VERSION 5.8 ;
BUSBITCHARS "[]" ;
DIVIDERCHAR "/" ;
UNITS
    DATABASE MICRONS 1000 ;
END UNITS

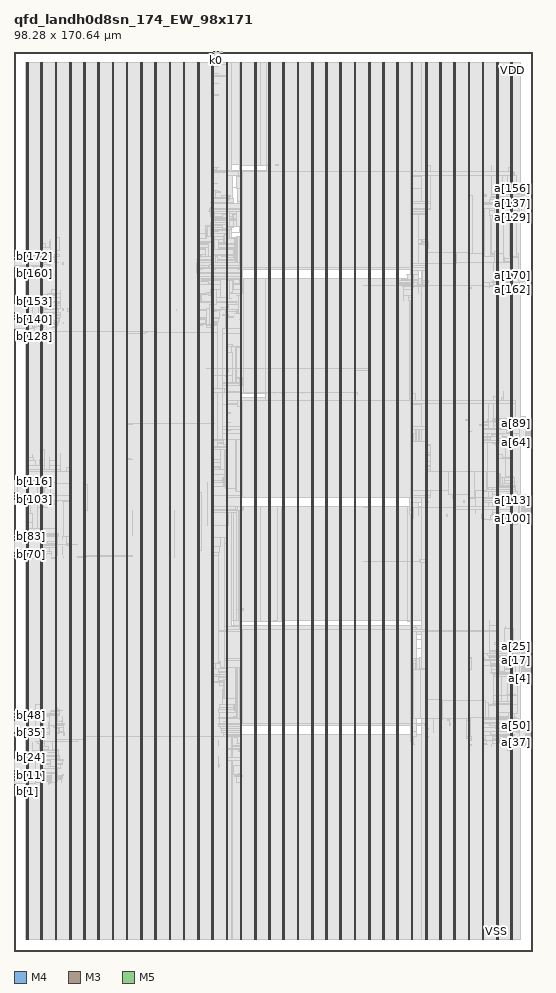
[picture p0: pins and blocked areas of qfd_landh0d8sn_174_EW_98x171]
MACRO qfd_landh0d8sn_174_EW_98x171
  FOREIGN qfd_landh0d8sn_174_EW_98x171 0 0 ;
  CLASS BLOCK ;
  SIZE 98.28 BY 170.64 ;
  PIN a[0]
    DIRECTION INPUT ;
    USE SIGNAL ;
    PORT
      LAYER M4 ;
        RECT  98.196 52.56 98.28 52.584 ;
    END
  END a[0]
  PIN a[100]
    DIRECTION INPUT ;
    USE SIGNAL ;
    PORT
      LAYER M4 ;
        RECT  98.196 81.936 98.28 81.96 ;
    END
  END a[100]
  PIN a[101]
    DIRECTION INPUT ;
    USE SIGNAL ;
    PORT
      LAYER M4 ;
        RECT  98.196 82.08 98.28 82.104 ;
    END
  END a[101]
  PIN a[102]
    DIRECTION INPUT ;
    USE SIGNAL ;
    PORT
      LAYER M4 ;
        RECT  98.196 82.224 98.28 82.248 ;
    END
  END a[102]
  PIN a[103]
    DIRECTION INPUT ;
    USE SIGNAL ;
    PORT
      LAYER M4 ;
        RECT  98.196 82.368 98.28 82.392 ;
    END
  END a[103]
  PIN a[104]
    DIRECTION INPUT ;
    USE SIGNAL ;
    PORT
      LAYER M4 ;
        RECT  98.196 82.512 98.28 82.536 ;
    END
  END a[104]
  PIN a[105]
    DIRECTION INPUT ;
    USE SIGNAL ;
    PORT
      LAYER M4 ;
        RECT  98.196 82.656 98.28 82.68 ;
    END
  END a[105]
  PIN a[106]
    DIRECTION INPUT ;
    USE SIGNAL ;
    PORT
      LAYER M4 ;
        RECT  98.196 82.8 98.28 82.824 ;
    END
  END a[106]
  PIN a[107]
    DIRECTION INPUT ;
    USE SIGNAL ;
    PORT
      LAYER M4 ;
        RECT  98.196 82.944 98.28 82.968 ;
    END
  END a[107]
  PIN a[108]
    DIRECTION INPUT ;
    USE SIGNAL ;
    PORT
      LAYER M4 ;
        RECT  98.196 83.088 98.28 83.112 ;
    END
  END a[108]
  PIN a[109]
    DIRECTION INPUT ;
    USE SIGNAL ;
    PORT
      LAYER M4 ;
        RECT  98.196 83.232 98.28 83.256 ;
    END
  END a[109]
  PIN a[10]
    DIRECTION INPUT ;
    USE SIGNAL ;
    PORT
      LAYER M4 ;
        RECT  98.196 54 98.28 54.024 ;
    END
  END a[10]
  PIN a[110]
    DIRECTION INPUT ;
    USE SIGNAL ;
    PORT
      LAYER M4 ;
        RECT  98.196 83.376 98.28 83.4 ;
    END
  END a[110]
  PIN a[111]
    DIRECTION INPUT ;
    USE SIGNAL ;
    PORT
      LAYER M4 ;
        RECT  98.196 83.52 98.28 83.544 ;
    END
  END a[111]
  PIN a[112]
    DIRECTION INPUT ;
    USE SIGNAL ;
    PORT
      LAYER M4 ;
        RECT  98.196 83.664 98.28 83.688 ;
    END
  END a[112]
  PIN a[113]
    DIRECTION INPUT ;
    USE SIGNAL ;
    PORT
      LAYER M4 ;
        RECT  98.196 83.808 98.28 83.832 ;
    END
  END a[113]
  PIN a[114]
    DIRECTION INPUT ;
    USE SIGNAL ;
    PORT
      LAYER M4 ;
        RECT  98.196 83.952 98.28 83.976 ;
    END
  END a[114]
  PIN a[115]
    DIRECTION INPUT ;
    USE SIGNAL ;
    PORT
      LAYER M4 ;
        RECT  98.196 84.096 98.28 84.12 ;
    END
  END a[115]
  PIN a[116]
    DIRECTION INPUT ;
    USE SIGNAL ;
    PORT
      LAYER M4 ;
        RECT  98.196 84.24 98.28 84.264 ;
    END
  END a[116]
  PIN a[117]
    DIRECTION INPUT ;
    USE SIGNAL ;
    PORT
      LAYER M4 ;
        RECT  98.196 84.384 98.28 84.408 ;
    END
  END a[117]
  PIN a[118]
    DIRECTION INPUT ;
    USE SIGNAL ;
    PORT
      LAYER M4 ;
        RECT  98.196 84.528 98.28 84.552 ;
    END
  END a[118]
  PIN a[119]
    DIRECTION INPUT ;
    USE SIGNAL ;
    PORT
      LAYER M4 ;
        RECT  98.196 84.672 98.28 84.696 ;
    END
  END a[119]
  PIN a[11]
    DIRECTION INPUT ;
    USE SIGNAL ;
    PORT
      LAYER M4 ;
        RECT  98.196 54.144 98.28 54.168 ;
    END
  END a[11]
  PIN a[120]
    DIRECTION INPUT ;
    USE SIGNAL ;
    PORT
      LAYER M4 ;
        RECT  98.196 84.816 98.28 84.84 ;
    END
  END a[120]
  PIN a[121]
    DIRECTION INPUT ;
    USE SIGNAL ;
    PORT
      LAYER M4 ;
        RECT  98.196 84.96 98.28 84.984 ;
    END
  END a[121]
  PIN a[122]
    DIRECTION INPUT ;
    USE SIGNAL ;
    PORT
      LAYER M4 ;
        RECT  98.196 85.104 98.28 85.128 ;
    END
  END a[122]
  PIN a[123]
    DIRECTION INPUT ;
    USE SIGNAL ;
    PORT
      LAYER M4 ;
        RECT  98.196 85.248 98.28 85.272 ;
    END
  END a[123]
  PIN a[124]
    DIRECTION INPUT ;
    USE SIGNAL ;
    PORT
      LAYER M4 ;
        RECT  98.196 85.392 98.28 85.416 ;
    END
  END a[124]
  PIN a[125]
    DIRECTION INPUT ;
    USE SIGNAL ;
    PORT
      LAYER M4 ;
        RECT  98.196 85.536 98.28 85.56 ;
    END
  END a[125]
  PIN a[126]
    DIRECTION INPUT ;
    USE SIGNAL ;
    PORT
      LAYER M4 ;
        RECT  98.196 85.68 98.28 85.704 ;
    END
  END a[126]
  PIN a[127]
    DIRECTION INPUT ;
    USE SIGNAL ;
    PORT
      LAYER M4 ;
        RECT  98.196 85.824 98.28 85.848 ;
    END
  END a[127]
  PIN a[128]
    DIRECTION INPUT ;
    USE SIGNAL ;
    PORT
      LAYER M4 ;
        RECT  98.196 138.96 98.28 138.984 ;
    END
  END a[128]
  PIN a[129]
    DIRECTION INPUT ;
    USE SIGNAL ;
    PORT
      LAYER M4 ;
        RECT  98.196 139.104 98.28 139.128 ;
    END
  END a[129]
  PIN a[12]
    DIRECTION INPUT ;
    USE SIGNAL ;
    PORT
      LAYER M4 ;
        RECT  98.196 54.288 98.28 54.312 ;
    END
  END a[12]
  PIN a[130]
    DIRECTION INPUT ;
    USE SIGNAL ;
    PORT
      LAYER M4 ;
        RECT  98.196 139.248 98.28 139.272 ;
    END
  END a[130]
  PIN a[131]
    DIRECTION INPUT ;
    USE SIGNAL ;
    PORT
      LAYER M4 ;
        RECT  98.196 139.392 98.28 139.416 ;
    END
  END a[131]
  PIN a[132]
    DIRECTION INPUT ;
    USE SIGNAL ;
    PORT
      LAYER M4 ;
        RECT  98.196 139.536 98.28 139.56 ;
    END
  END a[132]
  PIN a[133]
    DIRECTION INPUT ;
    USE SIGNAL ;
    PORT
      LAYER M4 ;
        RECT  98.196 139.68 98.28 139.704 ;
    END
  END a[133]
  PIN a[134]
    DIRECTION INPUT ;
    USE SIGNAL ;
    PORT
      LAYER M4 ;
        RECT  98.196 139.824 98.28 139.848 ;
    END
  END a[134]
  PIN a[135]
    DIRECTION INPUT ;
    USE SIGNAL ;
    PORT
      LAYER M4 ;
        RECT  98.196 139.968 98.28 139.992 ;
    END
  END a[135]
  PIN a[136]
    DIRECTION INPUT ;
    USE SIGNAL ;
    PORT
      LAYER M4 ;
        RECT  98.196 140.112 98.28 140.136 ;
    END
  END a[136]
  PIN a[137]
    DIRECTION INPUT ;
    USE SIGNAL ;
    PORT
      LAYER M4 ;
        RECT  98.196 140.256 98.28 140.28 ;
    END
  END a[137]
  PIN a[138]
    DIRECTION INPUT ;
    USE SIGNAL ;
    PORT
      LAYER M4 ;
        RECT  98.196 140.4 98.28 140.424 ;
    END
  END a[138]
  PIN a[139]
    DIRECTION INPUT ;
    USE SIGNAL ;
    PORT
      LAYER M4 ;
        RECT  98.196 140.544 98.28 140.568 ;
    END
  END a[139]
  PIN a[13]
    DIRECTION INPUT ;
    USE SIGNAL ;
    PORT
      LAYER M4 ;
        RECT  98.196 54.432 98.28 54.456 ;
    END
  END a[13]
  PIN a[140]
    DIRECTION INPUT ;
    USE SIGNAL ;
    PORT
      LAYER M4 ;
        RECT  98.196 140.688 98.28 140.712 ;
    END
  END a[140]
  PIN a[141]
    DIRECTION INPUT ;
    USE SIGNAL ;
    PORT
      LAYER M4 ;
        RECT  98.196 140.832 98.28 140.856 ;
    END
  END a[141]
  PIN a[142]
    DIRECTION INPUT ;
    USE SIGNAL ;
    PORT
      LAYER M4 ;
        RECT  98.196 140.976 98.28 141 ;
    END
  END a[142]
  PIN a[143]
    DIRECTION INPUT ;
    USE SIGNAL ;
    PORT
      LAYER M4 ;
        RECT  98.196 141.12 98.28 141.144 ;
    END
  END a[143]
  PIN a[144]
    DIRECTION INPUT ;
    USE SIGNAL ;
    PORT
      LAYER M4 ;
        RECT  98.196 141.264 98.28 141.288 ;
    END
  END a[144]
  PIN a[145]
    DIRECTION INPUT ;
    USE SIGNAL ;
    PORT
      LAYER M4 ;
        RECT  98.196 141.408 98.28 141.432 ;
    END
  END a[145]
  PIN a[146]
    DIRECTION INPUT ;
    USE SIGNAL ;
    PORT
      LAYER M4 ;
        RECT  98.196 141.552 98.28 141.576 ;
    END
  END a[146]
  PIN a[147]
    DIRECTION INPUT ;
    USE SIGNAL ;
    PORT
      LAYER M4 ;
        RECT  98.196 141.696 98.28 141.72 ;
    END
  END a[147]
  PIN a[148]
    DIRECTION INPUT ;
    USE SIGNAL ;
    PORT
      LAYER M4 ;
        RECT  98.196 141.84 98.28 141.864 ;
    END
  END a[148]
  PIN a[149]
    DIRECTION INPUT ;
    USE SIGNAL ;
    PORT
      LAYER M4 ;
        RECT  98.196 141.984 98.28 142.008 ;
    END
  END a[149]
  PIN a[14]
    DIRECTION INPUT ;
    USE SIGNAL ;
    PORT
      LAYER M4 ;
        RECT  98.196 54.576 98.28 54.6 ;
    END
  END a[14]
  PIN a[150]
    DIRECTION INPUT ;
    USE SIGNAL ;
    PORT
      LAYER M4 ;
        RECT  98.196 142.128 98.28 142.152 ;
    END
  END a[150]
  PIN a[151]
    DIRECTION INPUT ;
    USE SIGNAL ;
    PORT
      LAYER M4 ;
        RECT  98.196 142.272 98.28 142.296 ;
    END
  END a[151]
  PIN a[152]
    DIRECTION INPUT ;
    USE SIGNAL ;
    PORT
      LAYER M4 ;
        RECT  98.196 142.416 98.28 142.44 ;
    END
  END a[152]
  PIN a[153]
    DIRECTION INPUT ;
    USE SIGNAL ;
    PORT
      LAYER M4 ;
        RECT  98.196 142.56 98.28 142.584 ;
    END
  END a[153]
  PIN a[154]
    DIRECTION INPUT ;
    USE SIGNAL ;
    PORT
      LAYER M4 ;
        RECT  98.196 142.704 98.28 142.728 ;
    END
  END a[154]
  PIN a[155]
    DIRECTION INPUT ;
    USE SIGNAL ;
    PORT
      LAYER M4 ;
        RECT  98.196 142.848 98.28 142.872 ;
    END
  END a[155]
  PIN a[156]
    DIRECTION INPUT ;
    USE SIGNAL ;
    PORT
      LAYER M4 ;
        RECT  98.196 142.992 98.28 143.016 ;
    END
  END a[156]
  PIN a[157]
    DIRECTION INPUT ;
    USE SIGNAL ;
    PORT
      LAYER M4 ;
        RECT  98.196 143.136 98.28 143.16 ;
    END
  END a[157]
  PIN a[158]
    DIRECTION INPUT ;
    USE SIGNAL ;
    PORT
      LAYER M4 ;
        RECT  98.196 143.28 98.28 143.304 ;
    END
  END a[158]
  PIN a[159]
    DIRECTION INPUT ;
    USE SIGNAL ;
    PORT
      LAYER M4 ;
        RECT  98.196 143.424 98.28 143.448 ;
    END
  END a[159]
  PIN a[15]
    DIRECTION INPUT ;
    USE SIGNAL ;
    PORT
      LAYER M4 ;
        RECT  98.196 54.72 98.28 54.744 ;
    END
  END a[15]
  PIN a[160]
    DIRECTION INPUT ;
    USE SIGNAL ;
    PORT
      LAYER M4 ;
        RECT  98.196 125.136 98.28 125.16 ;
    END
  END a[160]
  PIN a[161]
    DIRECTION INPUT ;
    USE SIGNAL ;
    PORT
      LAYER M4 ;
        RECT  98.196 125.28 98.28 125.304 ;
    END
  END a[161]
  PIN a[162]
    DIRECTION INPUT ;
    USE SIGNAL ;
    PORT
      LAYER M4 ;
        RECT  98.196 125.424 98.28 125.448 ;
    END
  END a[162]
  PIN a[163]
    DIRECTION INPUT ;
    USE SIGNAL ;
    PORT
      LAYER M4 ;
        RECT  98.196 125.568 98.28 125.592 ;
    END
  END a[163]
  PIN a[164]
    DIRECTION INPUT ;
    USE SIGNAL ;
    PORT
      LAYER M4 ;
        RECT  98.196 125.712 98.28 125.736 ;
    END
  END a[164]
  PIN a[165]
    DIRECTION INPUT ;
    USE SIGNAL ;
    PORT
      LAYER M4 ;
        RECT  98.196 125.856 98.28 125.88 ;
    END
  END a[165]
  PIN a[166]
    DIRECTION INPUT ;
    USE SIGNAL ;
    PORT
      LAYER M4 ;
        RECT  98.196 126 98.28 126.024 ;
    END
  END a[166]
  PIN a[167]
    DIRECTION INPUT ;
    USE SIGNAL ;
    PORT
      LAYER M4 ;
        RECT  98.196 126.144 98.28 126.168 ;
    END
  END a[167]
  PIN a[168]
    DIRECTION INPUT ;
    USE SIGNAL ;
    PORT
      LAYER M4 ;
        RECT  98.196 126.288 98.28 126.312 ;
    END
  END a[168]
  PIN a[169]
    DIRECTION INPUT ;
    USE SIGNAL ;
    PORT
      LAYER M4 ;
        RECT  98.196 126.432 98.28 126.456 ;
    END
  END a[169]
  PIN a[16]
    DIRECTION INPUT ;
    USE SIGNAL ;
    PORT
      LAYER M4 ;
        RECT  98.196 54.864 98.28 54.888 ;
    END
  END a[16]
  PIN a[170]
    DIRECTION INPUT ;
    USE SIGNAL ;
    PORT
      LAYER M4 ;
        RECT  98.196 126.576 98.28 126.6 ;
    END
  END a[170]
  PIN a[171]
    DIRECTION INPUT ;
    USE SIGNAL ;
    PORT
      LAYER M4 ;
        RECT  98.196 126.72 98.28 126.744 ;
    END
  END a[171]
  PIN a[172]
    DIRECTION INPUT ;
    USE SIGNAL ;
    PORT
      LAYER M4 ;
        RECT  98.196 126.864 98.28 126.888 ;
    END
  END a[172]
  PIN a[173]
    DIRECTION INPUT ;
    USE SIGNAL ;
    PORT
      LAYER M4 ;
        RECT  98.196 127.008 98.28 127.032 ;
    END
  END a[173]
  PIN a[17]
    DIRECTION INPUT ;
    USE SIGNAL ;
    PORT
      LAYER M4 ;
        RECT  98.196 55.008 98.28 55.032 ;
    END
  END a[17]
  PIN a[18]
    DIRECTION INPUT ;
    USE SIGNAL ;
    PORT
      LAYER M4 ;
        RECT  98.196 55.152 98.28 55.176 ;
    END
  END a[18]
  PIN a[19]
    DIRECTION INPUT ;
    USE SIGNAL ;
    PORT
      LAYER M4 ;
        RECT  98.196 55.296 98.28 55.32 ;
    END
  END a[19]
  PIN a[1]
    DIRECTION INPUT ;
    USE SIGNAL ;
    PORT
      LAYER M4 ;
        RECT  98.196 52.704 98.28 52.728 ;
    END
  END a[1]
  PIN a[20]
    DIRECTION INPUT ;
    USE SIGNAL ;
    PORT
      LAYER M4 ;
        RECT  98.196 55.44 98.28 55.464 ;
    END
  END a[20]
  PIN a[21]
    DIRECTION INPUT ;
    USE SIGNAL ;
    PORT
      LAYER M4 ;
        RECT  98.196 55.584 98.28 55.608 ;
    END
  END a[21]
  PIN a[22]
    DIRECTION INPUT ;
    USE SIGNAL ;
    PORT
      LAYER M4 ;
        RECT  98.196 55.728 98.28 55.752 ;
    END
  END a[22]
  PIN a[23]
    DIRECTION INPUT ;
    USE SIGNAL ;
    PORT
      LAYER M4 ;
        RECT  98.196 55.872 98.28 55.896 ;
    END
  END a[23]
  PIN a[24]
    DIRECTION INPUT ;
    USE SIGNAL ;
    PORT
      LAYER M4 ;
        RECT  98.196 56.016 98.28 56.04 ;
    END
  END a[24]
  PIN a[25]
    DIRECTION INPUT ;
    USE SIGNAL ;
    PORT
      LAYER M4 ;
        RECT  98.196 56.16 98.28 56.184 ;
    END
  END a[25]
  PIN a[26]
    DIRECTION INPUT ;
    USE SIGNAL ;
    PORT
      LAYER M4 ;
        RECT  98.196 56.304 98.28 56.328 ;
    END
  END a[26]
  PIN a[27]
    DIRECTION INPUT ;
    USE SIGNAL ;
    PORT
      LAYER M4 ;
        RECT  98.196 56.448 98.28 56.472 ;
    END
  END a[27]
  PIN a[28]
    DIRECTION INPUT ;
    USE SIGNAL ;
    PORT
      LAYER M4 ;
        RECT  98.196 56.592 98.28 56.616 ;
    END
  END a[28]
  PIN a[29]
    DIRECTION INPUT ;
    USE SIGNAL ;
    PORT
      LAYER M4 ;
        RECT  98.196 56.736 98.28 56.76 ;
    END
  END a[29]
  PIN a[2]
    DIRECTION INPUT ;
    USE SIGNAL ;
    PORT
      LAYER M4 ;
        RECT  98.196 52.848 98.28 52.872 ;
    END
  END a[2]
  PIN a[30]
    DIRECTION INPUT ;
    USE SIGNAL ;
    PORT
      LAYER M4 ;
        RECT  98.196 56.88 98.28 56.904 ;
    END
  END a[30]
  PIN a[31]
    DIRECTION INPUT ;
    USE SIGNAL ;
    PORT
      LAYER M4 ;
        RECT  98.196 57.024 98.28 57.048 ;
    END
  END a[31]
  PIN a[32]
    DIRECTION INPUT ;
    USE SIGNAL ;
    PORT
      LAYER M4 ;
        RECT  98.196 38.736 98.28 38.76 ;
    END
  END a[32]
  PIN a[33]
    DIRECTION INPUT ;
    USE SIGNAL ;
    PORT
      LAYER M4 ;
        RECT  98.196 38.88 98.28 38.904 ;
    END
  END a[33]
  PIN a[34]
    DIRECTION INPUT ;
    USE SIGNAL ;
    PORT
      LAYER M4 ;
        RECT  98.196 39.024 98.28 39.048 ;
    END
  END a[34]
  PIN a[35]
    DIRECTION INPUT ;
    USE SIGNAL ;
    PORT
      LAYER M4 ;
        RECT  98.196 39.168 98.28 39.192 ;
    END
  END a[35]
  PIN a[36]
    DIRECTION INPUT ;
    USE SIGNAL ;
    PORT
      LAYER M4 ;
        RECT  98.196 39.312 98.28 39.336 ;
    END
  END a[36]
  PIN a[37]
    DIRECTION INPUT ;
    USE SIGNAL ;
    PORT
      LAYER M4 ;
        RECT  98.196 39.456 98.28 39.48 ;
    END
  END a[37]
  PIN a[38]
    DIRECTION INPUT ;
    USE SIGNAL ;
    PORT
      LAYER M4 ;
        RECT  98.196 39.6 98.28 39.624 ;
    END
  END a[38]
  PIN a[39]
    DIRECTION INPUT ;
    USE SIGNAL ;
    PORT
      LAYER M4 ;
        RECT  98.196 39.744 98.28 39.768 ;
    END
  END a[39]
  PIN a[3]
    DIRECTION INPUT ;
    USE SIGNAL ;
    PORT
      LAYER M4 ;
        RECT  98.196 52.992 98.28 53.016 ;
    END
  END a[3]
  PIN a[40]
    DIRECTION INPUT ;
    USE SIGNAL ;
    PORT
      LAYER M4 ;
        RECT  98.196 39.888 98.28 39.912 ;
    END
  END a[40]
  PIN a[41]
    DIRECTION INPUT ;
    USE SIGNAL ;
    PORT
      LAYER M4 ;
        RECT  98.196 40.032 98.28 40.056 ;
    END
  END a[41]
  PIN a[42]
    DIRECTION INPUT ;
    USE SIGNAL ;
    PORT
      LAYER M4 ;
        RECT  98.196 40.176 98.28 40.2 ;
    END
  END a[42]
  PIN a[43]
    DIRECTION INPUT ;
    USE SIGNAL ;
    PORT
      LAYER M4 ;
        RECT  98.196 40.32 98.28 40.344 ;
    END
  END a[43]
  PIN a[44]
    DIRECTION INPUT ;
    USE SIGNAL ;
    PORT
      LAYER M4 ;
        RECT  98.196 40.464 98.28 40.488 ;
    END
  END a[44]
  PIN a[45]
    DIRECTION INPUT ;
    USE SIGNAL ;
    PORT
      LAYER M4 ;
        RECT  98.196 40.608 98.28 40.632 ;
    END
  END a[45]
  PIN a[46]
    DIRECTION INPUT ;
    USE SIGNAL ;
    PORT
      LAYER M4 ;
        RECT  98.196 40.752 98.28 40.776 ;
    END
  END a[46]
  PIN a[47]
    DIRECTION INPUT ;
    USE SIGNAL ;
    PORT
      LAYER M4 ;
        RECT  98.196 40.896 98.28 40.92 ;
    END
  END a[47]
  PIN a[48]
    DIRECTION INPUT ;
    USE SIGNAL ;
    PORT
      LAYER M4 ;
        RECT  98.196 41.04 98.28 41.064 ;
    END
  END a[48]
  PIN a[49]
    DIRECTION INPUT ;
    USE SIGNAL ;
    PORT
      LAYER M4 ;
        RECT  98.196 41.184 98.28 41.208 ;
    END
  END a[49]
  PIN a[4]
    DIRECTION INPUT ;
    USE SIGNAL ;
    PORT
      LAYER M4 ;
        RECT  98.196 53.136 98.28 53.16 ;
    END
  END a[4]
  PIN a[50]
    DIRECTION INPUT ;
    USE SIGNAL ;
    PORT
      LAYER M4 ;
        RECT  98.196 41.328 98.28 41.352 ;
    END
  END a[50]
  PIN a[51]
    DIRECTION INPUT ;
    USE SIGNAL ;
    PORT
      LAYER M4 ;
        RECT  98.196 41.472 98.28 41.496 ;
    END
  END a[51]
  PIN a[52]
    DIRECTION INPUT ;
    USE SIGNAL ;
    PORT
      LAYER M4 ;
        RECT  98.196 41.616 98.28 41.64 ;
    END
  END a[52]
  PIN a[53]
    DIRECTION INPUT ;
    USE SIGNAL ;
    PORT
      LAYER M4 ;
        RECT  98.196 41.76 98.28 41.784 ;
    END
  END a[53]
  PIN a[54]
    DIRECTION INPUT ;
    USE SIGNAL ;
    PORT
      LAYER M4 ;
        RECT  98.196 41.904 98.28 41.928 ;
    END
  END a[54]
  PIN a[55]
    DIRECTION INPUT ;
    USE SIGNAL ;
    PORT
      LAYER M4 ;
        RECT  98.196 42.048 98.28 42.072 ;
    END
  END a[55]
  PIN a[56]
    DIRECTION INPUT ;
    USE SIGNAL ;
    PORT
      LAYER M4 ;
        RECT  98.196 42.192 98.28 42.216 ;
    END
  END a[56]
  PIN a[57]
    DIRECTION INPUT ;
    USE SIGNAL ;
    PORT
      LAYER M4 ;
        RECT  98.196 42.336 98.28 42.36 ;
    END
  END a[57]
  PIN a[58]
    DIRECTION INPUT ;
    USE SIGNAL ;
    PORT
      LAYER M4 ;
        RECT  98.196 42.48 98.28 42.504 ;
    END
  END a[58]
  PIN a[59]
    DIRECTION INPUT ;
    USE SIGNAL ;
    PORT
      LAYER M4 ;
        RECT  98.196 42.624 98.28 42.648 ;
    END
  END a[59]
  PIN a[5]
    DIRECTION INPUT ;
    USE SIGNAL ;
    PORT
      LAYER M4 ;
        RECT  98.196 53.28 98.28 53.304 ;
    END
  END a[5]
  PIN a[60]
    DIRECTION INPUT ;
    USE SIGNAL ;
    PORT
      LAYER M4 ;
        RECT  98.196 42.768 98.28 42.792 ;
    END
  END a[60]
  PIN a[61]
    DIRECTION INPUT ;
    USE SIGNAL ;
    PORT
      LAYER M4 ;
        RECT  98.196 42.912 98.28 42.936 ;
    END
  END a[61]
  PIN a[62]
    DIRECTION INPUT ;
    USE SIGNAL ;
    PORT
      LAYER M4 ;
        RECT  98.196 43.056 98.28 43.08 ;
    END
  END a[62]
  PIN a[63]
    DIRECTION INPUT ;
    USE SIGNAL ;
    PORT
      LAYER M4 ;
        RECT  98.196 43.2 98.28 43.224 ;
    END
  END a[63]
  PIN a[64]
    DIRECTION INPUT ;
    USE SIGNAL ;
    PORT
      LAYER M4 ;
        RECT  98.196 96.336 98.28 96.36 ;
    END
  END a[64]
  PIN a[65]
    DIRECTION INPUT ;
    USE SIGNAL ;
    PORT
      LAYER M4 ;
        RECT  98.196 96.48 98.28 96.504 ;
    END
  END a[65]
  PIN a[66]
    DIRECTION INPUT ;
    USE SIGNAL ;
    PORT
      LAYER M4 ;
        RECT  98.196 96.624 98.28 96.648 ;
    END
  END a[66]
  PIN a[67]
    DIRECTION INPUT ;
    USE SIGNAL ;
    PORT
      LAYER M4 ;
        RECT  98.196 96.768 98.28 96.792 ;
    END
  END a[67]
  PIN a[68]
    DIRECTION INPUT ;
    USE SIGNAL ;
    PORT
      LAYER M4 ;
        RECT  98.196 96.912 98.28 96.936 ;
    END
  END a[68]
  PIN a[69]
    DIRECTION INPUT ;
    USE SIGNAL ;
    PORT
      LAYER M4 ;
        RECT  98.196 97.056 98.28 97.08 ;
    END
  END a[69]
  PIN a[6]
    DIRECTION INPUT ;
    USE SIGNAL ;
    PORT
      LAYER M4 ;
        RECT  98.196 53.424 98.28 53.448 ;
    END
  END a[6]
  PIN a[70]
    DIRECTION INPUT ;
    USE SIGNAL ;
    PORT
      LAYER M4 ;
        RECT  98.196 97.2 98.28 97.224 ;
    END
  END a[70]
  PIN a[71]
    DIRECTION INPUT ;
    USE SIGNAL ;
    PORT
      LAYER M4 ;
        RECT  98.196 97.344 98.28 97.368 ;
    END
  END a[71]
  PIN a[72]
    DIRECTION INPUT ;
    USE SIGNAL ;
    PORT
      LAYER M4 ;
        RECT  98.196 97.488 98.28 97.512 ;
    END
  END a[72]
  PIN a[73]
    DIRECTION INPUT ;
    USE SIGNAL ;
    PORT
      LAYER M4 ;
        RECT  98.196 97.632 98.28 97.656 ;
    END
  END a[73]
  PIN a[74]
    DIRECTION INPUT ;
    USE SIGNAL ;
    PORT
      LAYER M4 ;
        RECT  98.196 97.776 98.28 97.8 ;
    END
  END a[74]
  PIN a[75]
    DIRECTION INPUT ;
    USE SIGNAL ;
    PORT
      LAYER M4 ;
        RECT  98.196 97.92 98.28 97.944 ;
    END
  END a[75]
  PIN a[76]
    DIRECTION INPUT ;
    USE SIGNAL ;
    PORT
      LAYER M4 ;
        RECT  98.196 98.064 98.28 98.088 ;
    END
  END a[76]
  PIN a[77]
    DIRECTION INPUT ;
    USE SIGNAL ;
    PORT
      LAYER M4 ;
        RECT  98.196 98.208 98.28 98.232 ;
    END
  END a[77]
  PIN a[78]
    DIRECTION INPUT ;
    USE SIGNAL ;
    PORT
      LAYER M4 ;
        RECT  98.196 98.352 98.28 98.376 ;
    END
  END a[78]
  PIN a[79]
    DIRECTION INPUT ;
    USE SIGNAL ;
    PORT
      LAYER M4 ;
        RECT  98.196 98.496 98.28 98.52 ;
    END
  END a[79]
  PIN a[7]
    DIRECTION INPUT ;
    USE SIGNAL ;
    PORT
      LAYER M4 ;
        RECT  98.196 53.568 98.28 53.592 ;
    END
  END a[7]
  PIN a[80]
    DIRECTION INPUT ;
    USE SIGNAL ;
    PORT
      LAYER M4 ;
        RECT  98.196 98.64 98.28 98.664 ;
    END
  END a[80]
  PIN a[81]
    DIRECTION INPUT ;
    USE SIGNAL ;
    PORT
      LAYER M4 ;
        RECT  98.196 98.784 98.28 98.808 ;
    END
  END a[81]
  PIN a[82]
    DIRECTION INPUT ;
    USE SIGNAL ;
    PORT
      LAYER M4 ;
        RECT  98.196 98.928 98.28 98.952 ;
    END
  END a[82]
  PIN a[83]
    DIRECTION INPUT ;
    USE SIGNAL ;
    PORT
      LAYER M4 ;
        RECT  98.196 99.072 98.28 99.096 ;
    END
  END a[83]
  PIN a[84]
    DIRECTION INPUT ;
    USE SIGNAL ;
    PORT
      LAYER M4 ;
        RECT  98.196 99.216 98.28 99.24 ;
    END
  END a[84]
  PIN a[85]
    DIRECTION INPUT ;
    USE SIGNAL ;
    PORT
      LAYER M4 ;
        RECT  98.196 99.36 98.28 99.384 ;
    END
  END a[85]
  PIN a[86]
    DIRECTION INPUT ;
    USE SIGNAL ;
    PORT
      LAYER M4 ;
        RECT  98.196 99.504 98.28 99.528 ;
    END
  END a[86]
  PIN a[87]
    DIRECTION INPUT ;
    USE SIGNAL ;
    PORT
      LAYER M4 ;
        RECT  98.196 99.648 98.28 99.672 ;
    END
  END a[87]
  PIN a[88]
    DIRECTION INPUT ;
    USE SIGNAL ;
    PORT
      LAYER M4 ;
        RECT  98.196 99.792 98.28 99.816 ;
    END
  END a[88]
  PIN a[89]
    DIRECTION INPUT ;
    USE SIGNAL ;
    PORT
      LAYER M4 ;
        RECT  98.196 99.936 98.28 99.96 ;
    END
  END a[89]
  PIN a[8]
    DIRECTION INPUT ;
    USE SIGNAL ;
    PORT
      LAYER M4 ;
        RECT  98.196 53.712 98.28 53.736 ;
    END
  END a[8]
  PIN a[90]
    DIRECTION INPUT ;
    USE SIGNAL ;
    PORT
      LAYER M4 ;
        RECT  98.196 100.08 98.28 100.104 ;
    END
  END a[90]
  PIN a[91]
    DIRECTION INPUT ;
    USE SIGNAL ;
    PORT
      LAYER M4 ;
        RECT  98.196 100.224 98.28 100.248 ;
    END
  END a[91]
  PIN a[92]
    DIRECTION INPUT ;
    USE SIGNAL ;
    PORT
      LAYER M4 ;
        RECT  98.196 100.368 98.28 100.392 ;
    END
  END a[92]
  PIN a[93]
    DIRECTION INPUT ;
    USE SIGNAL ;
    PORT
      LAYER M4 ;
        RECT  98.196 100.512 98.28 100.536 ;
    END
  END a[93]
  PIN a[94]
    DIRECTION INPUT ;
    USE SIGNAL ;
    PORT
      LAYER M4 ;
        RECT  98.196 100.656 98.28 100.68 ;
    END
  END a[94]
  PIN a[95]
    DIRECTION INPUT ;
    USE SIGNAL ;
    PORT
      LAYER M4 ;
        RECT  98.196 100.8 98.28 100.824 ;
    END
  END a[95]
  PIN a[96]
    DIRECTION INPUT ;
    USE SIGNAL ;
    PORT
      LAYER M4 ;
        RECT  98.196 81.36 98.28 81.384 ;
    END
  END a[96]
  PIN a[97]
    DIRECTION INPUT ;
    USE SIGNAL ;
    PORT
      LAYER M4 ;
        RECT  98.196 81.504 98.28 81.528 ;
    END
  END a[97]
  PIN a[98]
    DIRECTION INPUT ;
    USE SIGNAL ;
    PORT
      LAYER M4 ;
        RECT  98.196 81.648 98.28 81.672 ;
    END
  END a[98]
  PIN a[99]
    DIRECTION INPUT ;
    USE SIGNAL ;
    PORT
      LAYER M4 ;
        RECT  98.196 81.792 98.28 81.816 ;
    END
  END a[99]
  PIN a[9]
    DIRECTION INPUT ;
    USE SIGNAL ;
    PORT
      LAYER M4 ;
        RECT  98.196 53.856 98.28 53.88 ;
    END
  END a[9]
  PIN b[0]
    DIRECTION OUTPUT ;
    USE SIGNAL ;
    PORT
      LAYER M4 ;
        RECT  0 31.68 0.084 31.704 ;
    END
  END b[0]
  PIN b[100]
    DIRECTION OUTPUT ;
    USE SIGNAL ;
    PORT
      LAYER M4 ;
        RECT  0 85.248 0.084 85.272 ;
    END
  END b[100]
  PIN b[101]
    DIRECTION OUTPUT ;
    USE SIGNAL ;
    PORT
      LAYER M4 ;
        RECT  0 85.392 0.084 85.416 ;
    END
  END b[101]
  PIN b[102]
    DIRECTION OUTPUT ;
    USE SIGNAL ;
    PORT
      LAYER M4 ;
        RECT  0 85.536 0.084 85.56 ;
    END
  END b[102]
  PIN b[103]
    DIRECTION OUTPUT ;
    USE SIGNAL ;
    PORT
      LAYER M4 ;
        RECT  0 85.68 0.084 85.704 ;
    END
  END b[103]
  PIN b[104]
    DIRECTION OUTPUT ;
    USE SIGNAL ;
    PORT
      LAYER M4 ;
        RECT  0 85.824 0.084 85.848 ;
    END
  END b[104]
  PIN b[105]
    DIRECTION OUTPUT ;
    USE SIGNAL ;
    PORT
      LAYER M4 ;
        RECT  0 85.968 0.084 85.992 ;
    END
  END b[105]
  PIN b[106]
    DIRECTION OUTPUT ;
    USE SIGNAL ;
    PORT
      LAYER M4 ;
        RECT  0 86.112 0.084 86.136 ;
    END
  END b[106]
  PIN b[107]
    DIRECTION OUTPUT ;
    USE SIGNAL ;
    PORT
      LAYER M4 ;
        RECT  0 86.256 0.084 86.28 ;
    END
  END b[107]
  PIN b[108]
    DIRECTION OUTPUT ;
    USE SIGNAL ;
    PORT
      LAYER M4 ;
        RECT  0 86.4 0.084 86.424 ;
    END
  END b[108]
  PIN b[109]
    DIRECTION OUTPUT ;
    USE SIGNAL ;
    PORT
      LAYER M4 ;
        RECT  0 86.544 0.084 86.568 ;
    END
  END b[109]
  PIN b[10]
    DIRECTION OUTPUT ;
    USE SIGNAL ;
    PORT
      LAYER M4 ;
        RECT  0 33.12 0.084 33.144 ;
    END
  END b[10]
  PIN b[110]
    DIRECTION OUTPUT ;
    USE SIGNAL ;
    PORT
      LAYER M4 ;
        RECT  0 86.688 0.084 86.712 ;
    END
  END b[110]
  PIN b[111]
    DIRECTION OUTPUT ;
    USE SIGNAL ;
    PORT
      LAYER M4 ;
        RECT  0 86.832 0.084 86.856 ;
    END
  END b[111]
  PIN b[112]
    DIRECTION OUTPUT ;
    USE SIGNAL ;
    PORT
      LAYER M4 ;
        RECT  0 86.976 0.084 87 ;
    END
  END b[112]
  PIN b[113]
    DIRECTION OUTPUT ;
    USE SIGNAL ;
    PORT
      LAYER M4 ;
        RECT  0 87.12 0.084 87.144 ;
    END
  END b[113]
  PIN b[114]
    DIRECTION OUTPUT ;
    USE SIGNAL ;
    PORT
      LAYER M4 ;
        RECT  0 87.264 0.084 87.288 ;
    END
  END b[114]
  PIN b[115]
    DIRECTION OUTPUT ;
    USE SIGNAL ;
    PORT
      LAYER M4 ;
        RECT  0 87.408 0.084 87.432 ;
    END
  END b[115]
  PIN b[116]
    DIRECTION OUTPUT ;
    USE SIGNAL ;
    PORT
      LAYER M4 ;
        RECT  0 87.552 0.084 87.576 ;
    END
  END b[116]
  PIN b[117]
    DIRECTION OUTPUT ;
    USE SIGNAL ;
    PORT
      LAYER M4 ;
        RECT  0 87.696 0.084 87.72 ;
    END
  END b[117]
  PIN b[118]
    DIRECTION OUTPUT ;
    USE SIGNAL ;
    PORT
      LAYER M4 ;
        RECT  0 87.84 0.084 87.864 ;
    END
  END b[118]
  PIN b[119]
    DIRECTION OUTPUT ;
    USE SIGNAL ;
    PORT
      LAYER M4 ;
        RECT  0 87.984 0.084 88.008 ;
    END
  END b[119]
  PIN b[11]
    DIRECTION OUTPUT ;
    USE SIGNAL ;
    PORT
      LAYER M4 ;
        RECT  0 33.264 0.084 33.288 ;
    END
  END b[11]
  PIN b[120]
    DIRECTION OUTPUT ;
    USE SIGNAL ;
    PORT
      LAYER M4 ;
        RECT  0 88.128 0.084 88.152 ;
    END
  END b[120]
  PIN b[121]
    DIRECTION OUTPUT ;
    USE SIGNAL ;
    PORT
      LAYER M4 ;
        RECT  0 88.272 0.084 88.296 ;
    END
  END b[121]
  PIN b[122]
    DIRECTION OUTPUT ;
    USE SIGNAL ;
    PORT
      LAYER M4 ;
        RECT  0 88.416 0.084 88.44 ;
    END
  END b[122]
  PIN b[123]
    DIRECTION OUTPUT ;
    USE SIGNAL ;
    PORT
      LAYER M4 ;
        RECT  0 88.56 0.084 88.584 ;
    END
  END b[123]
  PIN b[124]
    DIRECTION OUTPUT ;
    USE SIGNAL ;
    PORT
      LAYER M4 ;
        RECT  0 88.704 0.084 88.728 ;
    END
  END b[124]
  PIN b[125]
    DIRECTION OUTPUT ;
    USE SIGNAL ;
    PORT
      LAYER M4 ;
        RECT  0 88.848 0.084 88.872 ;
    END
  END b[125]
  PIN b[126]
    DIRECTION OUTPUT ;
    USE SIGNAL ;
    PORT
      LAYER M4 ;
        RECT  0 88.992 0.084 89.016 ;
    END
  END b[126]
  PIN b[127]
    DIRECTION OUTPUT ;
    USE SIGNAL ;
    PORT
      LAYER M4 ;
        RECT  0 89.136 0.084 89.16 ;
    END
  END b[127]
  PIN b[128]
    DIRECTION OUTPUT ;
    USE SIGNAL ;
    PORT
      LAYER M4 ;
        RECT  0 118.08 0.084 118.104 ;
    END
  END b[128]
  PIN b[129]
    DIRECTION OUTPUT ;
    USE SIGNAL ;
    PORT
      LAYER M4 ;
        RECT  0 118.224 0.084 118.248 ;
    END
  END b[129]
  PIN b[12]
    DIRECTION OUTPUT ;
    USE SIGNAL ;
    PORT
      LAYER M4 ;
        RECT  0 33.408 0.084 33.432 ;
    END
  END b[12]
  PIN b[130]
    DIRECTION OUTPUT ;
    USE SIGNAL ;
    PORT
      LAYER M4 ;
        RECT  0 118.368 0.084 118.392 ;
    END
  END b[130]
  PIN b[131]
    DIRECTION OUTPUT ;
    USE SIGNAL ;
    PORT
      LAYER M4 ;
        RECT  0 118.512 0.084 118.536 ;
    END
  END b[131]
  PIN b[132]
    DIRECTION OUTPUT ;
    USE SIGNAL ;
    PORT
      LAYER M4 ;
        RECT  0 118.656 0.084 118.68 ;
    END
  END b[132]
  PIN b[133]
    DIRECTION OUTPUT ;
    USE SIGNAL ;
    PORT
      LAYER M4 ;
        RECT  0 118.8 0.084 118.824 ;
    END
  END b[133]
  PIN b[134]
    DIRECTION OUTPUT ;
    USE SIGNAL ;
    PORT
      LAYER M4 ;
        RECT  0 118.944 0.084 118.968 ;
    END
  END b[134]
  PIN b[135]
    DIRECTION OUTPUT ;
    USE SIGNAL ;
    PORT
      LAYER M4 ;
        RECT  0 119.088 0.084 119.112 ;
    END
  END b[135]
  PIN b[136]
    DIRECTION OUTPUT ;
    USE SIGNAL ;
    PORT
      LAYER M4 ;
        RECT  0 119.232 0.084 119.256 ;
    END
  END b[136]
  PIN b[137]
    DIRECTION OUTPUT ;
    USE SIGNAL ;
    PORT
      LAYER M4 ;
        RECT  0 119.376 0.084 119.4 ;
    END
  END b[137]
  PIN b[138]
    DIRECTION OUTPUT ;
    USE SIGNAL ;
    PORT
      LAYER M4 ;
        RECT  0 119.52 0.084 119.544 ;
    END
  END b[138]
  PIN b[139]
    DIRECTION OUTPUT ;
    USE SIGNAL ;
    PORT
      LAYER M4 ;
        RECT  0 119.664 0.084 119.688 ;
    END
  END b[139]
  PIN b[13]
    DIRECTION OUTPUT ;
    USE SIGNAL ;
    PORT
      LAYER M4 ;
        RECT  0 33.552 0.084 33.576 ;
    END
  END b[13]
  PIN b[140]
    DIRECTION OUTPUT ;
    USE SIGNAL ;
    PORT
      LAYER M4 ;
        RECT  0 119.808 0.084 119.832 ;
    END
  END b[140]
  PIN b[141]
    DIRECTION OUTPUT ;
    USE SIGNAL ;
    PORT
      LAYER M4 ;
        RECT  0 119.952 0.084 119.976 ;
    END
  END b[141]
  PIN b[142]
    DIRECTION OUTPUT ;
    USE SIGNAL ;
    PORT
      LAYER M4 ;
        RECT  0 120.096 0.084 120.12 ;
    END
  END b[142]
  PIN b[143]
    DIRECTION OUTPUT ;
    USE SIGNAL ;
    PORT
      LAYER M4 ;
        RECT  0 120.24 0.084 120.264 ;
    END
  END b[143]
  PIN b[144]
    DIRECTION OUTPUT ;
    USE SIGNAL ;
    PORT
      LAYER M4 ;
        RECT  0 120.384 0.084 120.408 ;
    END
  END b[144]
  PIN b[145]
    DIRECTION OUTPUT ;
    USE SIGNAL ;
    PORT
      LAYER M4 ;
        RECT  0 120.528 0.084 120.552 ;
    END
  END b[145]
  PIN b[146]
    DIRECTION OUTPUT ;
    USE SIGNAL ;
    PORT
      LAYER M4 ;
        RECT  0 120.672 0.084 120.696 ;
    END
  END b[146]
  PIN b[147]
    DIRECTION OUTPUT ;
    USE SIGNAL ;
    PORT
      LAYER M4 ;
        RECT  0 120.816 0.084 120.84 ;
    END
  END b[147]
  PIN b[148]
    DIRECTION OUTPUT ;
    USE SIGNAL ;
    PORT
      LAYER M4 ;
        RECT  0 120.96 0.084 120.984 ;
    END
  END b[148]
  PIN b[149]
    DIRECTION OUTPUT ;
    USE SIGNAL ;
    PORT
      LAYER M4 ;
        RECT  0 121.104 0.084 121.128 ;
    END
  END b[149]
  PIN b[14]
    DIRECTION OUTPUT ;
    USE SIGNAL ;
    PORT
      LAYER M4 ;
        RECT  0 33.696 0.084 33.72 ;
    END
  END b[14]
  PIN b[150]
    DIRECTION OUTPUT ;
    USE SIGNAL ;
    PORT
      LAYER M4 ;
        RECT  0 121.248 0.084 121.272 ;
    END
  END b[150]
  PIN b[151]
    DIRECTION OUTPUT ;
    USE SIGNAL ;
    PORT
      LAYER M4 ;
        RECT  0 121.392 0.084 121.416 ;
    END
  END b[151]
  PIN b[152]
    DIRECTION OUTPUT ;
    USE SIGNAL ;
    PORT
      LAYER M4 ;
        RECT  0 121.536 0.084 121.56 ;
    END
  END b[152]
  PIN b[153]
    DIRECTION OUTPUT ;
    USE SIGNAL ;
    PORT
      LAYER M4 ;
        RECT  0 121.68 0.084 121.704 ;
    END
  END b[153]
  PIN b[154]
    DIRECTION OUTPUT ;
    USE SIGNAL ;
    PORT
      LAYER M4 ;
        RECT  0 121.824 0.084 121.848 ;
    END
  END b[154]
  PIN b[155]
    DIRECTION OUTPUT ;
    USE SIGNAL ;
    PORT
      LAYER M4 ;
        RECT  0 121.968 0.084 121.992 ;
    END
  END b[155]
  PIN b[156]
    DIRECTION OUTPUT ;
    USE SIGNAL ;
    PORT
      LAYER M4 ;
        RECT  0 122.112 0.084 122.136 ;
    END
  END b[156]
  PIN b[157]
    DIRECTION OUTPUT ;
    USE SIGNAL ;
    PORT
      LAYER M4 ;
        RECT  0 122.256 0.084 122.28 ;
    END
  END b[157]
  PIN b[158]
    DIRECTION OUTPUT ;
    USE SIGNAL ;
    PORT
      LAYER M4 ;
        RECT  0 122.4 0.084 122.424 ;
    END
  END b[158]
  PIN b[159]
    DIRECTION OUTPUT ;
    USE SIGNAL ;
    PORT
      LAYER M4 ;
        RECT  0 122.544 0.084 122.568 ;
    END
  END b[159]
  PIN b[15]
    DIRECTION OUTPUT ;
    USE SIGNAL ;
    PORT
      LAYER M4 ;
        RECT  0 33.84 0.084 33.864 ;
    END
  END b[15]
  PIN b[160]
    DIRECTION OUTPUT ;
    USE SIGNAL ;
    PORT
      LAYER M4 ;
        RECT  0 129.888 0.084 129.912 ;
    END
  END b[160]
  PIN b[161]
    DIRECTION OUTPUT ;
    USE SIGNAL ;
    PORT
      LAYER M4 ;
        RECT  0 130.032 0.084 130.056 ;
    END
  END b[161]
  PIN b[162]
    DIRECTION OUTPUT ;
    USE SIGNAL ;
    PORT
      LAYER M4 ;
        RECT  0 130.176 0.084 130.2 ;
    END
  END b[162]
  PIN b[163]
    DIRECTION OUTPUT ;
    USE SIGNAL ;
    PORT
      LAYER M4 ;
        RECT  0 130.32 0.084 130.344 ;
    END
  END b[163]
  PIN b[164]
    DIRECTION OUTPUT ;
    USE SIGNAL ;
    PORT
      LAYER M4 ;
        RECT  0 130.464 0.084 130.488 ;
    END
  END b[164]
  PIN b[165]
    DIRECTION OUTPUT ;
    USE SIGNAL ;
    PORT
      LAYER M4 ;
        RECT  0 130.608 0.084 130.632 ;
    END
  END b[165]
  PIN b[166]
    DIRECTION OUTPUT ;
    USE SIGNAL ;
    PORT
      LAYER M4 ;
        RECT  0 130.752 0.084 130.776 ;
    END
  END b[166]
  PIN b[167]
    DIRECTION OUTPUT ;
    USE SIGNAL ;
    PORT
      LAYER M4 ;
        RECT  0 130.896 0.084 130.92 ;
    END
  END b[167]
  PIN b[168]
    DIRECTION OUTPUT ;
    USE SIGNAL ;
    PORT
      LAYER M4 ;
        RECT  0 131.04 0.084 131.064 ;
    END
  END b[168]
  PIN b[169]
    DIRECTION OUTPUT ;
    USE SIGNAL ;
    PORT
      LAYER M4 ;
        RECT  0 131.184 0.084 131.208 ;
    END
  END b[169]
  PIN b[16]
    DIRECTION OUTPUT ;
    USE SIGNAL ;
    PORT
      LAYER M4 ;
        RECT  0 33.984 0.084 34.008 ;
    END
  END b[16]
  PIN b[170]
    DIRECTION OUTPUT ;
    USE SIGNAL ;
    PORT
      LAYER M4 ;
        RECT  0 131.328 0.084 131.352 ;
    END
  END b[170]
  PIN b[171]
    DIRECTION OUTPUT ;
    USE SIGNAL ;
    PORT
      LAYER M4 ;
        RECT  0 131.472 0.084 131.496 ;
    END
  END b[171]
  PIN b[172]
    DIRECTION OUTPUT ;
    USE SIGNAL ;
    PORT
      LAYER M4 ;
        RECT  0 131.616 0.084 131.64 ;
    END
  END b[172]
  PIN b[173]
    DIRECTION OUTPUT ;
    USE SIGNAL ;
    PORT
      LAYER M4 ;
        RECT  0 131.76 0.084 131.784 ;
    END
  END b[173]
  PIN b[17]
    DIRECTION OUTPUT ;
    USE SIGNAL ;
    PORT
      LAYER M4 ;
        RECT  0 34.128 0.084 34.152 ;
    END
  END b[17]
  PIN b[18]
    DIRECTION OUTPUT ;
    USE SIGNAL ;
    PORT
      LAYER M4 ;
        RECT  0 34.272 0.084 34.296 ;
    END
  END b[18]
  PIN b[19]
    DIRECTION OUTPUT ;
    USE SIGNAL ;
    PORT
      LAYER M4 ;
        RECT  0 34.416 0.084 34.44 ;
    END
  END b[19]
  PIN b[1]
    DIRECTION OUTPUT ;
    USE SIGNAL ;
    PORT
      LAYER M4 ;
        RECT  0 31.824 0.084 31.848 ;
    END
  END b[1]
  PIN b[20]
    DIRECTION OUTPUT ;
    USE SIGNAL ;
    PORT
      LAYER M4 ;
        RECT  0 34.56 0.084 34.584 ;
    END
  END b[20]
  PIN b[21]
    DIRECTION OUTPUT ;
    USE SIGNAL ;
    PORT
      LAYER M4 ;
        RECT  0 34.704 0.084 34.728 ;
    END
  END b[21]
  PIN b[22]
    DIRECTION OUTPUT ;
    USE SIGNAL ;
    PORT
      LAYER M4 ;
        RECT  0 34.848 0.084 34.872 ;
    END
  END b[22]
  PIN b[23]
    DIRECTION OUTPUT ;
    USE SIGNAL ;
    PORT
      LAYER M4 ;
        RECT  0 34.992 0.084 35.016 ;
    END
  END b[23]
  PIN b[24]
    DIRECTION OUTPUT ;
    USE SIGNAL ;
    PORT
      LAYER M4 ;
        RECT  0 35.136 0.084 35.16 ;
    END
  END b[24]
  PIN b[25]
    DIRECTION OUTPUT ;
    USE SIGNAL ;
    PORT
      LAYER M4 ;
        RECT  0 35.28 0.084 35.304 ;
    END
  END b[25]
  PIN b[26]
    DIRECTION OUTPUT ;
    USE SIGNAL ;
    PORT
      LAYER M4 ;
        RECT  0 35.424 0.084 35.448 ;
    END
  END b[26]
  PIN b[27]
    DIRECTION OUTPUT ;
    USE SIGNAL ;
    PORT
      LAYER M4 ;
        RECT  0 35.568 0.084 35.592 ;
    END
  END b[27]
  PIN b[28]
    DIRECTION OUTPUT ;
    USE SIGNAL ;
    PORT
      LAYER M4 ;
        RECT  0 35.712 0.084 35.736 ;
    END
  END b[28]
  PIN b[29]
    DIRECTION OUTPUT ;
    USE SIGNAL ;
    PORT
      LAYER M4 ;
        RECT  0 35.856 0.084 35.88 ;
    END
  END b[29]
  PIN b[2]
    DIRECTION OUTPUT ;
    USE SIGNAL ;
    PORT
      LAYER M4 ;
        RECT  0 31.968 0.084 31.992 ;
    END
  END b[2]
  PIN b[30]
    DIRECTION OUTPUT ;
    USE SIGNAL ;
    PORT
      LAYER M4 ;
        RECT  0 36 0.084 36.024 ;
    END
  END b[30]
  PIN b[31]
    DIRECTION OUTPUT ;
    USE SIGNAL ;
    PORT
      LAYER M4 ;
        RECT  0 36.144 0.084 36.168 ;
    END
  END b[31]
  PIN b[32]
    DIRECTION OUTPUT ;
    USE SIGNAL ;
    PORT
      LAYER M4 ;
        RECT  0 40.896 0.084 40.92 ;
    END
  END b[32]
  PIN b[33]
    DIRECTION OUTPUT ;
    USE SIGNAL ;
    PORT
      LAYER M4 ;
        RECT  0 41.04 0.084 41.064 ;
    END
  END b[33]
  PIN b[34]
    DIRECTION OUTPUT ;
    USE SIGNAL ;
    PORT
      LAYER M4 ;
        RECT  0 41.184 0.084 41.208 ;
    END
  END b[34]
  PIN b[35]
    DIRECTION OUTPUT ;
    USE SIGNAL ;
    PORT
      LAYER M4 ;
        RECT  0 41.328 0.084 41.352 ;
    END
  END b[35]
  PIN b[36]
    DIRECTION OUTPUT ;
    USE SIGNAL ;
    PORT
      LAYER M4 ;
        RECT  0 41.472 0.084 41.496 ;
    END
  END b[36]
  PIN b[37]
    DIRECTION OUTPUT ;
    USE SIGNAL ;
    PORT
      LAYER M4 ;
        RECT  0 41.616 0.084 41.64 ;
    END
  END b[37]
  PIN b[38]
    DIRECTION OUTPUT ;
    USE SIGNAL ;
    PORT
      LAYER M4 ;
        RECT  0 41.76 0.084 41.784 ;
    END
  END b[38]
  PIN b[39]
    DIRECTION OUTPUT ;
    USE SIGNAL ;
    PORT
      LAYER M4 ;
        RECT  0 41.904 0.084 41.928 ;
    END
  END b[39]
  PIN b[3]
    DIRECTION OUTPUT ;
    USE SIGNAL ;
    PORT
      LAYER M4 ;
        RECT  0 32.112 0.084 32.136 ;
    END
  END b[3]
  PIN b[40]
    DIRECTION OUTPUT ;
    USE SIGNAL ;
    PORT
      LAYER M4 ;
        RECT  0 42.048 0.084 42.072 ;
    END
  END b[40]
  PIN b[41]
    DIRECTION OUTPUT ;
    USE SIGNAL ;
    PORT
      LAYER M4 ;
        RECT  0 42.192 0.084 42.216 ;
    END
  END b[41]
  PIN b[42]
    DIRECTION OUTPUT ;
    USE SIGNAL ;
    PORT
      LAYER M4 ;
        RECT  0 42.336 0.084 42.36 ;
    END
  END b[42]
  PIN b[43]
    DIRECTION OUTPUT ;
    USE SIGNAL ;
    PORT
      LAYER M4 ;
        RECT  0 42.48 0.084 42.504 ;
    END
  END b[43]
  PIN b[44]
    DIRECTION OUTPUT ;
    USE SIGNAL ;
    PORT
      LAYER M4 ;
        RECT  0 42.624 0.084 42.648 ;
    END
  END b[44]
  PIN b[45]
    DIRECTION OUTPUT ;
    USE SIGNAL ;
    PORT
      LAYER M4 ;
        RECT  0 42.768 0.084 42.792 ;
    END
  END b[45]
  PIN b[46]
    DIRECTION OUTPUT ;
    USE SIGNAL ;
    PORT
      LAYER M4 ;
        RECT  0 42.912 0.084 42.936 ;
    END
  END b[46]
  PIN b[47]
    DIRECTION OUTPUT ;
    USE SIGNAL ;
    PORT
      LAYER M4 ;
        RECT  0 43.056 0.084 43.08 ;
    END
  END b[47]
  PIN b[48]
    DIRECTION OUTPUT ;
    USE SIGNAL ;
    PORT
      LAYER M4 ;
        RECT  0 43.2 0.084 43.224 ;
    END
  END b[48]
  PIN b[49]
    DIRECTION OUTPUT ;
    USE SIGNAL ;
    PORT
      LAYER M4 ;
        RECT  0 43.344 0.084 43.368 ;
    END
  END b[49]
  PIN b[4]
    DIRECTION OUTPUT ;
    USE SIGNAL ;
    PORT
      LAYER M4 ;
        RECT  0 32.256 0.084 32.28 ;
    END
  END b[4]
  PIN b[50]
    DIRECTION OUTPUT ;
    USE SIGNAL ;
    PORT
      LAYER M4 ;
        RECT  0 43.488 0.084 43.512 ;
    END
  END b[50]
  PIN b[51]
    DIRECTION OUTPUT ;
    USE SIGNAL ;
    PORT
      LAYER M4 ;
        RECT  0 43.632 0.084 43.656 ;
    END
  END b[51]
  PIN b[52]
    DIRECTION OUTPUT ;
    USE SIGNAL ;
    PORT
      LAYER M4 ;
        RECT  0 43.776 0.084 43.8 ;
    END
  END b[52]
  PIN b[53]
    DIRECTION OUTPUT ;
    USE SIGNAL ;
    PORT
      LAYER M4 ;
        RECT  0 43.92 0.084 43.944 ;
    END
  END b[53]
  PIN b[54]
    DIRECTION OUTPUT ;
    USE SIGNAL ;
    PORT
      LAYER M4 ;
        RECT  0 44.064 0.084 44.088 ;
    END
  END b[54]
  PIN b[55]
    DIRECTION OUTPUT ;
    USE SIGNAL ;
    PORT
      LAYER M4 ;
        RECT  0 44.208 0.084 44.232 ;
    END
  END b[55]
  PIN b[56]
    DIRECTION OUTPUT ;
    USE SIGNAL ;
    PORT
      LAYER M4 ;
        RECT  0 44.352 0.084 44.376 ;
    END
  END b[56]
  PIN b[57]
    DIRECTION OUTPUT ;
    USE SIGNAL ;
    PORT
      LAYER M4 ;
        RECT  0 44.496 0.084 44.52 ;
    END
  END b[57]
  PIN b[58]
    DIRECTION OUTPUT ;
    USE SIGNAL ;
    PORT
      LAYER M4 ;
        RECT  0 44.64 0.084 44.664 ;
    END
  END b[58]
  PIN b[59]
    DIRECTION OUTPUT ;
    USE SIGNAL ;
    PORT
      LAYER M4 ;
        RECT  0 44.784 0.084 44.808 ;
    END
  END b[59]
  PIN b[5]
    DIRECTION OUTPUT ;
    USE SIGNAL ;
    PORT
      LAYER M4 ;
        RECT  0 32.4 0.084 32.424 ;
    END
  END b[5]
  PIN b[60]
    DIRECTION OUTPUT ;
    USE SIGNAL ;
    PORT
      LAYER M4 ;
        RECT  0 44.928 0.084 44.952 ;
    END
  END b[60]
  PIN b[61]
    DIRECTION OUTPUT ;
    USE SIGNAL ;
    PORT
      LAYER M4 ;
        RECT  0 45.072 0.084 45.096 ;
    END
  END b[61]
  PIN b[62]
    DIRECTION OUTPUT ;
    USE SIGNAL ;
    PORT
      LAYER M4 ;
        RECT  0 45.216 0.084 45.24 ;
    END
  END b[62]
  PIN b[63]
    DIRECTION OUTPUT ;
    USE SIGNAL ;
    PORT
      LAYER M4 ;
        RECT  0 45.36 0.084 45.384 ;
    END
  END b[63]
  PIN b[64]
    DIRECTION OUTPUT ;
    USE SIGNAL ;
    PORT
      LAYER M4 ;
        RECT  0 74.304 0.084 74.328 ;
    END
  END b[64]
  PIN b[65]
    DIRECTION OUTPUT ;
    USE SIGNAL ;
    PORT
      LAYER M4 ;
        RECT  0 74.448 0.084 74.472 ;
    END
  END b[65]
  PIN b[66]
    DIRECTION OUTPUT ;
    USE SIGNAL ;
    PORT
      LAYER M4 ;
        RECT  0 74.592 0.084 74.616 ;
    END
  END b[66]
  PIN b[67]
    DIRECTION OUTPUT ;
    USE SIGNAL ;
    PORT
      LAYER M4 ;
        RECT  0 74.736 0.084 74.76 ;
    END
  END b[67]
  PIN b[68]
    DIRECTION OUTPUT ;
    USE SIGNAL ;
    PORT
      LAYER M4 ;
        RECT  0 74.88 0.084 74.904 ;
    END
  END b[68]
  PIN b[69]
    DIRECTION OUTPUT ;
    USE SIGNAL ;
    PORT
      LAYER M4 ;
        RECT  0 75.024 0.084 75.048 ;
    END
  END b[69]
  PIN b[6]
    DIRECTION OUTPUT ;
    USE SIGNAL ;
    PORT
      LAYER M4 ;
        RECT  0 32.544 0.084 32.568 ;
    END
  END b[6]
  PIN b[70]
    DIRECTION OUTPUT ;
    USE SIGNAL ;
    PORT
      LAYER M4 ;
        RECT  0 75.168 0.084 75.192 ;
    END
  END b[70]
  PIN b[71]
    DIRECTION OUTPUT ;
    USE SIGNAL ;
    PORT
      LAYER M4 ;
        RECT  0 75.312 0.084 75.336 ;
    END
  END b[71]
  PIN b[72]
    DIRECTION OUTPUT ;
    USE SIGNAL ;
    PORT
      LAYER M4 ;
        RECT  0 75.456 0.084 75.48 ;
    END
  END b[72]
  PIN b[73]
    DIRECTION OUTPUT ;
    USE SIGNAL ;
    PORT
      LAYER M4 ;
        RECT  0 75.6 0.084 75.624 ;
    END
  END b[73]
  PIN b[74]
    DIRECTION OUTPUT ;
    USE SIGNAL ;
    PORT
      LAYER M4 ;
        RECT  0 75.744 0.084 75.768 ;
    END
  END b[74]
  PIN b[75]
    DIRECTION OUTPUT ;
    USE SIGNAL ;
    PORT
      LAYER M4 ;
        RECT  0 75.888 0.084 75.912 ;
    END
  END b[75]
  PIN b[76]
    DIRECTION OUTPUT ;
    USE SIGNAL ;
    PORT
      LAYER M4 ;
        RECT  0 76.032 0.084 76.056 ;
    END
  END b[76]
  PIN b[77]
    DIRECTION OUTPUT ;
    USE SIGNAL ;
    PORT
      LAYER M4 ;
        RECT  0 76.176 0.084 76.2 ;
    END
  END b[77]
  PIN b[78]
    DIRECTION OUTPUT ;
    USE SIGNAL ;
    PORT
      LAYER M4 ;
        RECT  0 76.32 0.084 76.344 ;
    END
  END b[78]
  PIN b[79]
    DIRECTION OUTPUT ;
    USE SIGNAL ;
    PORT
      LAYER M4 ;
        RECT  0 76.464 0.084 76.488 ;
    END
  END b[79]
  PIN b[7]
    DIRECTION OUTPUT ;
    USE SIGNAL ;
    PORT
      LAYER M4 ;
        RECT  0 32.688 0.084 32.712 ;
    END
  END b[7]
  PIN b[80]
    DIRECTION OUTPUT ;
    USE SIGNAL ;
    PORT
      LAYER M4 ;
        RECT  0 76.608 0.084 76.632 ;
    END
  END b[80]
  PIN b[81]
    DIRECTION OUTPUT ;
    USE SIGNAL ;
    PORT
      LAYER M4 ;
        RECT  0 76.752 0.084 76.776 ;
    END
  END b[81]
  PIN b[82]
    DIRECTION OUTPUT ;
    USE SIGNAL ;
    PORT
      LAYER M4 ;
        RECT  0 76.896 0.084 76.92 ;
    END
  END b[82]
  PIN b[83]
    DIRECTION OUTPUT ;
    USE SIGNAL ;
    PORT
      LAYER M4 ;
        RECT  0 77.04 0.084 77.064 ;
    END
  END b[83]
  PIN b[84]
    DIRECTION OUTPUT ;
    USE SIGNAL ;
    PORT
      LAYER M4 ;
        RECT  0 77.184 0.084 77.208 ;
    END
  END b[84]
  PIN b[85]
    DIRECTION OUTPUT ;
    USE SIGNAL ;
    PORT
      LAYER M4 ;
        RECT  0 77.328 0.084 77.352 ;
    END
  END b[85]
  PIN b[86]
    DIRECTION OUTPUT ;
    USE SIGNAL ;
    PORT
      LAYER M4 ;
        RECT  0 77.472 0.084 77.496 ;
    END
  END b[86]
  PIN b[87]
    DIRECTION OUTPUT ;
    USE SIGNAL ;
    PORT
      LAYER M4 ;
        RECT  0 77.616 0.084 77.64 ;
    END
  END b[87]
  PIN b[88]
    DIRECTION OUTPUT ;
    USE SIGNAL ;
    PORT
      LAYER M4 ;
        RECT  0 77.76 0.084 77.784 ;
    END
  END b[88]
  PIN b[89]
    DIRECTION OUTPUT ;
    USE SIGNAL ;
    PORT
      LAYER M4 ;
        RECT  0 77.904 0.084 77.928 ;
    END
  END b[89]
  PIN b[8]
    DIRECTION OUTPUT ;
    USE SIGNAL ;
    PORT
      LAYER M4 ;
        RECT  0 32.832 0.084 32.856 ;
    END
  END b[8]
  PIN b[90]
    DIRECTION OUTPUT ;
    USE SIGNAL ;
    PORT
      LAYER M4 ;
        RECT  0 78.048 0.084 78.072 ;
    END
  END b[90]
  PIN b[91]
    DIRECTION OUTPUT ;
    USE SIGNAL ;
    PORT
      LAYER M4 ;
        RECT  0 78.192 0.084 78.216 ;
    END
  END b[91]
  PIN b[92]
    DIRECTION OUTPUT ;
    USE SIGNAL ;
    PORT
      LAYER M4 ;
        RECT  0 78.336 0.084 78.36 ;
    END
  END b[92]
  PIN b[93]
    DIRECTION OUTPUT ;
    USE SIGNAL ;
    PORT
      LAYER M4 ;
        RECT  0 78.48 0.084 78.504 ;
    END
  END b[93]
  PIN b[94]
    DIRECTION OUTPUT ;
    USE SIGNAL ;
    PORT
      LAYER M4 ;
        RECT  0 78.624 0.084 78.648 ;
    END
  END b[94]
  PIN b[95]
    DIRECTION OUTPUT ;
    USE SIGNAL ;
    PORT
      LAYER M4 ;
        RECT  0 78.768 0.084 78.792 ;
    END
  END b[95]
  PIN b[96]
    DIRECTION OUTPUT ;
    USE SIGNAL ;
    PORT
      LAYER M4 ;
        RECT  0 84.672 0.084 84.696 ;
    END
  END b[96]
  PIN b[97]
    DIRECTION OUTPUT ;
    USE SIGNAL ;
    PORT
      LAYER M4 ;
        RECT  0 84.816 0.084 84.84 ;
    END
  END b[97]
  PIN b[98]
    DIRECTION OUTPUT ;
    USE SIGNAL ;
    PORT
      LAYER M4 ;
        RECT  0 84.96 0.084 84.984 ;
    END
  END b[98]
  PIN b[99]
    DIRECTION OUTPUT ;
    USE SIGNAL ;
    PORT
      LAYER M4 ;
        RECT  0 85.104 0.084 85.128 ;
    END
  END b[99]
  PIN b[9]
    DIRECTION OUTPUT ;
    USE SIGNAL ;
    PORT
      LAYER M4 ;
        RECT  0 32.976 0.084 33 ;
    END
  END b[9]
  PIN ck
    DIRECTION INPUT ;
    USE SIGNAL ;
    PORT
      LAYER M3 ;
        RECT  37.908 170.603 37.926 170.64 ;
    END
  END ck
  PIN ck_s
    DIRECTION INPUT ;
    USE SIGNAL ;
    PORT
      LAYER M3 ;
        RECT  38.016 170.603 38.034 170.64 ;
    END
  END ck_s
  PIN en
    DIRECTION INPUT ;
    USE SIGNAL ;
    PORT
      LAYER M3 ;
        RECT  38.124 170.603 38.142 170.64 ;
    END
  END en
  PIN fault
    DIRECTION OUTPUT ;
    USE SIGNAL ;
    PORT
      LAYER M3 ;
        RECT  38.232 170.603 38.25 170.64 ;
    END
  END fault
  PIN k0
    DIRECTION INPUT ;
    USE SIGNAL ;
    PORT
      LAYER M3 ;
        RECT  38.34 170.603 38.358 170.64 ;
    END
  END k0
  PIN k1
    DIRECTION INPUT ;
    USE SIGNAL ;
    PORT
      LAYER M3 ;
        RECT  38.448 170.603 38.466 170.64 ;
    END
  END k1
  PIN k2
    DIRECTION INPUT ;
    USE SIGNAL ;
    PORT
      LAYER M3 ;
        RECT  38.556 170.603 38.574 170.64 ;
    END
  END k2
  PIN k3
    DIRECTION INPUT ;
    USE SIGNAL ;
    PORT
      LAYER M3 ;
        RECT  38.664 170.603 38.682 170.64 ;
    END
  END k3
  PIN rs
    DIRECTION INPUT ;
    USE SIGNAL ;
    PORT
      LAYER M3 ;
        RECT  38.772 170.603 38.79 170.64 ;
    END
  END rs
  PIN tie_hi
    DIRECTION OUTPUT ;
    USE SIGNAL ;
    PORT
      LAYER M3 ;
        RECT  38.88 170.603 38.898 170.64 ;
    END
  END tie_hi
  PIN tie_lo
    DIRECTION OUTPUT ;
    USE SIGNAL ;
    PORT
      LAYER M3 ;
        RECT  38.988 170.603 39.006 170.64 ;
    END
  END tie_lo
  PIN VDD
    DIRECTION INOUT ;
    USE POWER ;
    PORT
      LAYER M5 ;
        RECT  94.392 2.151 94.512 168.489 ;
        RECT  91.692 2.151 91.812 168.489 ;
        RECT  88.992 2.151 89.112 168.489 ;
        RECT  86.292 2.151 86.412 168.489 ;
        RECT  83.592 2.151 83.712 168.489 ;
        RECT  80.892 2.151 81.012 168.489 ;
        RECT  78.192 2.151 78.312 168.489 ;
        RECT  75.492 2.151 75.612 168.489 ;
        RECT  72.792 2.151 72.912 168.489 ;
        RECT  70.092 2.151 70.212 168.489 ;
        RECT  67.392 2.151 67.512 168.489 ;
        RECT  64.692 2.151 64.812 168.489 ;
        RECT  61.992 2.151 62.112 168.489 ;
        RECT  59.292 2.151 59.412 168.489 ;
        RECT  56.592 2.151 56.712 168.489 ;
        RECT  53.892 2.151 54.012 168.489 ;
        RECT  51.192 2.151 51.312 168.489 ;
        RECT  48.492 2.151 48.612 168.489 ;
        RECT  45.792 2.151 45.912 168.489 ;
        RECT  43.092 2.151 43.212 168.489 ;
        RECT  40.392 2.151 40.512 168.489 ;
        RECT  37.692 2.151 37.812 168.489 ;
        RECT  34.992 2.151 35.112 168.489 ;
        RECT  32.292 2.151 32.412 168.489 ;
        RECT  29.592 2.151 29.712 168.489 ;
        RECT  26.892 2.151 27.012 168.489 ;
        RECT  24.192 2.151 24.312 168.489 ;
        RECT  21.492 2.151 21.612 168.489 ;
        RECT  18.792 2.151 18.912 168.489 ;
        RECT  16.092 2.151 16.212 168.489 ;
        RECT  13.392 2.151 13.512 168.489 ;
        RECT  10.692 2.151 10.812 168.489 ;
        RECT  7.992 2.151 8.112 168.489 ;
        RECT  5.292 2.151 5.412 168.489 ;
        RECT  2.592 2.151 2.712 168.489 ;
    END
  END VDD
  PIN VSS
    DIRECTION INOUT ;
    USE GROUND ;
    PORT
      LAYER M5 ;
        RECT  94.2 2.137 94.32 168.503 ;
        RECT  91.5 2.137 91.62 168.503 ;
        RECT  88.8 2.137 88.92 168.503 ;
        RECT  86.1 2.137 86.22 168.503 ;
        RECT  83.4 2.137 83.52 168.503 ;
        RECT  80.7 2.137 80.82 168.503 ;
        RECT  78 2.137 78.12 168.503 ;
        RECT  75.3 2.137 75.42 168.503 ;
        RECT  72.6 2.137 72.72 168.503 ;
        RECT  69.9 2.137 70.02 168.503 ;
        RECT  67.2 2.137 67.32 168.503 ;
        RECT  64.5 2.137 64.62 168.503 ;
        RECT  61.8 2.137 61.92 168.503 ;
        RECT  59.1 2.137 59.22 168.503 ;
        RECT  56.4 2.137 56.52 168.503 ;
        RECT  53.7 2.137 53.82 168.503 ;
        RECT  51 2.137 51.12 168.503 ;
        RECT  48.3 2.137 48.42 168.503 ;
        RECT  45.6 2.137 45.72 168.503 ;
        RECT  42.9 2.137 43.02 168.503 ;
        RECT  40.2 2.137 40.32 168.503 ;
        RECT  37.5 2.137 37.62 168.503 ;
        RECT  34.8 2.137 34.92 168.503 ;
        RECT  32.1 2.137 32.22 168.503 ;
        RECT  29.4 2.137 29.52 168.503 ;
        RECT  26.7 2.137 26.82 168.503 ;
        RECT  24 2.137 24.12 168.503 ;
        RECT  21.3 2.137 21.42 168.503 ;
        RECT  18.6 2.137 18.72 168.503 ;
        RECT  15.9 2.137 16.02 168.503 ;
        RECT  13.2 2.137 13.32 168.503 ;
        RECT  10.5 2.137 10.62 168.503 ;
        RECT  7.8 2.137 7.92 168.503 ;
        RECT  5.1 2.137 5.22 168.503 ;
        RECT  2.4 2.137 2.52 168.503 ;
    END
  END VSS
  # OT_OBS_CLOSED layer=M5 d_um=1.536 added=68
  OBS
    LAYER RVTN ;
     RECT  2.16 2.16 96.12 2.295 ;
     RECT  2.16 2.565 96.12 2.835 ;
     RECT  2.16 3.105 96.12 3.375 ;
     RECT  2.16 3.645 96.12 3.915 ;
     RECT  2.16 4.185 96.12 4.455 ;
     RECT  2.16 4.725 96.12 4.995 ;
     RECT  2.16 5.265 96.12 5.535 ;
     RECT  2.16 5.805 96.12 6.075 ;
     RECT  2.16 6.345 96.12 6.615 ;
     RECT  2.16 6.885 96.12 7.155 ;
     RECT  2.16 7.425 96.12 7.695 ;
     RECT  2.16 7.965 96.12 8.235 ;
     RECT  2.16 8.505 96.12 8.775 ;
     RECT  2.16 9.045 96.12 9.315 ;
     RECT  2.16 9.585 96.12 9.855 ;
     RECT  2.16 10.125 96.12 10.395 ;
     RECT  2.16 10.665 96.12 10.935 ;
     RECT  2.16 11.205 96.12 11.475 ;
     RECT  2.16 11.745 96.12 12.015 ;
     RECT  2.16 12.285 96.12 12.555 ;
     RECT  2.16 12.825 96.12 13.095 ;
     RECT  2.16 13.365 96.12 13.635 ;
     RECT  2.16 13.905 96.12 14.175 ;
     RECT  2.16 14.445 96.12 14.715 ;
     RECT  2.16 14.985 96.12 15.255 ;
     RECT  2.16 15.525 96.12 15.795 ;
     RECT  2.16 16.065 96.12 16.335 ;
     RECT  2.16 16.605 96.12 16.875 ;
     RECT  2.16 17.145 96.12 17.415 ;
     RECT  2.16 17.685 96.12 17.955 ;
     RECT  2.16 18.225 96.12 18.495 ;
     RECT  2.16 18.765 96.12 19.035 ;
     RECT  2.16 19.305 96.12 19.575 ;
     RECT  2.16 19.845 96.12 20.115 ;
     RECT  2.16 20.385 96.12 20.655 ;
     RECT  2.16 20.925 96.12 21.195 ;
     RECT  2.16 21.465 96.12 21.735 ;
     RECT  2.16 22.005 96.12 22.275 ;
     RECT  2.16 22.545 96.12 22.815 ;
     RECT  2.16 23.085 96.12 23.355 ;
     RECT  2.16 23.625 96.12 23.895 ;
     RECT  2.16 24.165 96.12 24.435 ;
     RECT  2.16 24.705 96.12 24.975 ;
     RECT  2.16 25.245 96.12 25.515 ;
     RECT  2.16 25.785 96.12 26.055 ;
     RECT  2.16 26.325 96.12 26.595 ;
     RECT  2.16 26.865 96.12 27.135 ;
     RECT  2.16 27.405 96.12 27.675 ;
     RECT  2.16 27.945 96.12 28.215 ;
     RECT  2.16 28.485 96.12 28.755 ;
     RECT  2.16 29.025 96.12 29.295 ;
     RECT  2.16 29.565 96.12 29.835 ;
     RECT  2.16 30.105 96.12 30.375 ;
     RECT  2.16 30.645 96.12 30.915 ;
     RECT  2.16 31.185 96.12 31.455 ;
     RECT  2.16 31.725 96.12 31.995 ;
     RECT  2.16 32.265 96.12 32.535 ;
     RECT  2.16 32.805 96.12 33.075 ;
     RECT  2.16 33.345 96.12 33.615 ;
     RECT  2.16 33.885 96.12 34.155 ;
     RECT  2.16 34.425 96.12 34.695 ;
     RECT  2.16 34.965 96.12 35.235 ;
     RECT  2.16 35.505 96.12 35.775 ;
     RECT  2.16 36.045 96.12 36.315 ;
     RECT  2.16 36.585 96.12 36.855 ;
     RECT  2.16 37.125 96.12 37.395 ;
     RECT  2.16 37.665 96.12 37.935 ;
     RECT  2.16 38.205 96.12 38.475 ;
     RECT  2.16 38.745 96.12 39.015 ;
     RECT  2.16 39.285 96.12 39.555 ;
     RECT  2.16 39.825 96.12 40.095 ;
     RECT  2.16 40.365 96.12 40.635 ;
     RECT  2.16 40.905 96.12 41.04 ;
     RECT  2.16 41.04 41.148 41.175 ;
     RECT  77.22 41.04 96.12 41.175 ;
     RECT  2.16 41.445 41.148 41.715 ;
     RECT  77.22 41.445 96.12 41.715 ;
     RECT  2.16 41.985 41.148 42.255 ;
     RECT  77.22 41.985 96.12 42.255 ;
     RECT  2.16 42.525 41.148 42.795 ;
     RECT  77.22 42.525 96.12 42.795 ;
     RECT  2.16 43.065 41.148 43.335 ;
     RECT  77.22 43.065 96.12 43.335 ;
     RECT  2.16 43.605 41.148 43.875 ;
     RECT  77.22 43.605 96.12 43.875 ;
     RECT  2.16 44.145 41.148 44.415 ;
     RECT  77.22 44.145 96.12 44.415 ;
     RECT  2.16 44.685 41.148 44.955 ;
     RECT  77.22 44.685 96.12 44.955 ;
     RECT  2.16 45.225 41.148 45.495 ;
     RECT  77.22 45.225 96.12 45.495 ;
     RECT  2.16 45.765 41.148 46.035 ;
     RECT  77.22 45.765 96.12 46.035 ;
     RECT  2.16 46.305 41.148 46.575 ;
     RECT  77.22 46.305 96.12 46.575 ;
     RECT  2.16 46.845 41.148 47.115 ;
     RECT  77.22 46.845 96.12 47.115 ;
     RECT  2.16 47.385 41.148 47.655 ;
     RECT  77.22 47.385 96.12 47.655 ;
     RECT  2.16 47.925 41.148 48.195 ;
     RECT  77.22 47.925 96.12 48.195 ;
     RECT  2.16 48.465 41.148 48.735 ;
     RECT  77.22 48.465 96.12 48.735 ;
     RECT  2.16 49.005 41.148 49.275 ;
     RECT  77.22 49.005 96.12 49.275 ;
     RECT  2.16 49.545 41.148 49.815 ;
     RECT  77.22 49.545 96.12 49.815 ;
     RECT  2.16 50.085 41.148 50.355 ;
     RECT  77.22 50.085 96.12 50.355 ;
     RECT  2.16 50.625 41.148 50.895 ;
     RECT  77.22 50.625 96.12 50.895 ;
     RECT  2.16 51.165 41.148 51.435 ;
     RECT  77.22 51.165 96.12 51.435 ;
     RECT  2.16 51.705 41.148 51.975 ;
     RECT  77.22 51.705 96.12 51.975 ;
     RECT  2.16 52.245 41.148 52.515 ;
     RECT  77.22 52.245 96.12 52.515 ;
     RECT  2.16 52.785 41.148 53.055 ;
     RECT  77.22 52.785 96.12 53.055 ;
     RECT  2.16 53.325 41.148 53.595 ;
     RECT  77.22 53.325 96.12 53.595 ;
     RECT  2.16 53.865 41.148 54.135 ;
     RECT  77.22 53.865 96.12 54.135 ;
     RECT  2.16 54.405 41.148 54.675 ;
     RECT  77.22 54.405 96.12 54.675 ;
     RECT  2.16 54.945 41.148 55.215 ;
     RECT  77.22 54.945 96.12 55.215 ;
     RECT  2.16 55.485 41.148 55.755 ;
     RECT  77.22 55.485 96.12 55.755 ;
     RECT  2.16 56.025 41.148 56.295 ;
     RECT  77.22 56.025 96.12 56.295 ;
     RECT  2.16 56.565 41.148 56.835 ;
     RECT  77.22 56.565 96.12 56.835 ;
     RECT  2.16 57.105 41.148 57.375 ;
     RECT  77.22 57.105 96.12 57.375 ;
     RECT  2.16 57.645 41.148 57.915 ;
     RECT  77.22 57.645 96.12 57.915 ;
     RECT  2.16 58.185 41.148 58.455 ;
     RECT  77.22 58.185 96.12 58.455 ;
     RECT  2.16 58.725 41.148 58.995 ;
     RECT  77.22 58.725 96.12 58.995 ;
     RECT  2.16 59.265 41.148 59.535 ;
     RECT  77.22 59.265 96.12 59.535 ;
     RECT  2.16 59.805 41.148 60.075 ;
     RECT  77.22 59.805 96.12 60.075 ;
     RECT  2.16 60.345 41.148 60.615 ;
     RECT  77.22 60.345 96.12 60.615 ;
     RECT  2.16 60.885 41.148 61.155 ;
     RECT  77.22 60.885 96.12 61.155 ;
     RECT  2.16 61.425 41.148 61.695 ;
     RECT  77.22 61.425 96.12 61.695 ;
     RECT  2.16 61.965 41.148 62.235 ;
     RECT  77.22 61.965 96.12 62.235 ;
     RECT  2.16 62.505 41.148 62.64 ;
     RECT  77.22 62.505 96.12 62.64 ;
     RECT  2.16 62.64 96.12 62.775 ;
     RECT  2.16 63.045 96.12 63.315 ;
     RECT  2.16 63.585 96.12 63.855 ;
     RECT  2.16 64.125 96.12 64.395 ;
     RECT  2.16 64.665 96.12 64.935 ;
     RECT  2.16 65.205 96.12 65.475 ;
     RECT  2.16 65.745 96.12 66.015 ;
     RECT  2.16 66.285 96.12 66.555 ;
     RECT  2.16 66.825 96.12 67.095 ;
     RECT  2.16 67.365 96.12 67.635 ;
     RECT  2.16 67.905 96.12 68.175 ;
     RECT  2.16 68.445 96.12 68.715 ;
     RECT  2.16 68.985 96.12 69.255 ;
     RECT  2.16 69.525 96.12 69.795 ;
     RECT  2.16 70.065 96.12 70.335 ;
     RECT  2.16 70.605 96.12 70.875 ;
     RECT  2.16 71.145 96.12 71.415 ;
     RECT  2.16 71.685 96.12 71.955 ;
     RECT  2.16 72.225 96.12 72.495 ;
     RECT  2.16 72.765 96.12 73.035 ;
     RECT  2.16 73.305 96.12 73.575 ;
     RECT  2.16 73.845 96.12 74.115 ;
     RECT  2.16 74.385 96.12 74.655 ;
     RECT  2.16 74.925 96.12 75.195 ;
     RECT  2.16 75.465 96.12 75.735 ;
     RECT  2.16 76.005 96.12 76.275 ;
     RECT  2.16 76.545 96.12 76.815 ;
     RECT  2.16 77.085 96.12 77.355 ;
     RECT  2.16 77.625 96.12 77.895 ;
     RECT  2.16 78.165 96.12 78.435 ;
     RECT  2.16 78.705 96.12 78.975 ;
     RECT  2.16 79.245 96.12 79.515 ;
     RECT  2.16 79.785 96.12 80.055 ;
     RECT  2.16 80.325 96.12 80.595 ;
     RECT  2.16 80.865 96.12 81.135 ;
     RECT  2.16 81.405 96.12 81.675 ;
     RECT  2.16 81.945 96.12 82.215 ;
     RECT  2.16 82.485 96.12 82.755 ;
     RECT  2.16 83.025 96.12 83.295 ;
     RECT  2.16 83.565 96.12 83.835 ;
     RECT  2.16 84.105 96.12 84.24 ;
     RECT  2.16 84.24 41.148 84.375 ;
     RECT  77.22 84.24 96.12 84.375 ;
     RECT  2.16 84.645 41.148 84.915 ;
     RECT  77.22 84.645 96.12 84.915 ;
     RECT  2.16 85.185 41.148 85.455 ;
     RECT  77.22 85.185 96.12 85.455 ;
     RECT  2.16 85.725 41.148 85.995 ;
     RECT  77.22 85.725 96.12 85.995 ;
     RECT  2.16 86.265 41.148 86.535 ;
     RECT  77.22 86.265 96.12 86.535 ;
     RECT  2.16 86.805 41.148 87.075 ;
     RECT  77.22 86.805 96.12 87.075 ;
     RECT  2.16 87.345 41.148 87.615 ;
     RECT  77.22 87.345 96.12 87.615 ;
     RECT  2.16 87.885 41.148 88.155 ;
     RECT  77.22 87.885 96.12 88.155 ;
     RECT  2.16 88.425 41.148 88.695 ;
     RECT  77.22 88.425 96.12 88.695 ;
     RECT  2.16 88.965 41.148 89.235 ;
     RECT  77.22 88.965 96.12 89.235 ;
     RECT  2.16 89.505 41.148 89.775 ;
     RECT  77.22 89.505 96.12 89.775 ;
     RECT  2.16 90.045 41.148 90.315 ;
     RECT  77.22 90.045 96.12 90.315 ;
     RECT  2.16 90.585 41.148 90.855 ;
     RECT  77.22 90.585 96.12 90.855 ;
     RECT  2.16 91.125 41.148 91.395 ;
     RECT  77.22 91.125 96.12 91.395 ;
     RECT  2.16 91.665 41.148 91.935 ;
     RECT  77.22 91.665 96.12 91.935 ;
     RECT  2.16 92.205 41.148 92.475 ;
     RECT  77.22 92.205 96.12 92.475 ;
     RECT  2.16 92.745 41.148 93.015 ;
     RECT  77.22 92.745 96.12 93.015 ;
     RECT  2.16 93.285 41.148 93.555 ;
     RECT  77.22 93.285 96.12 93.555 ;
     RECT  2.16 93.825 41.148 94.095 ;
     RECT  77.22 93.825 96.12 94.095 ;
     RECT  2.16 94.365 41.148 94.635 ;
     RECT  77.22 94.365 96.12 94.635 ;
     RECT  2.16 94.905 41.148 95.175 ;
     RECT  77.22 94.905 96.12 95.175 ;
     RECT  2.16 95.445 41.148 95.715 ;
     RECT  77.22 95.445 96.12 95.715 ;
     RECT  2.16 95.985 41.148 96.255 ;
     RECT  77.22 95.985 96.12 96.255 ;
     RECT  2.16 96.525 41.148 96.795 ;
     RECT  77.22 96.525 96.12 96.795 ;
     RECT  2.16 97.065 41.148 97.335 ;
     RECT  77.22 97.065 96.12 97.335 ;
     RECT  2.16 97.605 41.148 97.875 ;
     RECT  77.22 97.605 96.12 97.875 ;
     RECT  2.16 98.145 41.148 98.415 ;
     RECT  77.22 98.145 96.12 98.415 ;
     RECT  2.16 98.685 41.148 98.955 ;
     RECT  77.22 98.685 96.12 98.955 ;
     RECT  2.16 99.225 41.148 99.495 ;
     RECT  77.22 99.225 96.12 99.495 ;
     RECT  2.16 99.765 41.148 100.035 ;
     RECT  77.22 99.765 96.12 100.035 ;
     RECT  2.16 100.305 41.148 100.575 ;
     RECT  77.22 100.305 96.12 100.575 ;
     RECT  2.16 100.845 41.148 101.115 ;
     RECT  77.22 100.845 96.12 101.115 ;
     RECT  2.16 101.385 41.148 101.655 ;
     RECT  77.22 101.385 96.12 101.655 ;
     RECT  2.16 101.925 41.148 102.195 ;
     RECT  77.22 101.925 96.12 102.195 ;
     RECT  2.16 102.465 41.148 102.735 ;
     RECT  77.22 102.465 96.12 102.735 ;
     RECT  2.16 103.005 41.148 103.275 ;
     RECT  77.22 103.005 96.12 103.275 ;
     RECT  2.16 103.545 41.148 103.815 ;
     RECT  77.22 103.545 96.12 103.815 ;
     RECT  2.16 104.085 41.148 104.355 ;
     RECT  77.22 104.085 96.12 104.355 ;
     RECT  2.16 104.625 41.148 104.895 ;
     RECT  77.22 104.625 96.12 104.895 ;
     RECT  2.16 105.165 41.148 105.435 ;
     RECT  77.22 105.165 96.12 105.435 ;
     RECT  2.16 105.705 41.148 105.84 ;
     RECT  77.22 105.705 96.12 105.84 ;
     RECT  2.16 105.84 96.12 105.975 ;
     RECT  2.16 106.245 96.12 106.515 ;
     RECT  2.16 106.785 96.12 107.055 ;
     RECT  2.16 107.325 96.12 107.595 ;
     RECT  2.16 107.865 96.12 108.135 ;
     RECT  2.16 108.405 96.12 108.675 ;
     RECT  2.16 108.945 96.12 109.215 ;
     RECT  2.16 109.485 96.12 109.755 ;
     RECT  2.16 110.025 96.12 110.295 ;
     RECT  2.16 110.565 96.12 110.835 ;
     RECT  2.16 111.105 96.12 111.375 ;
     RECT  2.16 111.645 96.12 111.915 ;
     RECT  2.16 112.185 96.12 112.455 ;
     RECT  2.16 112.725 96.12 112.995 ;
     RECT  2.16 113.265 96.12 113.535 ;
     RECT  2.16 113.805 96.12 114.075 ;
     RECT  2.16 114.345 96.12 114.615 ;
     RECT  2.16 114.885 96.12 115.155 ;
     RECT  2.16 115.425 96.12 115.695 ;
     RECT  2.16 115.965 96.12 116.235 ;
     RECT  2.16 116.505 96.12 116.775 ;
     RECT  2.16 117.045 96.12 117.315 ;
     RECT  2.16 117.585 96.12 117.855 ;
     RECT  2.16 118.125 96.12 118.395 ;
     RECT  2.16 118.665 96.12 118.935 ;
     RECT  2.16 119.205 96.12 119.475 ;
     RECT  2.16 119.745 96.12 120.015 ;
     RECT  2.16 120.285 96.12 120.555 ;
     RECT  2.16 120.825 96.12 121.095 ;
     RECT  2.16 121.365 96.12 121.635 ;
     RECT  2.16 121.905 96.12 122.175 ;
     RECT  2.16 122.445 96.12 122.715 ;
     RECT  2.16 122.985 96.12 123.255 ;
     RECT  2.16 123.525 96.12 123.795 ;
     RECT  2.16 124.065 96.12 124.335 ;
     RECT  2.16 124.605 96.12 124.875 ;
     RECT  2.16 125.145 96.12 125.415 ;
     RECT  2.16 125.685 96.12 125.955 ;
     RECT  2.16 126.225 96.12 126.495 ;
     RECT  2.16 126.765 96.12 127.035 ;
     RECT  2.16 127.305 96.12 127.44 ;
     RECT  2.16 127.44 41.148 127.575 ;
     RECT  77.22 127.44 96.12 127.575 ;
     RECT  2.16 127.845 41.148 128.115 ;
     RECT  77.22 127.845 96.12 128.115 ;
     RECT  2.16 128.385 41.148 128.655 ;
     RECT  77.22 128.385 96.12 128.655 ;
     RECT  2.16 128.925 41.148 129.195 ;
     RECT  77.22 128.925 96.12 129.195 ;
     RECT  2.16 129.465 41.148 129.735 ;
     RECT  77.22 129.465 96.12 129.735 ;
     RECT  2.16 130.005 41.148 130.275 ;
     RECT  77.22 130.005 96.12 130.275 ;
     RECT  2.16 130.545 41.148 130.815 ;
     RECT  77.22 130.545 96.12 130.815 ;
     RECT  2.16 131.085 41.148 131.355 ;
     RECT  77.22 131.085 96.12 131.355 ;
     RECT  2.16 131.625 41.148 131.895 ;
     RECT  77.22 131.625 96.12 131.895 ;
     RECT  2.16 132.165 41.148 132.435 ;
     RECT  77.22 132.165 96.12 132.435 ;
     RECT  2.16 132.705 41.148 132.975 ;
     RECT  77.22 132.705 96.12 132.975 ;
     RECT  2.16 133.245 41.148 133.515 ;
     RECT  77.22 133.245 96.12 133.515 ;
     RECT  2.16 133.785 41.148 134.055 ;
     RECT  77.22 133.785 96.12 134.055 ;
     RECT  2.16 134.325 41.148 134.595 ;
     RECT  77.22 134.325 96.12 134.595 ;
     RECT  2.16 134.865 41.148 135.135 ;
     RECT  77.22 134.865 96.12 135.135 ;
     RECT  2.16 135.405 41.148 135.675 ;
     RECT  77.22 135.405 96.12 135.675 ;
     RECT  2.16 135.945 41.148 136.215 ;
     RECT  77.22 135.945 96.12 136.215 ;
     RECT  2.16 136.485 41.148 136.755 ;
     RECT  77.22 136.485 96.12 136.755 ;
     RECT  2.16 137.025 41.148 137.295 ;
     RECT  77.22 137.025 96.12 137.295 ;
     RECT  2.16 137.565 41.148 137.835 ;
     RECT  77.22 137.565 96.12 137.835 ;
     RECT  2.16 138.105 41.148 138.375 ;
     RECT  77.22 138.105 96.12 138.375 ;
     RECT  2.16 138.645 41.148 138.915 ;
     RECT  77.22 138.645 96.12 138.915 ;
     RECT  2.16 139.185 41.148 139.455 ;
     RECT  77.22 139.185 96.12 139.455 ;
     RECT  2.16 139.725 41.148 139.995 ;
     RECT  77.22 139.725 96.12 139.995 ;
     RECT  2.16 140.265 41.148 140.535 ;
     RECT  77.22 140.265 96.12 140.535 ;
     RECT  2.16 140.805 41.148 141.075 ;
     RECT  77.22 140.805 96.12 141.075 ;
     RECT  2.16 141.345 41.148 141.615 ;
     RECT  77.22 141.345 96.12 141.615 ;
     RECT  2.16 141.885 41.148 142.155 ;
     RECT  77.22 141.885 96.12 142.155 ;
     RECT  2.16 142.425 41.148 142.695 ;
     RECT  77.22 142.425 96.12 142.695 ;
     RECT  2.16 142.965 41.148 143.235 ;
     RECT  77.22 142.965 96.12 143.235 ;
     RECT  2.16 143.505 41.148 143.775 ;
     RECT  77.22 143.505 96.12 143.775 ;
     RECT  2.16 144.045 41.148 144.315 ;
     RECT  77.22 144.045 96.12 144.315 ;
     RECT  2.16 144.585 41.148 144.855 ;
     RECT  77.22 144.585 96.12 144.855 ;
     RECT  2.16 145.125 41.148 145.395 ;
     RECT  77.22 145.125 96.12 145.395 ;
     RECT  2.16 145.665 41.148 145.935 ;
     RECT  77.22 145.665 96.12 145.935 ;
     RECT  2.16 146.205 41.148 146.475 ;
     RECT  77.22 146.205 96.12 146.475 ;
     RECT  2.16 146.745 41.148 147.015 ;
     RECT  77.22 146.745 96.12 147.015 ;
     RECT  2.16 147.285 41.148 147.555 ;
     RECT  77.22 147.285 96.12 147.555 ;
     RECT  2.16 147.825 41.148 148.095 ;
     RECT  77.22 147.825 96.12 148.095 ;
     RECT  2.16 148.365 41.148 148.635 ;
     RECT  77.22 148.365 96.12 148.635 ;
     RECT  2.16 148.905 41.148 149.04 ;
     RECT  77.22 148.905 96.12 149.04 ;
     RECT  2.16 149.04 96.12 149.175 ;
     RECT  2.16 149.445 96.12 149.715 ;
     RECT  2.16 149.985 96.12 150.255 ;
     RECT  2.16 150.525 96.12 150.795 ;
     RECT  2.16 151.065 96.12 151.335 ;
     RECT  2.16 151.605 96.12 151.875 ;
     RECT  2.16 152.145 96.12 152.415 ;
     RECT  2.16 152.685 96.12 152.955 ;
     RECT  2.16 153.225 96.12 153.495 ;
     RECT  2.16 153.765 96.12 154.035 ;
     RECT  2.16 154.305 96.12 154.575 ;
     RECT  2.16 154.845 96.12 155.115 ;
     RECT  2.16 155.385 96.12 155.655 ;
     RECT  2.16 155.925 96.12 156.195 ;
     RECT  2.16 156.465 96.12 156.735 ;
     RECT  2.16 157.005 96.12 157.275 ;
     RECT  2.16 157.545 96.12 157.815 ;
     RECT  2.16 158.085 96.12 158.355 ;
     RECT  2.16 158.625 96.12 158.895 ;
     RECT  2.16 159.165 96.12 159.435 ;
     RECT  2.16 159.705 96.12 159.975 ;
     RECT  2.16 160.245 96.12 160.515 ;
     RECT  2.16 160.785 96.12 161.055 ;
     RECT  2.16 161.325 96.12 161.595 ;
     RECT  2.16 161.865 96.12 162.135 ;
     RECT  2.16 162.405 96.12 162.675 ;
     RECT  2.16 162.945 96.12 163.215 ;
     RECT  2.16 163.485 96.12 163.755 ;
     RECT  2.16 164.025 96.12 164.295 ;
     RECT  2.16 164.565 96.12 164.835 ;
     RECT  2.16 165.105 96.12 165.375 ;
     RECT  2.16 165.645 96.12 165.915 ;
     RECT  2.16 166.185 96.12 166.455 ;
     RECT  2.16 166.725 96.12 166.995 ;
     RECT  2.16 167.265 96.12 167.535 ;
     RECT  2.16 167.805 96.12 168.075 ;
     RECT  2.16 168.345 96.12 168.48 ;
    LAYER RVTP ;
     RECT  2.16 2.295 96.12 2.565 ;
     RECT  2.16 2.835 96.12 3.105 ;
     RECT  2.16 3.375 96.12 3.645 ;
     RECT  2.16 3.915 96.12 4.185 ;
     RECT  2.16 4.455 96.12 4.725 ;
     RECT  2.16 4.995 96.12 5.265 ;
     RECT  2.16 5.535 96.12 5.805 ;
     RECT  2.16 6.075 96.12 6.345 ;
     RECT  2.16 6.615 96.12 6.885 ;
     RECT  2.16 7.155 96.12 7.425 ;
     RECT  2.16 7.695 96.12 7.965 ;
     RECT  2.16 8.235 96.12 8.505 ;
     RECT  2.16 8.775 96.12 9.045 ;
     RECT  2.16 9.315 96.12 9.585 ;
     RECT  2.16 9.855 96.12 10.125 ;
     RECT  2.16 10.395 96.12 10.665 ;
     RECT  2.16 10.935 96.12 11.205 ;
     RECT  2.16 11.475 96.12 11.745 ;
     RECT  2.16 12.015 96.12 12.285 ;
     RECT  2.16 12.555 96.12 12.825 ;
     RECT  2.16 13.095 96.12 13.365 ;
     RECT  2.16 13.635 96.12 13.905 ;
     RECT  2.16 14.175 96.12 14.445 ;
     RECT  2.16 14.715 96.12 14.985 ;
     RECT  2.16 15.255 96.12 15.525 ;
     RECT  2.16 15.795 96.12 16.065 ;
     RECT  2.16 16.335 96.12 16.605 ;
     RECT  2.16 16.875 96.12 17.145 ;
     RECT  2.16 17.415 96.12 17.685 ;
     RECT  2.16 17.955 96.12 18.225 ;
     RECT  2.16 18.495 96.12 18.765 ;
     RECT  2.16 19.035 96.12 19.305 ;
     RECT  2.16 19.575 96.12 19.845 ;
     RECT  2.16 20.115 96.12 20.385 ;
     RECT  2.16 20.655 96.12 20.925 ;
     RECT  2.16 21.195 96.12 21.465 ;
     RECT  2.16 21.735 96.12 22.005 ;
     RECT  2.16 22.275 96.12 22.545 ;
     RECT  2.16 22.815 96.12 23.085 ;
     RECT  2.16 23.355 96.12 23.625 ;
     RECT  2.16 23.895 96.12 24.165 ;
     RECT  2.16 24.435 96.12 24.705 ;
     RECT  2.16 24.975 96.12 25.245 ;
     RECT  2.16 25.515 96.12 25.785 ;
     RECT  2.16 26.055 96.12 26.325 ;
     RECT  2.16 26.595 96.12 26.865 ;
     RECT  2.16 27.135 96.12 27.405 ;
     RECT  2.16 27.675 96.12 27.945 ;
     RECT  2.16 28.215 96.12 28.485 ;
     RECT  2.16 28.755 96.12 29.025 ;
     RECT  2.16 29.295 96.12 29.565 ;
     RECT  2.16 29.835 96.12 30.105 ;
     RECT  2.16 30.375 96.12 30.645 ;
     RECT  2.16 30.915 96.12 31.185 ;
     RECT  2.16 31.455 96.12 31.725 ;
     RECT  2.16 31.995 96.12 32.265 ;
     RECT  2.16 32.535 96.12 32.805 ;
     RECT  2.16 33.075 96.12 33.345 ;
     RECT  2.16 33.615 96.12 33.885 ;
     RECT  2.16 34.155 96.12 34.425 ;
     RECT  2.16 34.695 96.12 34.965 ;
     RECT  2.16 35.235 96.12 35.505 ;
     RECT  2.16 35.775 96.12 36.045 ;
     RECT  2.16 36.315 96.12 36.585 ;
     RECT  2.16 36.855 96.12 37.125 ;
     RECT  2.16 37.395 96.12 37.665 ;
     RECT  2.16 37.935 96.12 38.205 ;
     RECT  2.16 38.475 96.12 38.745 ;
     RECT  2.16 39.015 96.12 39.285 ;
     RECT  2.16 39.555 96.12 39.825 ;
     RECT  2.16 40.095 96.12 40.365 ;
     RECT  2.16 40.635 96.12 40.905 ;
     RECT  2.16 41.175 41.148 41.445 ;
     RECT  77.22 41.175 96.12 41.445 ;
     RECT  2.16 41.715 41.148 41.985 ;
     RECT  77.22 41.715 96.12 41.985 ;
     RECT  2.16 42.255 41.148 42.525 ;
     RECT  77.22 42.255 96.12 42.525 ;
     RECT  2.16 42.795 41.148 43.065 ;
     RECT  77.22 42.795 96.12 43.065 ;
     RECT  2.16 43.335 41.148 43.605 ;
     RECT  77.22 43.335 96.12 43.605 ;
     RECT  2.16 43.875 41.148 44.145 ;
     RECT  77.22 43.875 96.12 44.145 ;
     RECT  2.16 44.415 41.148 44.685 ;
     RECT  77.22 44.415 96.12 44.685 ;
     RECT  2.16 44.955 41.148 45.225 ;
     RECT  77.22 44.955 96.12 45.225 ;
     RECT  2.16 45.495 41.148 45.765 ;
     RECT  77.22 45.495 96.12 45.765 ;
     RECT  2.16 46.035 41.148 46.305 ;
     RECT  77.22 46.035 96.12 46.305 ;
     RECT  2.16 46.575 41.148 46.845 ;
     RECT  77.22 46.575 96.12 46.845 ;
     RECT  2.16 47.115 41.148 47.385 ;
     RECT  77.22 47.115 96.12 47.385 ;
     RECT  2.16 47.655 41.148 47.925 ;
     RECT  77.22 47.655 96.12 47.925 ;
     RECT  2.16 48.195 41.148 48.465 ;
     RECT  77.22 48.195 96.12 48.465 ;
     RECT  2.16 48.735 41.148 49.005 ;
     RECT  77.22 48.735 96.12 49.005 ;
     RECT  2.16 49.275 41.148 49.545 ;
     RECT  77.22 49.275 96.12 49.545 ;
     RECT  2.16 49.815 41.148 50.085 ;
     RECT  77.22 49.815 96.12 50.085 ;
     RECT  2.16 50.355 41.148 50.625 ;
     RECT  77.22 50.355 96.12 50.625 ;
     RECT  2.16 50.895 41.148 51.165 ;
     RECT  77.22 50.895 96.12 51.165 ;
     RECT  2.16 51.435 41.148 51.705 ;
     RECT  77.22 51.435 96.12 51.705 ;
     RECT  2.16 51.975 41.148 52.245 ;
     RECT  77.22 51.975 96.12 52.245 ;
     RECT  2.16 52.515 41.148 52.785 ;
     RECT  77.22 52.515 96.12 52.785 ;
     RECT  2.16 53.055 41.148 53.325 ;
     RECT  77.22 53.055 96.12 53.325 ;
     RECT  2.16 53.595 41.148 53.865 ;
     RECT  77.22 53.595 96.12 53.865 ;
     RECT  2.16 54.135 41.148 54.405 ;
     RECT  77.22 54.135 96.12 54.405 ;
     RECT  2.16 54.675 41.148 54.945 ;
     RECT  77.22 54.675 96.12 54.945 ;
     RECT  2.16 55.215 41.148 55.485 ;
     RECT  77.22 55.215 96.12 55.485 ;
     RECT  2.16 55.755 41.148 56.025 ;
     RECT  77.22 55.755 96.12 56.025 ;
     RECT  2.16 56.295 41.148 56.565 ;
     RECT  77.22 56.295 96.12 56.565 ;
     RECT  2.16 56.835 41.148 57.105 ;
     RECT  77.22 56.835 96.12 57.105 ;
     RECT  2.16 57.375 41.148 57.645 ;
     RECT  77.22 57.375 96.12 57.645 ;
     RECT  2.16 57.915 41.148 58.185 ;
     RECT  77.22 57.915 96.12 58.185 ;
     RECT  2.16 58.455 41.148 58.725 ;
     RECT  77.22 58.455 96.12 58.725 ;
     RECT  2.16 58.995 41.148 59.265 ;
     RECT  77.22 58.995 96.12 59.265 ;
     RECT  2.16 59.535 41.148 59.805 ;
     RECT  77.22 59.535 96.12 59.805 ;
     RECT  2.16 60.075 41.148 60.345 ;
     RECT  77.22 60.075 96.12 60.345 ;
     RECT  2.16 60.615 41.148 60.885 ;
     RECT  77.22 60.615 96.12 60.885 ;
     RECT  2.16 61.155 41.148 61.425 ;
     RECT  77.22 61.155 96.12 61.425 ;
     RECT  2.16 61.695 41.148 61.965 ;
     RECT  77.22 61.695 96.12 61.965 ;
     RECT  2.16 62.235 41.148 62.505 ;
     RECT  77.22 62.235 96.12 62.505 ;
     RECT  2.16 62.775 96.12 63.045 ;
     RECT  2.16 63.315 96.12 63.585 ;
     RECT  2.16 63.855 96.12 64.125 ;
     RECT  2.16 64.395 96.12 64.665 ;
     RECT  2.16 64.935 96.12 65.205 ;
     RECT  2.16 65.475 96.12 65.745 ;
     RECT  2.16 66.015 96.12 66.285 ;
     RECT  2.16 66.555 96.12 66.825 ;
     RECT  2.16 67.095 96.12 67.365 ;
     RECT  2.16 67.635 96.12 67.905 ;
     RECT  2.16 68.175 96.12 68.445 ;
     RECT  2.16 68.715 96.12 68.985 ;
     RECT  2.16 69.255 96.12 69.525 ;
     RECT  2.16 69.795 96.12 70.065 ;
     RECT  2.16 70.335 96.12 70.605 ;
     RECT  2.16 70.875 96.12 71.145 ;
     RECT  2.16 71.415 96.12 71.685 ;
     RECT  2.16 71.955 96.12 72.225 ;
     RECT  2.16 72.495 96.12 72.765 ;
     RECT  2.16 73.035 96.12 73.305 ;
     RECT  2.16 73.575 96.12 73.845 ;
     RECT  2.16 74.115 96.12 74.385 ;
     RECT  2.16 74.655 96.12 74.925 ;
     RECT  2.16 75.195 96.12 75.465 ;
     RECT  2.16 75.735 96.12 76.005 ;
     RECT  2.16 76.275 96.12 76.545 ;
     RECT  2.16 76.815 96.12 77.085 ;
     RECT  2.16 77.355 96.12 77.625 ;
     RECT  2.16 77.895 96.12 78.165 ;
     RECT  2.16 78.435 96.12 78.705 ;
     RECT  2.16 78.975 96.12 79.245 ;
     RECT  2.16 79.515 96.12 79.785 ;
     RECT  2.16 80.055 96.12 80.325 ;
     RECT  2.16 80.595 96.12 80.865 ;
     RECT  2.16 81.135 96.12 81.405 ;
     RECT  2.16 81.675 96.12 81.945 ;
     RECT  2.16 82.215 96.12 82.485 ;
     RECT  2.16 82.755 96.12 83.025 ;
     RECT  2.16 83.295 96.12 83.565 ;
     RECT  2.16 83.835 96.12 84.105 ;
     RECT  2.16 84.375 41.148 84.645 ;
     RECT  77.22 84.375 96.12 84.645 ;
     RECT  2.16 84.915 41.148 85.185 ;
     RECT  77.22 84.915 96.12 85.185 ;
     RECT  2.16 85.455 41.148 85.725 ;
     RECT  77.22 85.455 96.12 85.725 ;
     RECT  2.16 85.995 41.148 86.265 ;
     RECT  77.22 85.995 96.12 86.265 ;
     RECT  2.16 86.535 41.148 86.805 ;
     RECT  77.22 86.535 96.12 86.805 ;
     RECT  2.16 87.075 41.148 87.345 ;
     RECT  77.22 87.075 96.12 87.345 ;
     RECT  2.16 87.615 41.148 87.885 ;
     RECT  77.22 87.615 96.12 87.885 ;
     RECT  2.16 88.155 41.148 88.425 ;
     RECT  77.22 88.155 96.12 88.425 ;
     RECT  2.16 88.695 41.148 88.965 ;
     RECT  77.22 88.695 96.12 88.965 ;
     RECT  2.16 89.235 41.148 89.505 ;
     RECT  77.22 89.235 96.12 89.505 ;
     RECT  2.16 89.775 41.148 90.045 ;
     RECT  77.22 89.775 96.12 90.045 ;
     RECT  2.16 90.315 41.148 90.585 ;
     RECT  77.22 90.315 96.12 90.585 ;
     RECT  2.16 90.855 41.148 91.125 ;
     RECT  77.22 90.855 96.12 91.125 ;
     RECT  2.16 91.395 41.148 91.665 ;
     RECT  77.22 91.395 96.12 91.665 ;
     RECT  2.16 91.935 41.148 92.205 ;
     RECT  77.22 91.935 96.12 92.205 ;
     RECT  2.16 92.475 41.148 92.745 ;
     RECT  77.22 92.475 96.12 92.745 ;
     RECT  2.16 93.015 41.148 93.285 ;
     RECT  77.22 93.015 96.12 93.285 ;
     RECT  2.16 93.555 41.148 93.825 ;
     RECT  77.22 93.555 96.12 93.825 ;
     RECT  2.16 94.095 41.148 94.365 ;
     RECT  77.22 94.095 96.12 94.365 ;
     RECT  2.16 94.635 41.148 94.905 ;
     RECT  77.22 94.635 96.12 94.905 ;
     RECT  2.16 95.175 41.148 95.445 ;
     RECT  77.22 95.175 96.12 95.445 ;
     RECT  2.16 95.715 41.148 95.985 ;
     RECT  77.22 95.715 96.12 95.985 ;
     RECT  2.16 96.255 41.148 96.525 ;
     RECT  77.22 96.255 96.12 96.525 ;
     RECT  2.16 96.795 41.148 97.065 ;
     RECT  77.22 96.795 96.12 97.065 ;
     RECT  2.16 97.335 41.148 97.605 ;
     RECT  77.22 97.335 96.12 97.605 ;
     RECT  2.16 97.875 41.148 98.145 ;
     RECT  77.22 97.875 96.12 98.145 ;
     RECT  2.16 98.415 41.148 98.685 ;
     RECT  77.22 98.415 96.12 98.685 ;
     RECT  2.16 98.955 41.148 99.225 ;
     RECT  77.22 98.955 96.12 99.225 ;
     RECT  2.16 99.495 41.148 99.765 ;
     RECT  77.22 99.495 96.12 99.765 ;
     RECT  2.16 100.035 41.148 100.305 ;
     RECT  77.22 100.035 96.12 100.305 ;
     RECT  2.16 100.575 41.148 100.845 ;
     RECT  77.22 100.575 96.12 100.845 ;
     RECT  2.16 101.115 41.148 101.385 ;
     RECT  77.22 101.115 96.12 101.385 ;
     RECT  2.16 101.655 41.148 101.925 ;
     RECT  77.22 101.655 96.12 101.925 ;
     RECT  2.16 102.195 41.148 102.465 ;
     RECT  77.22 102.195 96.12 102.465 ;
     RECT  2.16 102.735 41.148 103.005 ;
     RECT  77.22 102.735 96.12 103.005 ;
     RECT  2.16 103.275 41.148 103.545 ;
     RECT  77.22 103.275 96.12 103.545 ;
     RECT  2.16 103.815 41.148 104.085 ;
     RECT  77.22 103.815 96.12 104.085 ;
     RECT  2.16 104.355 41.148 104.625 ;
     RECT  77.22 104.355 96.12 104.625 ;
     RECT  2.16 104.895 41.148 105.165 ;
     RECT  77.22 104.895 96.12 105.165 ;
     RECT  2.16 105.435 41.148 105.705 ;
     RECT  77.22 105.435 96.12 105.705 ;
     RECT  2.16 105.975 96.12 106.245 ;
     RECT  2.16 106.515 96.12 106.785 ;
     RECT  2.16 107.055 96.12 107.325 ;
     RECT  2.16 107.595 96.12 107.865 ;
     RECT  2.16 108.135 96.12 108.405 ;
     RECT  2.16 108.675 96.12 108.945 ;
     RECT  2.16 109.215 96.12 109.485 ;
     RECT  2.16 109.755 96.12 110.025 ;
     RECT  2.16 110.295 96.12 110.565 ;
     RECT  2.16 110.835 96.12 111.105 ;
     RECT  2.16 111.375 96.12 111.645 ;
     RECT  2.16 111.915 96.12 112.185 ;
     RECT  2.16 112.455 96.12 112.725 ;
     RECT  2.16 112.995 96.12 113.265 ;
     RECT  2.16 113.535 96.12 113.805 ;
     RECT  2.16 114.075 96.12 114.345 ;
     RECT  2.16 114.615 96.12 114.885 ;
     RECT  2.16 115.155 96.12 115.425 ;
     RECT  2.16 115.695 96.12 115.965 ;
     RECT  2.16 116.235 96.12 116.505 ;
     RECT  2.16 116.775 96.12 117.045 ;
     RECT  2.16 117.315 96.12 117.585 ;
     RECT  2.16 117.855 96.12 118.125 ;
     RECT  2.16 118.395 96.12 118.665 ;
     RECT  2.16 118.935 96.12 119.205 ;
     RECT  2.16 119.475 96.12 119.745 ;
     RECT  2.16 120.015 96.12 120.285 ;
     RECT  2.16 120.555 96.12 120.825 ;
     RECT  2.16 121.095 96.12 121.365 ;
     RECT  2.16 121.635 96.12 121.905 ;
     RECT  2.16 122.175 96.12 122.445 ;
     RECT  2.16 122.715 96.12 122.985 ;
     RECT  2.16 123.255 96.12 123.525 ;
     RECT  2.16 123.795 96.12 124.065 ;
     RECT  2.16 124.335 96.12 124.605 ;
     RECT  2.16 124.875 96.12 125.145 ;
     RECT  2.16 125.415 96.12 125.685 ;
     RECT  2.16 125.955 96.12 126.225 ;
     RECT  2.16 126.495 96.12 126.765 ;
     RECT  2.16 127.035 96.12 127.305 ;
     RECT  2.16 127.575 41.148 127.845 ;
     RECT  77.22 127.575 96.12 127.845 ;
     RECT  2.16 128.115 41.148 128.385 ;
     RECT  77.22 128.115 96.12 128.385 ;
     RECT  2.16 128.655 41.148 128.925 ;
     RECT  77.22 128.655 96.12 128.925 ;
     RECT  2.16 129.195 41.148 129.465 ;
     RECT  77.22 129.195 96.12 129.465 ;
     RECT  2.16 129.735 41.148 130.005 ;
     RECT  77.22 129.735 96.12 130.005 ;
     RECT  2.16 130.275 41.148 130.545 ;
     RECT  77.22 130.275 96.12 130.545 ;
     RECT  2.16 130.815 41.148 131.085 ;
     RECT  77.22 130.815 96.12 131.085 ;
     RECT  2.16 131.355 41.148 131.625 ;
     RECT  77.22 131.355 96.12 131.625 ;
     RECT  2.16 131.895 41.148 132.165 ;
     RECT  77.22 131.895 96.12 132.165 ;
     RECT  2.16 132.435 41.148 132.705 ;
     RECT  77.22 132.435 96.12 132.705 ;
     RECT  2.16 132.975 41.148 133.245 ;
     RECT  77.22 132.975 96.12 133.245 ;
     RECT  2.16 133.515 41.148 133.785 ;
     RECT  77.22 133.515 96.12 133.785 ;
     RECT  2.16 134.055 41.148 134.325 ;
     RECT  77.22 134.055 96.12 134.325 ;
     RECT  2.16 134.595 41.148 134.865 ;
     RECT  77.22 134.595 96.12 134.865 ;
     RECT  2.16 135.135 41.148 135.405 ;
     RECT  77.22 135.135 96.12 135.405 ;
     RECT  2.16 135.675 41.148 135.945 ;
     RECT  77.22 135.675 96.12 135.945 ;
     RECT  2.16 136.215 41.148 136.485 ;
     RECT  77.22 136.215 96.12 136.485 ;
     RECT  2.16 136.755 41.148 137.025 ;
     RECT  77.22 136.755 96.12 137.025 ;
     RECT  2.16 137.295 41.148 137.565 ;
     RECT  77.22 137.295 96.12 137.565 ;
     RECT  2.16 137.835 41.148 138.105 ;
     RECT  77.22 137.835 96.12 138.105 ;
     RECT  2.16 138.375 41.148 138.645 ;
     RECT  77.22 138.375 96.12 138.645 ;
     RECT  2.16 138.915 41.148 139.185 ;
     RECT  77.22 138.915 96.12 139.185 ;
     RECT  2.16 139.455 41.148 139.725 ;
     RECT  77.22 139.455 96.12 139.725 ;
     RECT  2.16 139.995 41.148 140.265 ;
     RECT  77.22 139.995 96.12 140.265 ;
     RECT  2.16 140.535 41.148 140.805 ;
     RECT  77.22 140.535 96.12 140.805 ;
     RECT  2.16 141.075 41.148 141.345 ;
     RECT  77.22 141.075 96.12 141.345 ;
     RECT  2.16 141.615 41.148 141.885 ;
     RECT  77.22 141.615 96.12 141.885 ;
     RECT  2.16 142.155 41.148 142.425 ;
     RECT  77.22 142.155 96.12 142.425 ;
     RECT  2.16 142.695 41.148 142.965 ;
     RECT  77.22 142.695 96.12 142.965 ;
     RECT  2.16 143.235 41.148 143.505 ;
     RECT  77.22 143.235 96.12 143.505 ;
     RECT  2.16 143.775 41.148 144.045 ;
     RECT  77.22 143.775 96.12 144.045 ;
     RECT  2.16 144.315 41.148 144.585 ;
     RECT  77.22 144.315 96.12 144.585 ;
     RECT  2.16 144.855 41.148 145.125 ;
     RECT  77.22 144.855 96.12 145.125 ;
     RECT  2.16 145.395 41.148 145.665 ;
     RECT  77.22 145.395 96.12 145.665 ;
     RECT  2.16 145.935 41.148 146.205 ;
     RECT  77.22 145.935 96.12 146.205 ;
     RECT  2.16 146.475 41.148 146.745 ;
     RECT  77.22 146.475 96.12 146.745 ;
     RECT  2.16 147.015 41.148 147.285 ;
     RECT  77.22 147.015 96.12 147.285 ;
     RECT  2.16 147.555 41.148 147.825 ;
     RECT  77.22 147.555 96.12 147.825 ;
     RECT  2.16 148.095 41.148 148.365 ;
     RECT  77.22 148.095 96.12 148.365 ;
     RECT  2.16 148.635 41.148 148.905 ;
     RECT  77.22 148.635 96.12 148.905 ;
     RECT  2.16 149.175 96.12 149.445 ;
     RECT  2.16 149.715 96.12 149.985 ;
     RECT  2.16 150.255 96.12 150.525 ;
     RECT  2.16 150.795 96.12 151.065 ;
     RECT  2.16 151.335 96.12 151.605 ;
     RECT  2.16 151.875 96.12 152.145 ;
     RECT  2.16 152.415 96.12 152.685 ;
     RECT  2.16 152.955 96.12 153.225 ;
     RECT  2.16 153.495 96.12 153.765 ;
     RECT  2.16 154.035 96.12 154.305 ;
     RECT  2.16 154.575 96.12 154.845 ;
     RECT  2.16 155.115 96.12 155.385 ;
     RECT  2.16 155.655 96.12 155.925 ;
     RECT  2.16 156.195 96.12 156.465 ;
     RECT  2.16 156.735 96.12 157.005 ;
     RECT  2.16 157.275 96.12 157.545 ;
     RECT  2.16 157.815 96.12 158.085 ;
     RECT  2.16 158.355 96.12 158.625 ;
     RECT  2.16 158.895 96.12 159.165 ;
     RECT  2.16 159.435 96.12 159.705 ;
     RECT  2.16 159.975 96.12 160.245 ;
     RECT  2.16 160.515 96.12 160.785 ;
     RECT  2.16 161.055 96.12 161.325 ;
     RECT  2.16 161.595 96.12 161.865 ;
     RECT  2.16 162.135 96.12 162.405 ;
     RECT  2.16 162.675 96.12 162.945 ;
     RECT  2.16 163.215 96.12 163.485 ;
     RECT  2.16 163.755 96.12 164.025 ;
     RECT  2.16 164.295 96.12 164.565 ;
     RECT  2.16 164.835 96.12 165.105 ;
     RECT  2.16 165.375 96.12 165.645 ;
     RECT  2.16 165.915 96.12 166.185 ;
     RECT  2.16 166.455 96.12 166.725 ;
     RECT  2.16 166.995 96.12 167.265 ;
     RECT  2.16 167.535 96.12 167.805 ;
     RECT  2.16 168.075 96.12 168.345 ;
    LAYER M1 ;
     RECT  2.16 2.151 96.12 41.049 ;
     RECT  43.2 43.2 75.192 60.504 ;
     RECT  2.16 41.049 41.148 62.631 ;
     RECT  77.22 41.049 96.12 62.631 ;
     RECT  2.16 62.631 96.12 84.249 ;
     RECT  43.2 86.4 75.192 103.704 ;
     RECT  2.16 84.249 41.148 105.831 ;
     RECT  77.22 84.249 96.12 105.831 ;
     RECT  2.16 105.831 96.12 127.449 ;
     RECT  43.2 129.6 75.192 146.904 ;
     RECT  2.16 127.449 41.148 149.031 ;
     RECT  77.22 127.449 96.12 149.031 ;
     RECT  2.16 149.031 96.12 168.489 ;
    LAYER M2 ;
     RECT  0.103 31.896 0.139 32.364 ;
     RECT  0.103 34.866 0.139 35.874 ;
     RECT  0.103 129.816 0.203 131.148 ;
     RECT  0.103 33.426 0.535 33.444 ;
     RECT  0.139 34.866 0.535 35.964 ;
     RECT  0.103 43.848 0.535 44.406 ;
     RECT  0.103 74.466 0.535 75.024 ;
     RECT  0.103 75.906 0.535 76.914 ;
     RECT  0.139 31.806 2.16 32.364 ;
     RECT  0.535 33.426 2.16 35.964 ;
     RECT  0.103 40.986 2.16 42.084 ;
     RECT  0.535 43.146 2.16 44.406 ;
     RECT  0.535 74.466 2.16 76.914 ;
     RECT  0.103 78.516 2.16 78.534 ;
     RECT  0.535 84.726 2.16 84.744 ;
     RECT  0.103 85.968 2.16 87.714 ;
     RECT  0.103 118.134 2.16 118.152 ;
     RECT  0.103 121.716 2.16 121.734 ;
     RECT  0.203 129.816 2.16 130.536 ;
     RECT  37.831 170.586 37.903 170.604 ;
     RECT  37.903 170.514 38.219 170.604 ;
     RECT  38.219 170.586 38.867 170.604 ;
     RECT  2.16 2.151 41.148 168.489 ;
     RECT  41.148 2.151 41.171 45.756 ;
     RECT  41.148 101.826 41.171 101.844 ;
     RECT  41.171 2.151 41.207 45.594 ;
     RECT  41.207 2.151 41.279 44.136 ;
     RECT  41.148 100.62 41.279 101.034 ;
     RECT  41.148 129.168 41.315 131.652 ;
     RECT  41.148 144.486 41.351 144.684 ;
     RECT  41.148 50.751 41.387 56.934 ;
     RECT  41.148 96.606 41.387 99.756 ;
     RECT  41.315 129.168 41.387 129.294 ;
     RECT  41.279 100.62 41.423 100.638 ;
     RECT  41.279 2.151 41.459 43.668 ;
     RECT  41.387 96.606 41.459 99.684 ;
     RECT  41.459 42.228 41.495 43.668 ;
     RECT  41.459 96.606 41.495 99.594 ;
     RECT  41.315 130.446 41.531 131.652 ;
     RECT  41.495 96.876 41.567 99.594 ;
     RECT  41.148 142.596 41.603 142.614 ;
     RECT  41.148 87.156 41.639 90.612 ;
     RECT  41.148 91.368 41.639 92.772 ;
     RECT  41.148 137.106 41.639 139.554 ;
     RECT  41.639 87.156 41.675 90.306 ;
     RECT  41.207 45.036 41.783 45.594 ;
     RECT  41.531 130.446 41.783 131.418 ;
     RECT  41.495 42.228 41.819 43.596 ;
     RECT  41.819 42.228 41.855 43.164 ;
     RECT  41.855 42.462 41.927 43.164 ;
     RECT  41.148 105.831 42.043 127.449 ;
     RECT  41.387 50.751 42.079 56.484 ;
     RECT  41.148 93.996 42.143 95.634 ;
     RECT  41.148 140.706 42.143 141.804 ;
     RECT  42.079 50.706 42.179 56.484 ;
     RECT  41.148 134.1 42.179 135.36 ;
     RECT  41.639 137.574 42.179 139.554 ;
     RECT  42.179 51.246 42.215 56.484 ;
     RECT  41.675 89.442 42.215 90.306 ;
     RECT  41.639 91.368 42.215 92.7 ;
     RECT  42.143 93.996 42.215 94.59 ;
     RECT  42.179 137.844 42.215 138.204 ;
     RECT  41.351 144.666 42.215 144.684 ;
     RECT  41.675 87.156 42.251 88.65 ;
     RECT  42.215 90.288 42.251 90.306 ;
     RECT  42.179 134.1 42.251 135.09 ;
     RECT  42.251 87.156 42.287 88.524 ;
     RECT  41.148 132.444 42.287 133.236 ;
     RECT  42.251 134.64 42.323 135.09 ;
     RECT  42.215 51.786 42.467 56.484 ;
     RECT  41.567 96.876 42.467 99.144 ;
     RECT  41.783 130.752 42.467 131.418 ;
     RECT  42.215 138.186 42.467 138.204 ;
     RECT  41.148 60.624 42.475 61.65 ;
     RECT  41.387 129.24 42.547 129.294 ;
     RECT  42.043 105.831 42.583 127.494 ;
     RECT  42.547 129.204 42.583 129.294 ;
     RECT  42.475 60.552 42.619 61.65 ;
     RECT  41.148 62.631 42.619 84.249 ;
     RECT  41.148 103.752 42.655 104.922 ;
     RECT  42.583 105.786 42.655 127.494 ;
     RECT  42.583 128.466 42.683 129.294 ;
     RECT  42.619 60.552 42.719 84.249 ;
     RECT  41.148 149.031 42.727 168.489 ;
     RECT  41.927 42.696 42.755 43.164 ;
     RECT  42.655 103.752 42.755 127.494 ;
     RECT  42.755 105.678 42.763 127.494 ;
     RECT  42.143 140.706 43.051 141.714 ;
     RECT  43.015 142.47 43.051 142.488 ;
     RECT  42.755 42.732 43.2 43.164 ;
     RECT  41.783 45.036 43.2 45.324 ;
     RECT  42.467 52.416 43.2 56.484 ;
     RECT  42.719 60.552 43.2 61.65 ;
     RECT  41.148 86.04 43.2 86.058 ;
     RECT  42.287 87.156 43.2 87.804 ;
     RECT  42.215 91.368 43.2 92.538 ;
     RECT  42.143 95.454 43.2 95.472 ;
     RECT  42.467 97.506 43.2 99.144 ;
     RECT  42.583 102.636 43.2 102.654 ;
     RECT  42.755 103.752 43.2 104.922 ;
     RECT  42.683 128.556 43.2 129.294 ;
     RECT  42.467 130.752 43.2 130.77 ;
     RECT  42.287 132.606 43.2 133.236 ;
     RECT  42.323 135.072 43.2 135.09 ;
     RECT  41.148 136.188 43.2 136.206 ;
     RECT  42.179 139.086 43.2 139.554 ;
     RECT  43.051 140.706 43.2 142.488 ;
     RECT  41.148 147.06 43.2 147.924 ;
     RECT  43.2 128.556 43.295 147.924 ;
     RECT  42.763 105.678 43.475 127.566 ;
     RECT  42.719 62.55 46.759 84.249 ;
     RECT  42.727 148.95 46.823 168.489 ;
     RECT  43.2 86.04 47.695 104.922 ;
     RECT  43.475 105.678 47.695 127.449 ;
     RECT  43.295 129.24 47.875 147.924 ;
     RECT  46.823 148.986 47.875 168.489 ;
     RECT  46.759 62.442 49.883 84.249 ;
     RECT  49.883 62.514 50.747 84.249 ;
     RECT  50.747 62.586 74.659 84.249 ;
     RECT  47.695 86.04 74.947 127.449 ;
     RECT  74.659 62.478 75.127 84.249 ;
     RECT  43.2 42.732 75.192 61.65 ;
     RECT  74.947 86.04 75.192 127.494 ;
     RECT  47.875 129.24 75.192 168.489 ;
     RECT  75.127 62.478 75.263 84.294 ;
     RECT  75.192 52.866 75.335 54.738 ;
     RECT  75.263 62.55 75.335 84.294 ;
     RECT  75.192 91.17 75.335 91.188 ;
     RECT  75.192 129.24 75.335 129.384 ;
     RECT  75.192 58.698 75.371 58.986 ;
     RECT  75.192 86.04 75.407 86.364 ;
     RECT  75.192 146.448 75.407 168.489 ;
     RECT  75.407 86.04 75.443 86.139 ;
     RECT  75.192 103.446 75.587 127.494 ;
     RECT  75.335 62.631 75.623 84.294 ;
     RECT  75.192 130.32 75.623 130.374 ;
     RECT  75.192 131.526 75.623 131.994 ;
     RECT  75.192 45 75.659 45.144 ;
     RECT  75.335 129.24 75.811 129.294 ;
     RECT  75.335 52.866 76.063 54.432 ;
     RECT  75.192 96.264 76.063 98.514 ;
     RECT  75.192 139.734 76.099 141.174 ;
     RECT  76.063 52.866 76.135 55.008 ;
     RECT  75.192 101.286 76.135 101.304 ;
     RECT  76.099 139.734 76.135 141.804 ;
     RECT  75.192 48.816 76.315 50.076 ;
     RECT  75.192 132.984 76.315 133.002 ;
     RECT  76.315 48.366 76.351 50.076 ;
     RECT  75.192 93.996 76.351 94.05 ;
     RECT  76.315 132.984 76.351 133.308 ;
     RECT  75.192 134.226 76.351 134.244 ;
     RECT  75.192 135.072 76.351 137.358 ;
     RECT  76.351 48.132 76.387 50.076 ;
     RECT  76.135 52.866 76.387 55.548 ;
     RECT  76.351 93.996 76.387 94.356 ;
     RECT  76.063 96.264 76.387 98.784 ;
     RECT  75.811 129.132 76.387 129.294 ;
     RECT  75.623 130.356 76.387 130.374 ;
     RECT  76.351 134.226 76.387 137.358 ;
     RECT  76.387 93.024 76.639 98.784 ;
     RECT  76.387 129.132 76.639 130.374 ;
     RECT  76.387 134.226 76.639 138.87 ;
     RECT  75.192 46.206 76.927 46.602 ;
     RECT  76.639 93.024 76.927 98.946 ;
     RECT  76.387 48.132 76.963 55.548 ;
     RECT  76.639 129.132 76.999 130.77 ;
     RECT  75.192 89.784 77.215 89.802 ;
     RECT  76.639 134.226 77.215 138.978 ;
     RECT  76.135 139.734 77.215 142.38 ;
     RECT  41.459 2.151 77.22 41.049 ;
     RECT  75.192 42.732 77.22 43.164 ;
     RECT  75.192 44.082 77.22 44.1 ;
     RECT  75.659 45.126 77.22 45.144 ;
     RECT  76.927 46.116 77.22 46.602 ;
     RECT  76.963 48.132 77.22 55.71 ;
     RECT  75.192 57.312 77.22 57.33 ;
     RECT  75.371 58.968 77.22 58.986 ;
     RECT  75.192 60.012 77.22 61.65 ;
     RECT  75.623 62.631 77.22 84.249 ;
     RECT  77.215 85.086 77.22 85.104 ;
     RECT  75.443 86.04 77.22 86.058 ;
     RECT  75.192 87.156 77.22 87.174 ;
     RECT  75.192 88.092 77.22 88.11 ;
     RECT  77.215 89.784 77.22 90.144 ;
     RECT  76.351 90.936 77.22 90.954 ;
     RECT  76.927 91.872 77.22 98.946 ;
     RECT  76.135 101.286 77.22 101.754 ;
     RECT  75.587 103.446 77.22 127.449 ;
     RECT  76.999 129.132 77.22 130.914 ;
     RECT  76.927 132.066 77.22 132.084 ;
     RECT  76.351 132.984 77.22 133.344 ;
     RECT  77.215 134.226 77.22 142.38 ;
     RECT  75.192 143.712 77.22 143.73 ;
     RECT  75.192 145.026 77.22 145.044 ;
     RECT  75.407 147.06 77.22 168.489 ;
     RECT  77.22 2.151 96.12 168.489 ;
     RECT  96.12 52.326 96.323 57.204 ;
     RECT  96.12 81.378 96.323 85.752 ;
     RECT  96.12 139.536 96.323 143.802 ;
     RECT  96.12 38.718 96.359 42.084 ;
     RECT  96.323 52.326 96.359 56.898 ;
     RECT  96.12 138.654 96.359 138.672 ;
     RECT  96.323 140.58 96.359 141.876 ;
     RECT  96.323 142.938 96.359 143.802 ;
     RECT  96.323 139.536 96.395 139.788 ;
     RECT  96.359 38.718 96.935 39.654 ;
     RECT  96.359 40.644 96.935 42.084 ;
     RECT  96.359 52.794 96.935 55.782 ;
     RECT  96.359 56.646 96.935 56.898 ;
     RECT  96.323 81.756 96.935 85.752 ;
     RECT  96.12 86.508 96.935 86.526 ;
     RECT  96.12 96.03 96.935 101.376 ;
     RECT  96.12 125.154 96.935 127.134 ;
     RECT  96.359 140.58 96.935 141.714 ;
     RECT  96.935 41.184 96.971 41.706 ;
     RECT  96.935 96.03 96.971 96.048 ;
     RECT  96.935 101.088 96.971 101.106 ;
     RECT  96.935 140.58 96.971 141.174 ;
     RECT  96.971 41.184 97.511 41.202 ;
     RECT  96.12 43.038 97.511 43.596 ;
     RECT  96.935 53.334 97.511 55.746 ;
     RECT  96.935 56.88 97.511 56.898 ;
     RECT  96.935 81.756 97.511 83.394 ;
     RECT  96.935 84.456 97.511 85.752 ;
     RECT  96.935 97.11 97.511 97.83 ;
     RECT  96.935 98.658 97.511 100.026 ;
     RECT  96.935 125.154 97.511 127.062 ;
     RECT  96.395 139.77 97.511 139.788 ;
     RECT  96.971 140.616 97.511 141.174 ;
     RECT  96.359 143.478 97.511 143.802 ;
     RECT  97.511 43.038 97.547 43.092 ;
     RECT  97.511 54.684 97.547 54.702 ;
     RECT  97.511 55.494 97.547 55.512 ;
     RECT  97.511 84.456 97.547 84.474 ;
     RECT  97.511 98.964 97.547 98.982 ;
     RECT  97.511 126.036 97.547 126.054 ;
     RECT  97.511 143.784 97.547 143.802 ;
     RECT  97.547 43.074 97.619 43.092 ;
     RECT  96.935 38.718 98.167 38.736 ;
     RECT  98.167 38.718 98.267 38.808 ;
     RECT  98.167 142.596 98.267 142.614 ;
    LAYER M3 ;
     RECT  2.415 2.143 2.505 2.413 ;
     RECT  5.115 2.143 5.205 2.413 ;
     RECT  7.815 2.143 7.905 2.413 ;
     RECT  10.515 2.143 10.605 2.413 ;
     RECT  13.215 2.143 13.305 2.413 ;
     RECT  15.915 2.143 16.005 2.413 ;
     RECT  18.615 2.143 18.705 2.413 ;
     RECT  21.315 2.143 21.405 2.413 ;
     RECT  24.015 2.143 24.105 2.413 ;
     RECT  26.715 2.143 26.805 2.413 ;
     RECT  29.415 2.143 29.505 2.413 ;
     RECT  32.115 2.143 32.205 2.413 ;
     RECT  34.815 2.143 34.905 2.413 ;
     RECT  37.515 2.143 37.605 2.413 ;
     RECT  40.215 2.143 40.305 2.413 ;
     RECT  42.915 2.143 43.005 2.413 ;
     RECT  45.615 2.143 45.705 2.413 ;
     RECT  48.315 2.143 48.405 2.413 ;
     RECT  51.015 2.143 51.105 2.413 ;
     RECT  53.715 2.143 53.805 2.413 ;
     RECT  56.415 2.143 56.505 2.413 ;
     RECT  59.115 2.143 59.205 2.413 ;
     RECT  61.815 2.143 61.905 2.413 ;
     RECT  64.515 2.143 64.605 2.413 ;
     RECT  67.215 2.143 67.305 2.413 ;
     RECT  69.915 2.143 70.005 2.413 ;
     RECT  72.615 2.143 72.705 2.413 ;
     RECT  75.315 2.143 75.405 2.413 ;
     RECT  78.015 2.143 78.105 2.413 ;
     RECT  80.715 2.143 80.805 2.413 ;
     RECT  83.415 2.143 83.505 2.413 ;
     RECT  86.115 2.143 86.205 2.413 ;
     RECT  88.815 2.143 88.905 2.413 ;
     RECT  91.515 2.143 91.605 2.413 ;
     RECT  94.215 2.143 94.305 2.413 ;
     RECT  2.415 2.413 2.697 31.729 ;
     RECT  5.115 2.413 5.397 31.729 ;
     RECT  6.552 31.621 6.57 31.729 ;
     RECT  0.144 31.675 0.162 31.771 ;
     RECT  4.068 31.771 4.086 31.801 ;
     RECT  0.144 31.771 0.198 31.819 ;
     RECT  6.552 31.729 7.002 31.867 ;
     RECT  7.815 2.413 8.097 31.867 ;
     RECT  42.915 2.413 43.197 31.891 ;
     RECT  5.004 31.729 5.397 32.035 ;
     RECT  4.068 31.801 4.158 32.071 ;
     RECT  5.004 32.035 5.598 32.071 ;
     RECT  6.552 31.867 8.097 32.071 ;
     RECT  2.415 31.729 3.15 32.099 ;
     RECT  5.004 32.071 5.742 32.161 ;
     RECT  6.552 32.071 8.154 32.161 ;
     RECT  3.996 32.071 4.158 32.269 ;
     RECT  3.96 32.269 4.158 32.299 ;
     RECT  5.004 32.161 8.154 32.299 ;
     RECT  0.108 31.819 0.198 32.369 ;
     RECT  0.144 32.369 0.198 32.429 ;
     RECT  3.96 32.299 8.154 32.443 ;
     RECT  3.456 32.443 8.154 32.467 ;
     RECT  8.964 31.891 8.982 32.467 ;
     RECT  0.144 32.429 0.162 32.717 ;
     RECT  3.456 32.467 8.982 32.737 ;
     RECT  10.515 2.413 10.797 32.809 ;
     RECT  3.456 32.737 9.162 32.827 ;
     RECT  2.415 32.099 2.697 32.971 ;
     RECT  42.228 31.891 43.197 33.007 ;
     RECT  42.12 33.007 43.197 33.043 ;
     RECT  10.515 32.809 10.818 33.071 ;
     RECT  42.012 33.043 43.197 33.115 ;
     RECT  2.304 32.971 2.697 33.151 ;
     RECT  3.42 32.827 9.162 33.151 ;
     RECT  41.724 33.115 43.197 33.151 ;
     RECT  2.304 33.151 9.162 33.269 ;
     RECT  41.724 33.151 43.254 33.269 ;
     RECT  41.724 33.269 43.197 33.385 ;
     RECT  0.108 33.403 0.126 33.449 ;
     RECT  9.288 33.349 9.306 33.449 ;
     RECT  2.304 33.269 8.298 33.691 ;
     RECT  10.515 33.071 10.797 33.889 ;
     RECT  2.268 33.691 8.298 33.917 ;
     RECT  10.515 33.889 10.854 33.989 ;
     RECT  0.54 33.961 0.558 34.589 ;
     RECT  2.415 33.917 8.298 34.591 ;
     RECT  2.415 34.591 8.766 34.619 ;
     RECT  2.415 34.619 2.697 34.699 ;
     RECT  10.515 33.989 10.797 34.969 ;
     RECT  38.772 34.771 38.79 35.005 ;
     RECT  10.515 34.969 10.926 35.069 ;
     RECT  41.544 33.385 43.197 35.203 ;
     RECT  38.772 35.005 38.898 35.267 ;
     RECT  3.456 34.619 8.766 35.311 ;
     RECT  38.772 35.267 38.826 35.339 ;
     RECT  3.456 35.311 9.234 35.572 ;
     RECT  2.304 34.699 2.697 35.609 ;
     RECT  0.108 34.843 0.126 35.851 ;
     RECT  0.108 35.851 0.162 35.969 ;
     RECT  3.42 35.572 9.234 36.121 ;
     RECT  40.215 2.413 40.497 36.121 ;
     RECT  41.508 35.203 43.197 36.121 ;
     RECT  3.42 36.121 9.342 36.239 ;
     RECT  0.108 35.969 0.126 36.317 ;
     RECT  40.215 36.121 43.197 36.617 ;
     RECT  3.42 36.239 8.622 36.851 ;
     RECT  38.772 35.339 38.79 36.887 ;
     RECT  3.492 36.851 8.622 37.121 ;
     RECT  3.492 37.121 8.478 37.931 ;
     RECT  4.752 37.931 8.478 38.039 ;
     RECT  94.215 2.413 94.497 38.101 ;
     RECT  4.752 38.039 6.606 38.129 ;
     RECT  40.215 36.617 40.497 38.209 ;
     RECT  41.508 36.617 43.197 38.209 ;
     RECT  7.344 38.039 8.478 38.237 ;
     RECT  40.215 38.209 43.197 38.309 ;
     RECT  93.492 38.101 94.497 38.551 ;
     RECT  93.456 38.551 94.497 38.641 ;
     RECT  93.456 38.641 95.13 38.713 ;
     RECT  98.244 38.713 98.262 38.785 ;
     RECT  98.172 38.785 98.262 38.813 ;
     RECT  41.508 38.309 43.197 38.821 ;
     RECT  96.912 38.731 96.93 38.821 ;
     RECT  4.752 38.129 6.57 38.849 ;
     RECT  93.456 38.713 95.274 38.911 ;
     RECT  41.508 38.821 43.218 38.939 ;
     RECT  93.456 38.911 95.382 38.947 ;
     RECT  86.115 2.413 86.397 39.019 ;
     RECT  90.576 38.821 90.594 39.019 ;
     RECT  93.168 38.947 95.382 39.019 ;
     RECT  96.336 38.821 96.93 39.019 ;
     RECT  75.315 2.413 75.597 39.091 ;
     RECT  88.815 2.413 89.097 39.091 ;
     RECT  86.115 39.019 86.67 39.119 ;
     RECT  93.168 39.019 96.93 39.181 ;
     RECT  75.315 39.091 75.906 39.209 ;
     RECT  88.815 39.091 89.73 39.209 ;
     RECT  90.504 39.019 90.594 39.209 ;
     RECT  93.024 39.181 96.93 39.209 ;
     RECT  88.815 39.209 89.586 39.293 ;
     RECT  91.515 2.413 91.797 39.325 ;
     RECT  4.752 38.849 5.85 39.355 ;
     RECT  90.648 39.325 91.797 39.361 ;
     RECT  93.024 39.209 95.382 39.389 ;
     RECT  3.492 37.931 3.51 39.551 ;
     RECT  4.5 39.355 5.85 39.631 ;
     RECT  75.315 39.209 75.762 39.631 ;
     RECT  7.344 38.237 8.097 39.659 ;
     RECT  4.176 39.631 5.85 39.773 ;
     RECT  38.772 38.911 38.79 39.857 ;
     RECT  13.215 2.413 13.497 39.865 ;
     RECT  86.115 39.119 86.397 39.901 ;
     RECT  13.215 39.865 13.59 39.917 ;
     RECT  93.024 39.389 95.166 39.991 ;
     RECT  88.815 39.293 89.406 40.019 ;
     RECT  90.648 39.361 92.07 40.019 ;
     RECT  12.024 39.721 12.042 40.061 ;
     RECT  98.172 38.813 98.19 40.061 ;
     RECT  75.24 39.631 75.762 40.171 ;
     RECT  4.752 39.773 5.85 40.199 ;
     RECT  86.115 39.901 86.67 40.261 ;
     RECT  90.684 40.019 92.07 40.261 ;
     RECT  92.988 39.991 95.166 40.261 ;
     RECT  90.684 40.261 95.274 40.315 ;
     RECT  96.3 39.209 96.93 40.315 ;
     RECT  40.215 38.309 40.497 40.567 ;
     RECT  78.015 2.413 78.297 40.567 ;
     RECT  85.752 40.261 86.742 40.595 ;
     RECT  21.315 2.413 21.597 40.603 ;
     RECT  29.415 2.413 29.697 40.603 ;
     RECT  40.215 40.567 40.662 40.603 ;
     RECT  41.508 38.939 43.197 40.603 ;
     RECT  4.752 40.199 5.397 40.631 ;
     RECT  90.684 40.315 96.93 40.637 ;
     RECT  78.015 40.567 78.678 40.667 ;
     RECT  75.24 40.171 75.834 40.711 ;
     RECT  14.832 40.603 14.85 40.733 ;
     RECT  21.315 40.603 21.69 40.733 ;
     RECT  22.824 40.603 22.842 40.733 ;
     RECT  29.415 40.603 29.79 40.733 ;
     RECT  30.78 40.603 30.798 40.733 ;
     RECT  38.772 40.603 38.79 40.739 ;
     RECT  40.215 40.603 43.197 40.787 ;
     RECT  45.615 2.413 45.897 40.787 ;
     RECT  48.315 2.413 48.597 40.787 ;
     RECT  51.015 2.413 51.297 40.787 ;
     RECT  53.715 2.413 53.997 40.787 ;
     RECT  56.415 2.413 56.697 40.787 ;
     RECT  59.115 2.413 59.397 40.787 ;
     RECT  61.815 2.413 62.097 40.787 ;
     RECT  64.515 2.413 64.797 40.787 ;
     RECT  67.215 2.413 67.497 40.787 ;
     RECT  69.915 2.413 70.197 40.787 ;
     RECT  72.615 2.413 72.897 40.787 ;
     RECT  40.215 40.787 43.074 40.801 ;
     RECT  88.815 40.019 89.334 40.801 ;
     RECT  88.815 40.801 89.802 40.837 ;
     RECT  90.684 40.637 94.806 40.837 ;
     RECT  88.815 40.837 94.806 40.937 ;
     RECT  4.284 40.837 4.302 40.981 ;
     RECT  5.112 40.631 5.397 40.981 ;
     RECT  90.324 40.937 94.806 41.009 ;
     RECT  2.415 35.609 2.697 41.035 ;
     RECT  95.76 40.637 96.93 41.035 ;
     RECT  45.615 40.787 45.705 41.057 ;
     RECT  48.315 40.787 48.405 41.057 ;
     RECT  51.015 40.787 51.105 41.057 ;
     RECT  53.715 40.787 53.805 41.057 ;
     RECT  56.415 40.787 56.505 41.057 ;
     RECT  59.115 40.787 59.205 41.057 ;
     RECT  61.815 40.787 61.905 41.057 ;
     RECT  64.515 40.787 64.605 41.057 ;
     RECT  67.215 40.787 67.305 41.057 ;
     RECT  69.915 40.787 70.005 41.057 ;
     RECT  72.615 40.787 72.705 41.057 ;
     RECT  5.112 40.981 6.102 41.071 ;
     RECT  39.996 40.801 43.074 41.083 ;
     RECT  2.304 41.035 2.697 41.099 ;
     RECT  39.816 41.083 43.074 41.107 ;
     RECT  95.76 41.035 96.966 41.173 ;
     RECT  95.76 41.173 97.506 41.213 ;
     RECT  2.415 41.099 2.697 41.215 ;
     RECT  3.996 40.981 4.302 41.215 ;
     RECT  7.815 39.659 8.097 41.251 ;
     RECT  0.108 40.891 0.126 41.323 ;
     RECT  7.815 41.251 8.694 41.341 ;
     RECT  9.468 40.945 9.486 41.341 ;
     RECT  34.815 2.413 35.097 41.341 ;
     RECT  5.112 41.071 6.75 41.369 ;
     RECT  7.815 41.341 9.486 41.369 ;
     RECT  2.415 41.215 4.302 41.413 ;
     RECT  5.112 41.369 5.85 41.413 ;
     RECT  39.708 41.107 43.074 41.413 ;
     RECT  0.108 41.323 0.198 41.453 ;
     RECT  34.776 41.341 35.097 41.477 ;
     RECT  95.76 41.213 96.966 41.501 ;
     RECT  95.76 41.501 95.922 41.521 ;
     RECT  7.815 41.369 9.414 41.549 ;
     RECT  75.168 40.711 76.23 41.645 ;
     RECT  88.815 40.937 89.097 41.683 ;
     RECT  90.324 41.009 94.59 41.683 ;
     RECT  0.108 41.453 0.162 41.741 ;
     RECT  96.876 41.501 96.966 41.783 ;
     RECT  6.696 41.369 6.75 41.881 ;
     RECT  39.384 41.413 43.074 41.881 ;
     RECT  7.815 41.549 8.622 42.025 ;
     RECT  78.015 40.667 78.297 42.025 ;
     RECT  96.912 41.783 96.966 42.043 ;
     RECT  0.108 41.741 0.126 42.089 ;
     RECT  96.912 42.043 97.506 42.089 ;
     RECT  39.348 41.881 43.074 42.151 ;
     RECT  78.015 42.025 78.678 42.179 ;
     RECT  2.415 41.413 5.85 42.187 ;
     RECT  6.696 41.881 6.786 42.187 ;
     RECT  2.415 42.187 6.786 42.221 ;
     RECT  95.364 41.521 95.922 42.221 ;
     RECT  2.415 42.221 5.562 42.331 ;
     RECT  7.776 42.025 8.622 42.331 ;
     RECT  9.396 41.549 9.414 42.331 ;
     RECT  88.815 41.683 94.59 42.331 ;
     RECT  95.364 42.221 95.778 42.331 ;
     RECT  6.48 42.221 6.786 42.449 ;
     RECT  97.488 42.089 97.506 42.475 ;
     RECT  39.24 42.151 43.074 42.529 ;
     RECT  2.268 42.331 5.562 42.629 ;
     RECT  2.268 42.629 3.15 42.653 ;
     RECT  7.524 42.331 9.414 42.719 ;
     RECT  6.552 42.449 6.786 42.727 ;
     RECT  78.015 42.179 78.354 42.727 ;
     RECT  7.815 42.719 9.414 42.763 ;
     RECT  6.552 42.727 7.002 42.797 ;
     RECT  7.815 42.763 9.45 42.871 ;
     RECT  38.844 42.529 43.074 42.871 ;
     RECT  82.656 42.835 82.674 42.871 ;
     RECT  97.488 42.475 97.542 42.907 ;
     RECT  80.715 2.413 80.997 42.961 ;
     RECT  88.815 42.331 95.778 43.051 ;
     RECT  97.488 42.907 97.614 43.097 ;
     RECT  77.868 42.727 78.354 43.105 ;
     RECT  7.815 42.871 9.522 43.133 ;
     RECT  38.772 42.871 43.074 43.133 ;
     RECT  88.815 43.051 95.994 43.133 ;
     RECT  82.476 42.871 82.674 43.169 ;
     RECT  39.024 43.133 43.074 43.2 ;
     RECT  75.24 41.645 76.23 43.2 ;
     RECT  0.54 43.141 0.558 43.229 ;
     RECT  6.624 42.797 7.002 43.259 ;
     RECT  88.815 43.133 95.922 43.259 ;
     RECT  88.815 43.259 95.778 43.331 ;
     RECT  3.96 42.629 5.562 43.339 ;
     RECT  10.515 35.069 10.797 43.375 ;
     RECT  3.96 43.339 5.598 43.411 ;
     RECT  6.66 43.259 7.002 43.501 ;
     RECT  7.815 43.133 9.162 43.501 ;
     RECT  0.144 43.387 0.162 43.517 ;
     RECT  6.66 43.501 9.162 43.529 ;
     RECT  97.488 43.097 97.506 43.601 ;
     RECT  9.072 43.529 9.162 43.637 ;
     RECT  82.476 43.169 82.602 43.681 ;
     RECT  85.752 40.595 86.49 43.681 ;
     RECT  6.66 43.529 8.298 43.709 ;
     RECT  10.515 43.375 10.854 43.709 ;
     RECT  2.415 42.653 3.15 43.771 ;
     RECT  82.116 43.681 82.602 43.799 ;
     RECT  88.815 43.331 95.742 43.799 ;
     RECT  3.96 43.411 5.886 43.835 ;
     RECT  80.715 42.961 81.126 43.843 ;
     RECT  6.66 43.709 8.226 43.979 ;
     RECT  2.415 43.771 3.222 44.041 ;
     RECT  39.024 43.2 76.23 44.041 ;
     RECT  88.815 43.799 95.706 44.069 ;
     RECT  83.415 2.413 83.697 44.155 ;
     RECT  38.772 44.041 76.23 44.177 ;
     RECT  2.415 44.041 3.33 44.203 ;
     RECT  2.304 44.203 3.33 44.249 ;
     RECT  88.815 44.069 95.202 44.249 ;
     RECT  0.108 43.771 0.126 44.411 ;
     RECT  83.415 44.155 84.33 44.443 ;
     RECT  4.14 43.835 5.886 44.491 ;
     RECT  6.66 43.979 6.966 44.491 ;
     RECT  7.815 43.979 8.226 44.491 ;
     RECT  85.752 43.681 86.526 44.491 ;
     RECT  9.144 43.637 9.162 44.519 ;
     RECT  7.815 44.491 8.262 44.581 ;
     RECT  77.22 43.105 78.354 44.581 ;
     RECT  77.22 44.581 78.39 44.587 ;
     RECT  79.488 41.449 79.506 44.587 ;
     RECT  83.415 44.443 84.402 44.683 ;
     RECT  77.22 44.587 79.506 44.717 ;
     RECT  83.415 44.683 84.51 44.717 ;
     RECT  85.752 44.491 86.706 44.717 ;
     RECT  7.815 44.581 8.586 44.789 ;
     RECT  85.752 44.717 86.67 44.789 ;
     RECT  2.415 44.249 3.33 44.851 ;
     RECT  4.14 44.491 6.966 44.851 ;
     RECT  0.144 44.779 0.162 44.909 ;
     RECT  84.492 44.717 84.51 44.909 ;
     RECT  2.415 44.851 6.966 44.923 ;
     RECT  7.815 44.789 8.55 44.923 ;
     RECT  2.415 44.923 8.55 44.96 ;
     RECT  88.815 44.249 94.914 44.995 ;
     RECT  82.584 43.799 82.602 45.019 ;
     RECT  2.415 44.96 2.79 45.059 ;
     RECT  3.6 44.96 8.55 45.059 ;
     RECT  79.488 44.717 79.506 45.149 ;
     RECT  3.6 45.059 6.03 45.185 ;
     RECT  82.584 45.019 82.674 45.197 ;
     RECT  39.024 44.177 76.23 45.301 ;
     RECT  2.415 45.059 2.697 45.355 ;
     RECT  2.304 45.355 2.697 45.419 ;
     RECT  3.744 45.185 6.03 45.419 ;
     RECT  34.815 41.477 35.097 45.427 ;
     RECT  6.948 45.059 8.55 45.455 ;
     RECT  34.776 45.427 35.097 45.563 ;
     RECT  7.092 45.455 8.55 45.571 ;
     RECT  3.744 45.419 5.562 45.599 ;
     RECT  7.092 45.571 9.126 45.689 ;
     RECT  38.808 45.301 76.23 45.725 ;
     RECT  85.752 44.789 86.49 45.739 ;
     RECT  7.815 45.689 8.55 45.761 ;
     RECT  3.744 45.599 5.397 45.797 ;
     RECT  38.808 45.725 76.122 45.833 ;
     RECT  3.996 45.797 5.397 45.869 ;
     RECT  82.584 45.197 82.602 45.979 ;
     RECT  39.024 45.833 76.122 46.109 ;
     RECT  82.584 45.979 82.674 46.109 ;
     RECT  77.22 44.717 78.678 46.111 ;
     RECT  7.815 45.761 8.262 46.229 ;
     RECT  85.752 45.739 86.67 46.471 ;
     RECT  88.815 44.995 95.454 46.679 ;
     RECT  76.932 46.111 78.678 46.747 ;
     RECT  4.14 45.869 5.397 46.769 ;
     RECT  4.14 46.769 4.158 46.805 ;
     RECT  39.024 46.109 75.69 46.805 ;
     RECT  82.584 46.109 82.602 46.829 ;
     RECT  90.684 46.679 94.554 46.841 ;
     RECT  76.932 46.747 78.894 46.877 ;
     RECT  85.464 46.471 86.67 46.877 ;
     RECT  90.684 46.841 94.497 46.913 ;
     RECT  88.815 46.679 89.91 47.069 ;
     RECT  85.464 46.877 86.454 47.165 ;
     RECT  76.932 46.877 78.822 47.213 ;
     RECT  76.932 47.213 78.39 47.219 ;
     RECT  90.9 46.913 94.497 47.219 ;
     RECT  90.9 47.219 92.646 47.345 ;
     RECT  88.815 47.069 89.478 47.357 ;
     RECT  88.815 47.357 89.406 47.453 ;
     RECT  80.715 43.843 81.234 47.645 ;
     RECT  39.492 46.805 75.69 47.933 ;
     RECT  39.492 47.933 75.582 48.029 ;
     RECT  76.932 47.219 78.297 48.127 ;
     RECT  39.492 48.029 75.474 48.221 ;
     RECT  93.564 47.219 94.497 48.361 ;
     RECT  93.456 48.361 94.497 48.427 ;
     RECT  95.436 46.679 95.454 48.427 ;
     RECT  93.456 48.427 95.454 48.467 ;
     RECT  76.32 48.127 78.297 48.605 ;
     RECT  93.456 48.467 94.497 48.701 ;
     RECT  39.564 48.221 75.474 48.811 ;
     RECT  76.32 48.605 76.338 48.811 ;
     RECT  39.564 48.811 76.338 49.339 ;
     RECT  39.564 49.339 76.41 49.565 ;
     RECT  39.78 49.565 76.41 50.045 ;
     RECT  43.2 50.045 76.41 50.237 ;
     RECT  39.78 50.045 42.174 50.359 ;
     RECT  93.564 48.701 94.497 50.819 ;
     RECT  38.88 50.359 42.174 50.923 ;
     RECT  37.515 2.413 37.797 50.935 ;
     RECT  38.808 50.923 42.174 50.935 ;
     RECT  37.515 50.935 42.174 51.125 ;
     RECT  38.772 51.125 42.174 51.241 ;
     RECT  38.772 51.241 42.21 51.781 ;
     RECT  38.772 51.781 42.462 51.931 ;
     RECT  43.2 50.237 75.192 51.931 ;
     RECT  95.436 48.467 95.454 51.943 ;
     RECT  37.515 51.125 37.797 52.051 ;
     RECT  38.772 51.931 75.192 52.051 ;
     RECT  90.9 47.345 92.466 52.051 ;
     RECT  93.636 50.819 94.497 52.051 ;
     RECT  37.515 52.051 75.192 52.109 ;
     RECT  95.436 51.943 95.778 52.141 ;
     RECT  77.22 48.605 78.297 52.241 ;
     RECT  95.364 52.141 95.778 52.285 ;
     RECT  95.364 52.285 95.994 52.321 ;
     RECT  90.9 52.051 94.497 52.363 ;
     RECT  95.364 52.321 96.354 52.363 ;
     RECT  90.9 52.363 96.354 52.589 ;
     RECT  90.9 52.589 95.778 52.591 ;
     RECT  90.684 52.591 95.778 52.681 ;
     RECT  90.504 52.681 95.778 52.789 ;
     RECT  76.392 50.237 76.41 52.825 ;
     RECT  38.916 52.109 75.192 52.861 ;
     RECT  90.432 52.789 95.778 52.889 ;
     RECT  76.392 52.825 76.446 53.015 ;
     RECT  38.772 52.861 75.51 53.083 ;
     RECT  96.912 52.789 96.93 53.275 ;
     RECT  90.468 52.889 95.454 53.357 ;
     RECT  86.115 47.165 86.454 53.365 ;
     RECT  77.4 52.241 78.297 53.371 ;
     RECT  38.772 53.083 75.834 53.519 ;
     RECT  76.968 53.371 78.297 53.555 ;
     RECT  37.515 52.109 37.797 53.563 ;
     RECT  39.096 53.519 75.834 53.663 ;
     RECT  95.364 53.357 95.454 53.707 ;
     RECT  39.096 53.663 39.15 53.789 ;
     RECT  39.996 53.663 75.834 53.789 ;
     RECT  90.468 53.357 94.554 53.869 ;
     RECT  90.396 53.869 94.554 53.941 ;
     RECT  88.815 47.453 89.097 54.091 ;
     RECT  90.324 53.941 94.554 54.091 ;
     RECT  88.815 54.091 89.298 54.131 ;
     RECT  96.912 53.275 97.506 54.131 ;
     RECT  90.288 54.091 94.554 54.301 ;
     RECT  95.364 53.707 95.922 54.301 ;
     RECT  97.488 54.131 97.506 54.427 ;
     RECT  90.288 54.301 95.922 54.437 ;
     RECT  37.515 53.563 38.214 54.445 ;
     RECT  39.096 53.789 39.114 54.445 ;
     RECT  95.436 54.437 95.922 54.481 ;
     RECT  37.515 54.445 39.114 54.599 ;
     RECT  95.436 54.481 95.994 54.599 ;
     RECT  38.52 54.599 39.114 54.715 ;
     RECT  38.52 54.715 39.15 54.743 ;
     RECT  38.7 54.743 39.15 54.869 ;
     RECT  38.7 54.869 38.97 54.905 ;
     RECT  39.996 53.789 75.726 54.985 ;
     RECT  96.3 54.859 96.318 55.003 ;
     RECT  97.488 54.427 97.542 55.003 ;
     RECT  88.815 54.131 89.097 55.021 ;
     RECT  88.815 55.021 89.37 55.139 ;
     RECT  90.288 54.437 94.497 55.147 ;
     RECT  96.3 55.003 97.542 55.481 ;
     RECT  39.996 54.985 76.086 55.489 ;
     RECT  96.336 55.481 97.542 55.517 ;
     RECT  86.115 53.365 86.67 55.525 ;
     RECT  86.115 55.525 86.706 55.679 ;
     RECT  88.815 55.139 89.298 55.679 ;
     RECT  76.968 53.555 77.238 55.715 ;
     RECT  90.144 55.147 94.497 55.723 ;
     RECT  95.436 54.599 95.454 55.723 ;
     RECT  96.336 55.517 97.506 55.751 ;
     RECT  90.144 55.723 95.454 55.831 ;
     RECT  90.036 55.831 95.454 56.101 ;
     RECT  96.336 55.751 96.93 56.299 ;
     RECT  89.856 56.101 95.454 56.429 ;
     RECT  86.115 55.679 86.454 56.489 ;
     RECT  96.3 56.299 96.93 56.669 ;
     RECT  90.108 56.429 95.454 56.731 ;
     RECT  96.3 56.669 96.318 56.731 ;
     RECT  90.108 56.731 96.318 56.759 ;
     RECT  92.808 56.759 96.318 56.831 ;
     RECT  90.108 56.759 91.854 56.903 ;
     RECT  97.488 56.869 97.506 56.909 ;
     RECT  90.108 56.903 91.797 56.939 ;
     RECT  92.988 56.831 96.318 57.029 ;
     RECT  95.76 57.029 96.318 57.137 ;
     RECT  96.3 57.137 96.318 57.209 ;
     RECT  92.988 57.029 94.734 57.299 ;
     RECT  39.996 55.489 76.23 60.504 ;
     RECT  77.22 55.715 77.238 61.037 ;
     RECT  92.988 57.299 94.698 61.079 ;
     RECT  92.988 61.079 94.497 61.115 ;
     RECT  92.988 61.115 93.186 61.151 ;
     RECT  75.204 60.504 76.23 61.259 ;
     RECT  75.204 61.259 76.158 61.385 ;
     RECT  76.068 61.385 76.158 61.421 ;
     RECT  39.996 60.504 42.75 61.457 ;
     RECT  76.068 61.421 76.086 61.457 ;
     RECT  93.168 61.151 93.186 61.619 ;
     RECT  41.292 61.457 42.75 61.655 ;
     RECT  90.144 56.939 91.797 61.655 ;
     RECT  75.204 61.385 75.33 62.473 ;
     RECT  49.86 62.437 49.878 62.509 ;
     RECT  46.764 62.437 46.782 62.573 ;
     RECT  41.58 61.655 42.75 62.609 ;
     RECT  74.664 62.473 75.33 62.609 ;
     RECT  50.724 62.509 50.742 62.623 ;
     RECT  75.204 62.609 75.33 62.623 ;
     RECT  49.176 62.509 49.878 62.699 ;
     RECT  50.724 62.623 51.105 62.699 ;
     RECT  90.144 61.655 90.162 62.699 ;
     RECT  42.915 62.623 43.005 62.893 ;
     RECT  45.615 62.623 45.705 62.893 ;
     RECT  48.315 62.623 48.405 62.893 ;
     RECT  51.015 62.699 51.105 62.893 ;
     RECT  53.715 62.623 53.805 62.893 ;
     RECT  56.415 62.623 56.505 62.893 ;
     RECT  59.115 62.623 59.205 62.893 ;
     RECT  61.815 62.623 61.905 62.893 ;
     RECT  64.515 62.623 64.605 62.893 ;
     RECT  67.215 62.623 67.305 62.893 ;
     RECT  69.915 62.623 70.005 62.893 ;
     RECT  72.615 62.623 72.705 62.893 ;
     RECT  75.204 62.623 75.405 62.893 ;
     RECT  75.204 62.893 75.597 62.969 ;
     RECT  75.24 62.969 75.597 63.041 ;
     RECT  42.915 62.893 43.197 64.561 ;
     RECT  42.915 64.561 43.542 64.859 ;
     RECT  42.915 64.859 43.326 64.973 ;
     RECT  77.184 73.723 77.202 73.769 ;
     RECT  76.86 73.813 76.878 74.309 ;
     RECT  5.115 46.769 5.397 74.389 ;
     RECT  7.815 46.229 8.097 74.389 ;
     RECT  2.415 45.419 2.697 74.425 ;
     RECT  5.115 74.389 6.03 74.443 ;
     RECT  2.304 74.425 2.697 74.461 ;
     RECT  7.704 74.389 8.097 74.461 ;
     RECT  2.304 74.461 3.33 74.551 ;
     RECT  4.392 74.443 6.03 74.551 ;
     RECT  7.128 74.461 8.097 74.651 ;
     RECT  13.215 39.917 13.497 74.683 ;
     RECT  2.304 74.551 6.246 74.731 ;
     RECT  9.396 74.551 9.414 74.849 ;
     RECT  13.215 74.683 13.734 74.849 ;
     RECT  2.268 74.731 6.246 74.909 ;
     RECT  10.515 43.709 10.797 74.929 ;
     RECT  37.515 54.599 37.797 74.929 ;
     RECT  38.7 54.905 38.718 74.929 ;
     RECT  7.815 74.651 8.097 74.965 ;
     RECT  0.108 74.299 0.126 75.019 ;
     RECT  0.108 75.019 0.162 75.029 ;
     RECT  0.144 75.029 0.162 75.149 ;
     RECT  2.415 74.909 6.246 75.397 ;
     RECT  7.02 74.965 7.038 75.397 ;
     RECT  37.515 74.929 38.718 75.505 ;
     RECT  10.515 74.929 10.854 75.541 ;
     RECT  0.54 75.541 0.558 75.629 ;
     RECT  2.415 75.397 7.038 75.659 ;
     RECT  2.415 75.659 6.75 75.821 ;
     RECT  34.815 45.563 35.097 75.901 ;
     RECT  7.815 74.965 8.262 76.073 ;
     RECT  3.456 75.821 6.75 76.549 ;
     RECT  7.815 76.073 8.154 76.549 ;
     RECT  37.515 75.505 39.042 76.621 ;
     RECT  9.144 75.091 9.162 76.649 ;
     RECT  10.515 75.541 10.89 76.891 ;
     RECT  0.108 75.883 0.162 76.919 ;
     RECT  2.415 75.821 2.697 76.939 ;
     RECT  3.456 76.549 8.154 76.939 ;
     RECT  2.415 76.939 8.154 76.981 ;
     RECT  39.996 61.457 40.497 77.251 ;
     RECT  9.936 76.891 10.89 77.279 ;
     RECT  2.415 76.981 8.262 77.323 ;
     RECT  2.304 77.323 8.262 77.729 ;
     RECT  9.144 77.935 9.162 77.971 ;
     RECT  0.144 76.919 0.162 78.331 ;
     RECT  37.515 76.621 39.15 78.367 ;
     RECT  39.996 77.251 40.554 78.367 ;
     RECT  2.415 77.729 8.262 78.511 ;
     RECT  9.108 77.971 9.162 78.511 ;
     RECT  9.936 77.279 10.797 78.511 ;
     RECT  0.108 78.331 0.162 78.539 ;
     RECT  9.108 78.511 10.797 78.629 ;
     RECT  0.144 78.539 0.162 78.653 ;
     RECT  2.415 78.511 8.37 78.745 ;
     RECT  2.415 78.745 8.442 78.763 ;
     RECT  2.304 78.763 8.442 78.809 ;
     RECT  2.415 78.809 8.442 78.971 ;
     RECT  2.415 78.971 8.406 79.169 ;
     RECT  2.415 79.169 8.097 80.087 ;
     RECT  37.515 78.367 40.554 80.635 ;
     RECT  94.215 61.115 94.497 80.905 ;
     RECT  94.215 80.905 95.094 80.941 ;
     RECT  94.215 80.941 95.382 81.211 ;
     RECT  2.415 80.087 3.582 81.239 ;
     RECT  96.3 81.355 96.318 81.401 ;
     RECT  91.515 61.655 91.797 81.481 ;
     RECT  93.384 81.481 93.402 81.607 ;
     RECT  94.176 81.211 95.382 81.607 ;
     RECT  90.144 81.715 90.162 81.751 ;
     RECT  91.515 81.481 92.034 81.751 ;
     RECT  88.815 55.679 89.097 81.835 ;
     RECT  93.384 81.607 95.382 81.841 ;
     RECT  90.144 81.751 90.414 81.869 ;
     RECT  90.396 81.869 90.414 81.949 ;
     RECT  88.815 81.835 89.19 82.019 ;
     RECT  75.315 63.041 75.597 82.021 ;
     RECT  90.396 81.949 90.666 82.183 ;
     RECT  91.476 81.751 92.034 82.183 ;
     RECT  93.132 81.841 95.382 82.219 ;
     RECT  93.132 82.219 95.706 82.255 ;
     RECT  97.488 81.643 97.506 82.507 ;
     RECT  90.396 82.183 92.034 82.525 ;
     RECT  90.396 82.525 92.286 82.561 ;
     RECT  93.132 82.255 95.814 82.561 ;
     RECT  90.396 82.561 95.814 82.637 ;
     RECT  82.08 82.417 82.098 82.679 ;
     RECT  88.815 82.019 89.097 82.699 ;
     RECT  90.612 82.637 95.814 82.787 ;
     RECT  75.315 82.021 75.69 82.831 ;
     RECT  2.415 81.239 3.438 82.949 ;
     RECT  90.648 82.787 95.814 83.065 ;
     RECT  37.515 80.635 40.734 83.101 ;
     RECT  41.58 62.609 42.174 83.101 ;
     RECT  88.74 82.699 89.097 83.219 ;
     RECT  89.82 83.065 89.838 83.219 ;
     RECT  90.648 83.065 95.994 83.219 ;
     RECT  13.215 74.849 13.497 83.533 ;
     RECT  22.5 78.871 22.518 83.561 ;
     RECT  30.456 74.623 30.474 83.597 ;
     RECT  37.515 83.101 42.174 83.605 ;
     RECT  42.915 64.973 43.197 83.605 ;
     RECT  74.952 82.831 75.69 83.605 ;
     RECT  37.515 83.605 43.254 83.659 ;
     RECT  74.952 83.605 75.726 83.767 ;
     RECT  90.648 83.219 95.922 83.767 ;
     RECT  45.615 62.893 45.897 83.987 ;
     RECT  48.315 62.893 48.597 83.987 ;
     RECT  51.015 62.893 51.297 83.987 ;
     RECT  53.715 62.893 53.997 83.987 ;
     RECT  56.415 62.893 56.697 83.987 ;
     RECT  59.115 62.893 59.397 83.987 ;
     RECT  61.815 62.893 62.097 83.987 ;
     RECT  64.515 62.893 64.797 83.987 ;
     RECT  67.215 62.893 67.497 83.987 ;
     RECT  69.915 62.893 70.197 83.987 ;
     RECT  72.615 62.893 72.897 83.987 ;
     RECT  66.276 84.073 66.294 84.125 ;
     RECT  74.952 83.767 75.798 84.136 ;
     RECT  83.415 44.717 83.697 84.139 ;
     RECT  74.952 84.136 76.014 84.181 ;
     RECT  76.752 82.561 76.77 84.181 ;
     RECT  37.515 83.659 43.542 84.209 ;
     RECT  96.912 82.507 97.506 84.209 ;
     RECT  90.18 83.767 95.922 84.221 ;
     RECT  45.615 83.987 45.705 84.257 ;
     RECT  48.315 83.987 48.405 84.257 ;
     RECT  51.015 83.987 51.105 84.257 ;
     RECT  53.715 83.987 53.805 84.257 ;
     RECT  56.415 83.987 56.505 84.257 ;
     RECT  59.115 83.987 59.205 84.257 ;
     RECT  61.815 83.987 61.905 84.257 ;
     RECT  64.515 83.987 64.746 84.257 ;
     RECT  67.215 83.987 67.305 84.257 ;
     RECT  69.915 83.987 70.005 84.257 ;
     RECT  72.615 83.987 72.705 84.257 ;
     RECT  88.815 83.219 89.097 84.271 ;
     RECT  83.415 84.139 83.718 84.299 ;
     RECT  90.612 84.221 95.922 84.299 ;
     RECT  37.515 84.209 43.218 84.365 ;
     RECT  64.728 84.257 64.746 84.365 ;
     RECT  97.488 84.209 97.506 84.379 ;
     RECT  97.488 84.379 97.542 84.479 ;
     RECT  4.5 80.087 8.097 84.721 ;
     RECT  0.54 84.667 0.558 84.749 ;
     RECT  2.415 82.949 3.222 84.811 ;
     RECT  2.304 84.811 3.222 84.847 ;
     RECT  3.96 84.721 8.097 84.847 ;
     RECT  2.304 84.847 8.097 84.848 ;
     RECT  74.952 84.181 76.77 85.081 ;
     RECT  78.015 53.555 78.297 85.081 ;
     RECT  88.815 84.271 89.874 85.081 ;
     RECT  90.756 84.299 95.922 85.081 ;
     RECT  88.815 85.081 95.922 85.099 ;
     RECT  2.415 84.848 8.097 85.225 ;
     RECT  9.396 78.629 10.797 85.225 ;
     RECT  78.015 85.081 78.678 85.289 ;
     RECT  2.415 85.225 8.19 85.351 ;
     RECT  9.252 85.225 10.797 85.351 ;
     RECT  85.32 85.117 85.338 85.379 ;
     RECT  88.815 85.099 96.318 85.451 ;
     RECT  97.488 84.479 97.506 85.675 ;
     RECT  0.324 85.243 0.342 85.709 ;
     RECT  96.912 85.675 97.506 85.757 ;
     RECT  83.415 84.299 83.697 85.801 ;
     RECT  86.115 56.489 86.397 85.801 ;
     RECT  87.48 83.029 87.498 85.801 ;
     RECT  83.124 85.801 83.697 85.919 ;
     RECT  88.815 85.451 95.922 85.919 ;
     RECT  78.015 85.289 78.297 86.011 ;
     RECT  74.952 85.081 77.238 86.035 ;
     RECT  78.015 86.011 78.93 86.035 ;
     RECT  88.815 85.919 95.814 86.063 ;
     RECT  2.415 85.351 10.797 86.395 ;
     RECT  37.515 84.365 43.074 86.4 ;
     RECT  74.952 86.035 78.93 86.4 ;
     RECT  90.684 86.063 95.814 86.459 ;
     RECT  86.115 85.801 87.498 86.495 ;
     RECT  96.912 85.757 96.93 86.531 ;
     RECT  87.228 86.495 87.498 86.576 ;
     RECT  82.332 86.539 82.35 86.611 ;
     RECT  82.332 86.611 82.422 86.639 ;
     RECT  34.815 75.901 35.622 86.999 ;
     RECT  90.684 86.459 95.526 87.143 ;
     RECT  88.815 86.063 89.874 87.151 ;
     RECT  90.684 87.143 95.13 87.151 ;
     RECT  83.232 85.919 83.697 87.355 ;
     RECT  88.815 87.151 95.13 87.449 ;
     RECT  0.108 85.819 0.126 87.719 ;
     RECT  90.684 87.449 95.13 87.917 ;
     RECT  86.115 86.495 86.397 88.123 ;
     RECT  88.815 87.449 89.874 88.123 ;
     RECT  37.515 86.4 78.93 88.157 ;
     RECT  90.9 87.917 95.13 88.157 ;
     RECT  91.224 88.157 95.13 88.223 ;
     RECT  13.215 83.533 13.95 88.529 ;
     RECT  43.2 88.157 78.93 88.541 ;
     RECT  88.704 88.123 89.874 88.589 ;
     RECT  86.115 88.123 86.67 88.603 ;
     RECT  87.48 86.576 87.498 88.603 ;
     RECT  2.304 86.395 10.797 88.619 ;
     RECT  37.515 88.157 42.282 88.733 ;
     RECT  86.115 88.603 87.498 88.733 ;
     RECT  36.756 80.671 36.774 88.763 ;
     RECT  87.48 88.733 87.498 88.781 ;
     RECT  0.144 88.171 0.162 88.877 ;
     RECT  91.224 88.223 94.842 88.973 ;
     RECT  88.815 88.589 89.874 89.021 ;
     RECT  86.115 88.733 86.67 89.069 ;
     RECT  37.515 88.733 42.246 89.213 ;
     RECT  0.108 89.131 0.126 89.261 ;
     RECT  86.115 89.069 86.397 89.437 ;
     RECT  43.2 88.541 76.122 89.693 ;
     RECT  86.04 89.437 86.397 89.741 ;
     RECT  91.476 88.973 94.842 89.789 ;
     RECT  91.476 89.789 92.358 89.807 ;
     RECT  93.168 89.789 94.842 89.807 ;
     RECT  86.115 89.741 86.397 89.947 ;
     RECT  93.168 89.807 94.734 89.969 ;
     RECT  90.648 89.707 90.666 89.981 ;
     RECT  77.22 88.541 78.93 90.173 ;
     RECT  91.476 89.807 92.322 90.269 ;
     RECT  37.515 89.213 42.21 90.283 ;
     RECT  83.232 87.355 83.754 90.317 ;
     RECT  88.815 89.021 89.838 90.319 ;
     RECT  88.815 90.319 90.054 90.365 ;
     RECT  91.476 90.269 92.286 90.557 ;
     RECT  91.476 90.557 91.797 90.589 ;
     RECT  88.815 90.365 89.838 90.653 ;
     RECT  86.115 89.947 86.49 90.763 ;
     RECT  82.404 86.639 82.422 90.845 ;
     RECT  86.115 90.763 86.67 90.893 ;
     RECT  91.188 90.589 91.797 90.893 ;
     RECT  43.2 89.693 75.762 90.931 ;
     RECT  2.415 88.619 10.797 90.959 ;
     RECT  34.815 86.999 35.097 91.201 ;
     RECT  2.415 90.959 8.838 91.229 ;
     RECT  43.2 90.931 76.374 91.325 ;
     RECT  77.796 90.173 78.93 91.327 ;
     RECT  37.515 90.283 42.246 91.363 ;
     RECT  43.2 91.325 75.618 91.363 ;
     RECT  37.515 91.363 75.618 91.613 ;
     RECT  9.936 90.959 10.797 91.661 ;
     RECT  37.515 91.613 75.546 91.805 ;
     RECT  76.356 91.325 76.374 91.867 ;
     RECT  77.508 91.327 78.93 91.867 ;
     RECT  2.415 91.229 5.814 91.967 ;
     RECT  76.356 91.867 78.93 92.093 ;
     RECT  6.66 91.229 8.838 92.129 ;
     RECT  37.515 91.805 75.192 92.669 ;
     RECT  34.776 91.201 35.097 92.849 ;
     RECT  76.932 92.093 78.93 92.861 ;
     RECT  2.415 91.967 4.158 93.047 ;
     RECT  6.66 92.129 8.097 93.083 ;
     RECT  4.896 91.967 5.814 93.119 ;
     RECT  22.464 93.163 22.482 93.209 ;
     RECT  37.515 92.669 42.21 93.245 ;
     RECT  21.315 40.733 21.597 93.289 ;
     RECT  21.315 93.289 22.122 93.341 ;
     RECT  91.515 90.893 91.797 93.403 ;
     RECT  93.168 89.969 94.497 93.403 ;
     RECT  2.415 93.047 3.618 93.479 ;
     RECT  91.515 93.403 94.497 93.479 ;
     RECT  2.415 93.479 3.582 93.515 ;
     RECT  37.515 93.245 42.174 93.533 ;
     RECT  6.66 93.083 6.678 93.551 ;
     RECT  43.2 92.669 75.192 93.835 ;
     RECT  38.628 93.533 42.174 93.869 ;
     RECT  38.7 93.869 42.174 93.991 ;
     RECT  43.092 93.835 75.192 93.991 ;
     RECT  76.392 93.019 76.41 93.991 ;
     RECT  77.58 92.861 78.93 93.991 ;
     RECT  43.092 93.991 76.41 94.013 ;
     RECT  91.515 93.479 92.322 94.061 ;
     RECT  3.564 93.515 3.582 94.091 ;
     RECT  77.436 93.991 78.93 94.199 ;
     RECT  43.2 94.013 76.41 94.205 ;
     RECT  8.82 92.129 8.838 94.361 ;
     RECT  77.58 94.199 78.93 94.595 ;
     RECT  38.7 93.991 42.21 94.603 ;
     RECT  37.515 93.533 37.797 94.651 ;
     RECT  38.664 94.603 42.21 94.651 ;
     RECT  37.515 94.651 42.21 94.685 ;
     RECT  76.356 94.205 76.41 94.685 ;
     RECT  43.2 94.205 75.192 95.131 ;
     RECT  5.115 93.119 5.814 95.171 ;
     RECT  37.515 94.685 42.174 95.515 ;
     RECT  43.092 95.131 75.192 95.515 ;
     RECT  37.515 95.515 75.192 95.711 ;
     RECT  77.616 94.595 78.93 95.803 ;
     RECT  91.515 94.061 91.797 95.881 ;
     RECT  93.168 93.479 94.497 96.061 ;
     RECT  95.364 95.881 95.382 96.061 ;
     RECT  96.948 96.025 96.966 96.061 ;
     RECT  77.58 95.803 78.93 96.089 ;
     RECT  77.58 96.089 78.297 96.091 ;
     RECT  91.224 95.881 91.797 96.151 ;
     RECT  77.436 96.091 78.297 96.187 ;
     RECT  90.648 96.151 91.797 96.187 ;
     RECT  76.392 94.685 76.41 96.215 ;
     RECT  90.648 96.187 91.854 96.223 ;
     RECT  38.52 95.711 75.192 96.259 ;
     RECT  77.4 96.187 78.297 96.295 ;
     RECT  88.815 90.653 89.766 96.331 ;
     RECT  90.648 96.223 92.358 96.331 ;
     RECT  38.52 96.259 75.87 96.413 ;
     RECT  93.168 96.061 95.382 96.521 ;
     RECT  88.815 96.331 92.358 96.719 ;
     RECT  38.52 96.413 75.834 96.827 ;
     RECT  38.52 96.827 38.718 96.893 ;
     RECT  88.815 96.719 91.854 96.893 ;
     RECT  96.336 96.061 96.966 96.907 ;
     RECT  96.3 96.907 96.966 97.051 ;
     RECT  96.3 97.051 97.506 97.061 ;
     RECT  93.168 96.521 95.202 97.105 ;
     RECT  92.664 97.105 95.202 97.259 ;
     RECT  92.7 97.259 95.202 97.411 ;
     RECT  92.7 97.411 95.274 97.483 ;
     RECT  92.7 97.483 95.814 97.529 ;
     RECT  92.7 97.529 95.274 97.601 ;
     RECT  90.648 96.893 91.854 97.609 ;
     RECT  90.648 97.609 91.926 97.951 ;
     RECT  90.504 97.951 91.962 98.041 ;
     RECT  92.7 97.601 95.202 98.041 ;
     RECT  39.456 96.827 75.834 98.149 ;
     RECT  88.815 96.893 89.766 98.185 ;
     RECT  90.504 98.041 95.202 98.185 ;
     RECT  86.115 90.893 86.397 98.419 ;
     RECT  86.115 98.419 86.67 98.519 ;
     RECT  96.912 97.061 97.506 98.519 ;
     RECT  88.815 98.185 95.202 98.851 ;
     RECT  96.336 98.581 96.354 98.851 ;
     RECT  39.456 98.149 76.122 98.923 ;
     RECT  77.22 96.295 78.297 98.923 ;
     RECT  97.488 98.519 97.506 98.923 ;
     RECT  97.488 98.923 97.542 98.987 ;
     RECT  88.815 98.851 96.354 99.149 ;
     RECT  39.456 98.923 78.297 99.455 ;
     RECT  90.9 99.149 96.354 99.677 ;
     RECT  83.415 90.317 83.754 99.689 ;
     RECT  88.815 99.149 89.982 99.697 ;
     RECT  97.488 98.987 97.506 99.787 ;
     RECT  88.344 99.697 89.982 99.833 ;
     RECT  22.428 99.739 22.446 99.959 ;
     RECT  21.315 93.341 21.597 99.967 ;
     RECT  21.315 99.967 22.122 100.013 ;
     RECT  96.912 99.787 97.506 100.031 ;
     RECT  88.815 99.833 89.982 100.229 ;
     RECT  90.9 99.677 95.922 100.265 ;
     RECT  86.115 98.519 86.397 100.651 ;
     RECT  90.9 100.265 95.778 100.651 ;
     RECT  85.572 100.651 86.397 100.769 ;
     RECT  89.856 100.229 89.982 100.769 ;
     RECT  90.792 100.651 95.778 100.769 ;
     RECT  90.9 100.769 95.778 100.949 ;
     RECT  96.912 100.031 96.966 101.111 ;
     RECT  96.912 101.111 96.93 101.381 ;
     RECT  39.456 99.455 77.238 103.704 ;
     RECT  90.9 100.949 95.058 103.811 ;
     RECT  93.6 103.811 95.058 103.847 ;
     RECT  89.964 100.769 89.982 103.883 ;
     RECT  74.664 103.704 77.238 103.919 ;
     RECT  74.664 103.919 76.158 103.964 ;
     RECT  94.176 103.847 95.058 104.333 ;
     RECT  94.176 104.333 94.497 104.351 ;
     RECT  77.22 103.919 77.238 104.381 ;
     RECT  90.9 103.811 92.862 104.387 ;
     RECT  90.9 104.387 92.79 104.423 ;
     RECT  92.52 104.423 92.79 104.927 ;
     RECT  90.9 104.423 91.797 105.161 ;
     RECT  47.7 105.133 47.718 105.709 ;
     RECT  75.204 103.964 76.158 105.737 ;
     RECT  51.156 105.673 51.174 105.745 ;
     RECT  50.76 105.745 51.174 105.781 ;
     RECT  75.204 105.737 75.597 105.809 ;
     RECT  47.7 105.709 47.826 105.823 ;
     RECT  65.088 105.451 65.106 105.823 ;
     RECT  38.52 96.893 38.538 105.871 ;
     RECT  47.7 105.823 48.405 105.899 ;
     RECT  49.464 105.781 49.482 105.899 ;
     RECT  50.652 105.781 51.174 105.899 ;
     RECT  64.515 105.823 65.106 105.899 ;
     RECT  54.684 105.709 54.702 105.971 ;
     RECT  38.52 105.871 38.61 106.013 ;
     RECT  92.772 104.927 92.79 106.043 ;
     RECT  39.456 103.704 43.146 106.093 ;
     RECT  45.615 105.823 45.705 106.093 ;
     RECT  48.315 105.899 48.405 106.093 ;
     RECT  51.015 105.899 51.174 106.093 ;
     RECT  53.715 105.823 53.805 106.093 ;
     RECT  56.415 105.823 56.505 106.093 ;
     RECT  59.115 105.823 59.205 106.093 ;
     RECT  61.815 105.823 61.905 106.093 ;
     RECT  67.215 105.823 67.305 106.093 ;
     RECT  69.915 105.823 70.005 106.093 ;
     RECT  72.615 105.823 72.705 106.093 ;
     RECT  75.24 105.809 75.597 106.709 ;
     RECT  39.456 106.093 43.197 107.275 ;
     RECT  39.456 107.275 43.254 107.671 ;
     RECT  39.456 107.671 43.542 107.789 ;
     RECT  42.156 107.789 43.542 108.509 ;
     RECT  42.156 108.509 43.398 108.653 ;
     RECT  39.456 107.789 41.418 109.184 ;
     RECT  64.515 105.899 64.797 110.011 ;
     RECT  64.515 110.011 64.854 110.461 ;
     RECT  64.515 110.461 65.034 110.525 ;
     RECT  40.215 109.184 41.418 113.459 ;
     RECT  42.156 108.653 43.197 114.349 ;
     RECT  40.215 113.459 41.31 114.523 ;
     RECT  42.084 114.349 43.197 114.523 ;
     RECT  24.015 2.413 24.297 117.067 ;
     RECT  39.456 109.184 39.474 117.085 ;
     RECT  40.215 114.523 43.197 117.085 ;
     RECT  26.715 2.413 26.997 117.211 ;
     RECT  24.015 117.067 24.894 117.319 ;
     RECT  30.78 117.211 30.798 117.341 ;
     RECT  22.824 117.319 22.842 117.419 ;
     RECT  24.015 117.319 25.254 117.419 ;
     RECT  26.676 117.211 26.997 117.437 ;
     RECT  24.015 117.419 25.074 117.509 ;
     RECT  24.015 117.509 24.894 117.533 ;
     RECT  3.924 117.391 3.942 118.021 ;
     RECT  39.456 117.085 43.197 118.049 ;
     RECT  3.42 118.021 3.942 118.157 ;
     RECT  37.515 95.711 37.797 118.165 ;
     RECT  3.672 118.157 3.942 118.201 ;
     RECT  5.115 95.171 5.397 118.201 ;
     RECT  37.008 118.165 37.797 118.201 ;
     RECT  0.108 118.129 0.126 118.253 ;
     RECT  7.815 93.083 8.097 118.291 ;
     RECT  3.672 118.201 4.158 118.435 ;
     RECT  5.115 118.201 5.634 118.435 ;
     RECT  7.164 118.291 8.097 118.435 ;
     RECT  2.415 93.515 2.697 118.459 ;
     RECT  7.164 118.435 8.19 118.471 ;
     RECT  36.54 118.201 37.797 118.561 ;
     RECT  38.52 106.013 38.538 118.561 ;
     RECT  34.815 92.849 35.097 118.597 ;
     RECT  7.02 118.471 8.19 118.705 ;
     RECT  34.815 118.597 35.802 118.741 ;
     RECT  36.54 118.561 38.538 118.741 ;
     RECT  2.415 118.459 2.79 118.795 ;
     RECT  3.672 118.435 5.634 118.831 ;
     RECT  34.776 118.741 38.538 118.859 ;
     RECT  3.672 118.831 5.85 118.939 ;
     RECT  6.876 118.705 8.478 118.939 ;
     RECT  34.815 118.859 38.538 118.939 ;
     RECT  2.304 118.795 2.79 119.083 ;
     RECT  3.672 118.939 8.478 119.083 ;
     RECT  0.144 118.987 0.162 119.117 ;
     RECT  2.304 119.083 8.478 119.129 ;
     RECT  9.396 118.939 9.414 119.129 ;
     RECT  6.732 119.129 8.478 119.281 ;
     RECT  34.815 118.939 38.61 119.281 ;
     RECT  2.304 119.129 5.994 119.551 ;
     RECT  2.268 119.551 5.994 119.837 ;
     RECT  2.415 119.837 5.994 119.899 ;
     RECT  6.732 119.281 8.622 119.899 ;
     RECT  34.815 119.281 38.826 119.947 ;
     RECT  34.815 119.947 38.934 120.047 ;
     RECT  2.415 119.899 8.622 120.181 ;
     RECT  10.515 91.661 10.797 120.289 ;
     RECT  10.515 120.289 10.818 120.389 ;
     RECT  2.415 120.181 8.874 120.479 ;
     RECT  2.415 120.479 8.802 120.509 ;
     RECT  3.564 120.509 8.802 120.623 ;
     RECT  2.415 120.509 2.79 120.659 ;
     RECT  0.144 120.379 0.162 120.989 ;
     RECT  3.564 120.623 8.73 121.019 ;
     RECT  2.415 120.659 2.697 121.243 ;
     RECT  10.515 120.389 10.797 121.333 ;
     RECT  40.068 118.049 43.197 121.333 ;
     RECT  2.268 121.243 2.697 121.373 ;
     RECT  34.815 120.047 38.898 121.441 ;
     RECT  3.564 121.019 8.478 121.567 ;
     RECT  34.815 121.441 39.186 121.567 ;
     RECT  40.032 121.333 43.197 121.567 ;
     RECT  30.78 121.441 30.798 121.631 ;
     RECT  0.108 121.531 0.126 121.739 ;
     RECT  10.224 121.333 10.797 121.739 ;
     RECT  9.288 121.531 9.306 121.829 ;
     RECT  3.456 121.567 8.478 121.909 ;
     RECT  2.304 121.373 2.697 122.009 ;
     RECT  3.456 121.909 8.838 122.341 ;
     RECT  0.324 122.251 0.342 122.429 ;
     RECT  3.42 122.341 8.838 122.429 ;
     RECT  0.108 122.539 0.126 122.669 ;
     RECT  3.6 122.429 8.838 122.819 ;
     RECT  34.815 121.567 43.197 122.917 ;
     RECT  3.888 122.819 8.838 122.957 ;
     RECT  3.888 122.957 3.906 123.017 ;
     RECT  34.776 122.917 43.197 123.089 ;
     RECT  4.968 122.957 8.838 123.101 ;
     RECT  75.315 106.709 75.597 123.151 ;
     RECT  75.132 123.151 75.597 123.331 ;
     RECT  74.844 123.331 75.597 123.835 ;
     RECT  5.115 123.101 8.838 123.899 ;
     RECT  73.908 123.295 73.926 124.231 ;
     RECT  74.772 123.835 75.597 124.231 ;
     RECT  5.115 123.899 8.097 124.439 ;
     RECT  34.815 123.089 43.197 124.609 ;
     RECT  6.444 124.439 8.097 124.645 ;
     RECT  8.82 123.899 8.838 124.645 ;
     RECT  6.444 124.645 8.838 124.685 ;
     RECT  6.444 124.685 8.097 124.709 ;
     RECT  94.215 104.351 94.497 125.041 ;
     RECT  94.215 125.041 94.77 125.221 ;
     RECT  8.82 124.685 8.838 125.249 ;
     RECT  76.68 124.609 76.698 125.311 ;
     RECT  73.908 124.231 75.597 125.347 ;
     RECT  94.068 125.221 94.77 125.347 ;
     RECT  97.488 125.131 97.506 125.41 ;
     RECT  7.164 124.709 8.097 125.411 ;
     RECT  93.348 125.347 94.77 125.491 ;
     RECT  96.336 125.221 96.354 125.491 ;
     RECT  97.488 125.41 97.542 125.491 ;
     RECT  92.664 125.491 94.77 125.581 ;
     RECT  86.115 100.769 86.397 125.689 ;
     RECT  91.515 105.161 91.797 125.689 ;
     RECT  91.116 125.689 91.797 125.725 ;
     RECT  92.664 125.581 95.022 125.725 ;
     RECT  91.116 125.725 95.022 125.761 ;
     RECT  91.044 125.761 95.022 125.851 ;
     RECT  86.115 125.689 86.67 125.879 ;
     RECT  78.015 99.455 78.297 125.923 ;
     RECT  90.216 125.887 90.234 125.923 ;
     RECT  91.044 125.851 95.202 125.923 ;
     RECT  90.216 125.923 95.202 125.933 ;
     RECT  76.644 125.311 76.698 125.947 ;
     RECT  77.508 125.923 78.297 125.947 ;
     RECT  73.872 125.347 75.597 125.995 ;
     RECT  76.644 125.947 78.297 126.031 ;
     RECT  96.336 125.491 97.542 126.059 ;
     RECT  88.815 100.229 89.097 126.229 ;
     RECT  90.9 125.933 95.202 126.283 ;
     RECT  96.336 126.059 97.506 126.283 ;
     RECT  34.815 124.609 43.29 126.301 ;
     RECT  72.615 106.093 72.897 126.301 ;
     RECT  73.692 125.995 75.597 126.301 ;
     RECT  76.572 126.031 78.297 126.365 ;
     RECT  72.615 126.301 75.597 126.571 ;
     RECT  72.615 126.571 75.726 126.661 ;
     RECT  76.572 126.365 76.77 126.661 ;
     RECT  77.508 126.365 78.297 126.661 ;
     RECT  90.9 126.283 97.506 126.689 ;
     RECT  88.815 126.229 89.586 126.725 ;
     RECT  95.544 126.689 97.506 126.797 ;
     RECT  95.544 126.797 95.922 126.833 ;
     RECT  90.9 126.689 94.698 126.841 ;
     RECT  95.652 126.833 95.922 126.959 ;
     RECT  90.504 126.841 94.698 126.995 ;
     RECT  77.508 126.661 78.678 127.067 ;
     RECT  96.912 126.797 97.506 127.067 ;
     RECT  96.912 127.067 96.93 127.139 ;
     RECT  45.615 106.093 45.897 127.187 ;
     RECT  48.315 106.093 48.597 127.187 ;
     RECT  51.015 106.093 51.297 127.187 ;
     RECT  53.715 106.093 53.997 127.187 ;
     RECT  56.415 106.093 56.697 127.187 ;
     RECT  59.115 106.093 59.397 127.187 ;
     RECT  61.815 106.093 62.097 127.187 ;
     RECT  64.515 110.525 64.797 127.187 ;
     RECT  67.215 106.093 67.497 127.187 ;
     RECT  69.915 106.093 70.197 127.187 ;
     RECT  72.615 126.661 76.77 127.187 ;
     RECT  73.548 127.187 76.77 127.229 ;
     RECT  90.9 126.995 94.698 127.373 ;
     RECT  34.815 126.301 43.362 127.381 ;
     RECT  95.652 126.959 95.742 127.409 ;
     RECT  45.615 127.187 45.705 127.457 ;
     RECT  48.315 127.187 48.405 127.457 ;
     RECT  51.015 127.187 51.105 127.457 ;
     RECT  53.715 127.187 53.805 127.457 ;
     RECT  56.415 127.187 56.505 127.457 ;
     RECT  59.115 127.187 59.205 127.457 ;
     RECT  61.815 127.187 61.905 127.457 ;
     RECT  64.515 127.187 64.605 127.457 ;
     RECT  67.215 127.187 67.305 127.457 ;
     RECT  69.915 127.187 70.005 127.457 ;
     RECT  72.615 127.187 72.705 127.457 ;
     RECT  34.815 127.381 43.47 127.571 ;
     RECT  34.815 127.571 43.29 127.921 ;
     RECT  74.52 127.229 76.77 128.285 ;
     RECT  34.776 127.921 43.29 128.461 ;
     RECT  34.56 128.461 43.29 128.525 ;
     RECT  34.815 128.525 43.29 128.579 ;
     RECT  75.132 128.285 76.77 129.091 ;
     RECT  77.508 127.067 78.297 129.091 ;
     RECT  34.815 128.579 43.038 129.451 ;
     RECT  34.815 129.451 43.11 129.6 ;
     RECT  75.132 129.091 78.297 129.6 ;
     RECT  3.42 129.739 3.438 129.811 ;
     RECT  5.115 124.439 5.397 129.811 ;
     RECT  6.804 129.739 6.822 129.811 ;
     RECT  2.415 122.009 2.697 129.901 ;
     RECT  3.42 129.811 5.397 129.901 ;
     RECT  34.815 129.6 78.297 129.901 ;
     RECT  2.415 129.901 5.397 129.979 ;
     RECT  34.776 129.901 78.297 129.979 ;
     RECT  6.66 129.811 6.822 130.009 ;
     RECT  6.372 130.009 6.858 130.109 ;
     RECT  2.415 129.979 5.562 130.243 ;
     RECT  6.372 130.109 6.822 130.243 ;
     RECT  83.415 99.689 83.697 130.315 ;
     RECT  7.815 125.411 8.097 130.459 ;
     RECT  9.288 130.207 9.306 130.469 ;
     RECT  34.56 129.979 78.297 130.469 ;
     RECT  83.415 130.315 83.826 130.469 ;
     RECT  88.815 126.725 89.097 130.477 ;
     RECT  7.74 130.459 8.37 130.505 ;
     RECT  2.415 130.243 6.822 130.541 ;
     RECT  90.9 127.373 94.59 130.555 ;
     RECT  1.152 130.555 1.17 130.603 ;
     RECT  90.432 130.555 94.59 130.739 ;
     RECT  80.715 47.645 80.997 130.747 ;
     RECT  1.152 130.603 1.278 130.781 ;
     RECT  90.432 130.739 93.078 130.795 ;
     RECT  0.108 129.811 0.126 130.843 ;
     RECT  3.42 130.541 6.822 130.981 ;
     RECT  34.704 130.469 78.297 130.981 ;
     RECT  86.115 125.879 86.397 130.981 ;
     RECT  34.704 130.981 78.39 130.987 ;
     RECT  7.74 130.505 8.097 131.017 ;
     RECT  80.388 130.747 80.997 131.081 ;
     RECT  34.704 130.987 78.786 131.117 ;
     RECT  0.108 130.843 0.198 131.153 ;
     RECT  90.36 130.795 93.078 131.213 ;
     RECT  91.44 131.213 93.078 131.279 ;
     RECT  86.115 130.981 86.922 131.287 ;
     RECT  2.415 130.541 2.697 131.419 ;
     RECT  3.42 130.981 6.858 131.419 ;
     RECT  2.415 131.419 6.858 131.431 ;
     RECT  94.104 130.739 94.59 131.431 ;
     RECT  95.652 127.409 95.67 131.431 ;
     RECT  2.415 131.431 6.966 131.521 ;
     RECT  7.704 131.017 8.097 131.521 ;
     RECT  92.52 131.279 92.97 131.549 ;
     RECT  88.815 130.477 89.19 131.557 ;
     RECT  86.115 131.287 87.174 131.593 ;
     RECT  92.52 131.549 92.79 131.597 ;
     RECT  2.415 131.521 8.097 131.621 ;
     RECT  92.592 131.597 92.79 131.621 ;
     RECT  94.104 131.431 95.67 131.621 ;
     RECT  7.704 131.621 8.097 131.629 ;
     RECT  94.104 131.621 94.497 131.629 ;
     RECT  86.115 131.593 87.21 131.693 ;
     RECT  0.144 131.153 0.162 131.789 ;
     RECT  92.736 131.621 92.79 131.819 ;
     RECT  2.415 131.621 6.966 131.837 ;
     RECT  82.656 131.371 82.674 131.899 ;
     RECT  83.415 130.469 83.697 131.899 ;
     RECT  34.815 131.117 78.786 131.933 ;
     RECT  82.656 131.899 83.697 131.933 ;
     RECT  86.115 131.693 87.174 131.933 ;
     RECT  90.36 131.213 90.702 132.061 ;
     RECT  91.44 131.279 91.797 132.061 ;
     RECT  3.996 131.837 6.966 132.089 ;
     RECT  7.704 131.629 8.586 132.089 ;
     RECT  7.704 132.089 8.097 132.125 ;
     RECT  34.815 131.933 78.678 132.125 ;
     RECT  82.764 131.933 83.697 132.125 ;
     RECT  95.292 131.621 95.67 132.161 ;
     RECT  84.888 131.827 84.906 132.221 ;
     RECT  90.36 132.061 91.797 132.233 ;
     RECT  88.308 131.557 89.19 132.269 ;
     RECT  76.716 132.125 78.678 132.413 ;
     RECT  4.68 132.089 6.966 132.467 ;
     RECT  91.188 132.233 91.797 132.557 ;
     RECT  7.815 132.125 8.097 132.871 ;
     RECT  34.815 132.125 75.798 132.979 ;
     RECT  34.815 132.979 75.834 133.147 ;
     RECT  76.716 132.413 78.462 133.147 ;
     RECT  34.815 133.147 78.462 133.285 ;
     RECT  5.115 132.467 6.966 133.313 ;
     RECT  34.815 133.285 78.57 133.439 ;
     RECT  34.815 133.439 78.534 134.045 ;
     RECT  34.815 134.045 76.374 134.141 ;
     RECT  5.115 133.313 5.994 134.159 ;
     RECT  34.815 134.141 41.31 134.237 ;
     RECT  77.436 134.045 78.534 134.249 ;
     RECT  42.192 134.141 75.582 134.333 ;
     RECT  6.804 133.313 6.966 134.429 ;
     RECT  77.436 134.249 78.498 134.519 ;
     RECT  34.815 134.237 41.022 134.591 ;
     RECT  6.948 134.429 6.966 134.969 ;
     RECT  77.436 134.519 78.297 135.005 ;
     RECT  42.192 134.333 75.51 135.067 ;
     RECT  76.32 134.141 76.374 135.067 ;
     RECT  77.508 135.005 78.297 135.101 ;
     RECT  42.192 135.067 76.374 135.197 ;
     RECT  7.815 132.871 8.586 135.239 ;
     RECT  42.192 135.197 42.318 135.259 ;
     RECT  43.2 135.197 76.374 135.293 ;
     RECT  42.156 135.259 42.318 135.365 ;
     RECT  42.264 135.365 42.318 135.389 ;
     RECT  34.815 134.591 40.914 135.473 ;
     RECT  42.3 135.389 42.318 135.485 ;
     RECT  77.58 135.101 78.297 135.985 ;
     RECT  35.892 135.473 40.914 136.061 ;
     RECT  77.544 135.985 78.297 136.061 ;
     RECT  43.2 135.293 75.87 136.183 ;
     RECT  42.768 136.183 75.87 136.381 ;
     RECT  36.288 136.061 40.914 136.561 ;
     RECT  77.58 136.061 78.297 136.715 ;
     RECT  36.288 136.561 40.95 136.759 ;
     RECT  36.288 136.759 41.022 137.101 ;
     RECT  42.768 136.381 76.41 137.405 ;
     RECT  36.288 137.101 41.634 137.489 ;
     RECT  42.768 137.405 75.192 137.501 ;
     RECT  77.616 136.715 78.297 137.563 ;
     RECT  37.224 137.489 41.634 137.569 ;
     RECT  37.224 137.569 42.462 137.693 ;
     RECT  37.224 137.693 41.022 138.029 ;
     RECT  77.58 137.563 78.297 138.427 ;
     RECT  37.515 138.029 41.022 138.451 ;
     RECT  41.796 137.693 42.462 138.451 ;
     RECT  90.36 132.233 90.45 138.451 ;
     RECT  93.924 131.629 94.497 138.451 ;
     RECT  95.292 132.161 95.31 138.451 ;
     RECT  93.924 138.451 95.31 138.541 ;
     RECT  37.515 138.451 42.462 138.619 ;
     RECT  43.2 137.501 75.192 138.619 ;
     RECT  90.288 138.451 90.45 138.649 ;
     RECT  93.924 138.541 95.454 138.649 ;
     RECT  90.288 138.649 90.666 138.721 ;
     RECT  92.772 131.819 92.79 138.883 ;
     RECT  93.6 138.649 95.454 138.883 ;
     RECT  37.515 138.619 75.192 138.911 ;
     RECT  76.392 137.405 76.41 138.955 ;
     RECT  92.772 138.883 95.454 139.099 ;
     RECT  96.336 138.649 96.354 139.099 ;
     RECT  37.515 138.911 41.382 139.225 ;
     RECT  91.515 132.557 91.797 139.261 ;
     RECT  92.772 139.099 96.354 139.261 ;
     RECT  76.392 138.955 76.662 139.291 ;
     RECT  42.444 138.911 75.192 139.483 ;
     RECT  76.356 139.291 76.662 139.483 ;
     RECT  90.288 138.721 90.738 139.483 ;
     RECT  91.515 139.261 96.354 139.483 ;
     RECT  42.444 139.483 76.662 139.495 ;
     RECT  77.436 138.427 78.297 139.495 ;
     RECT  90.216 139.483 96.354 139.523 ;
     RECT  90.36 139.523 96.354 139.531 ;
     RECT  42.444 139.495 78.297 139.675 ;
     RECT  37.188 139.225 41.382 139.771 ;
     RECT  42.156 139.675 78.297 139.771 ;
     RECT  90.36 139.531 96.39 139.991 ;
     RECT  97.488 139.765 97.506 140.107 ;
     RECT  37.188 139.771 78.297 140.203 ;
     RECT  90.36 139.991 95.922 140.341 ;
     RECT  90.324 140.341 95.922 140.395 ;
     RECT  36.972 140.203 78.297 140.611 ;
     RECT  36.972 140.611 78.93 140.729 ;
     RECT  88.815 132.269 89.19 140.809 ;
     RECT  90.18 140.395 95.922 140.809 ;
     RECT  96.912 140.107 97.506 141.179 ;
     RECT  88.815 140.809 95.994 141.584 ;
     RECT  88.815 141.584 95.454 141.683 ;
     RECT  37.404 140.729 78.93 141.809 ;
     RECT  96.912 141.179 96.93 141.853 ;
     RECT  96.3 141.853 96.93 141.869 ;
     RECT  37.404 141.809 41.598 141.917 ;
     RECT  88.815 141.683 95.382 141.953 ;
     RECT  88.815 141.953 89.19 141.989 ;
     RECT  42.444 141.809 78.93 142.115 ;
     RECT  90.108 141.953 95.382 142.493 ;
     RECT  98.172 142.555 98.19 142.591 ;
     RECT  37.515 141.917 41.598 142.619 ;
     RECT  98.172 142.591 98.262 142.619 ;
     RECT  98.244 142.619 98.262 142.637 ;
     RECT  90.36 142.493 95.382 142.799 ;
     RECT  90.468 142.799 95.382 142.987 ;
     RECT  96.3 141.869 96.354 142.987 ;
     RECT  88.815 141.989 89.097 143.083 ;
     RECT  90.468 142.987 96.354 143.131 ;
     RECT  97.488 142.843 97.506 143.131 ;
     RECT  86.115 131.933 86.922 143.159 ;
     RECT  88.815 143.083 89.478 143.311 ;
     RECT  90.468 143.131 97.506 143.419 ;
     RECT  88.815 143.311 89.622 143.429 ;
     RECT  90.468 143.419 97.542 143.429 ;
     RECT  93.492 143.429 97.542 143.537 ;
     RECT  96.912 143.537 97.542 143.573 ;
     RECT  93.492 143.537 95.814 143.699 ;
     RECT  97.524 143.573 97.542 143.807 ;
     RECT  42.444 142.115 77.238 144.661 ;
     RECT  42.192 144.661 77.238 146.904 ;
     RECT  93.528 143.699 95.238 147.101 ;
     RECT  70.704 146.904 70.722 147.197 ;
     RECT  42.192 146.904 43.146 147.209 ;
     RECT  93.528 147.101 94.914 147.209 ;
     RECT  90.468 143.429 92.538 147.245 ;
     RECT  75.168 146.904 77.238 147.479 ;
     RECT  76.104 147.479 77.238 147.515 ;
     RECT  37.515 142.619 41.382 147.659 ;
     RECT  93.744 147.209 94.914 147.659 ;
     RECT  42.444 147.209 43.146 147.749 ;
     RECT  93.744 147.659 94.734 147.773 ;
     RECT  92.52 147.245 92.538 147.785 ;
     RECT  37.515 147.659 41.31 147.821 ;
     RECT  90.468 147.245 91.797 147.821 ;
     RECT  37.515 147.821 40.914 147.857 ;
     RECT  76.14 147.515 77.238 147.857 ;
     RECT  76.14 147.857 76.158 147.893 ;
     RECT  37.515 147.857 40.842 147.929 ;
     RECT  77.22 147.857 77.238 147.929 ;
     RECT  93.744 147.773 94.497 148.469 ;
     RECT  90.468 147.821 90.486 148.937 ;
     RECT  42.732 147.749 43.146 148.973 ;
     RECT  47.88 148.441 47.898 148.981 ;
     RECT  50.148 148.909 50.166 148.981 ;
     RECT  78.015 142.115 78.93 149.009 ;
     RECT  47.88 148.981 47.97 149.023 ;
     RECT  75.168 147.479 75.294 149.023 ;
     RECT  46.8 148.945 46.818 149.071 ;
     RECT  47.88 149.023 48.405 149.099 ;
     RECT  49.536 148.981 50.166 149.099 ;
     RECT  75.168 149.023 75.405 149.135 ;
     RECT  46.764 149.071 46.818 149.171 ;
     RECT  46.764 149.171 46.782 149.279 ;
     RECT  42.915 148.973 43.146 149.293 ;
     RECT  45.615 149.023 45.705 149.293 ;
     RECT  48.315 149.099 48.405 149.293 ;
     RECT  51.015 149.023 51.105 149.293 ;
     RECT  53.715 149.023 53.805 149.293 ;
     RECT  56.415 149.023 56.505 149.293 ;
     RECT  59.115 149.023 59.205 149.293 ;
     RECT  61.815 149.023 61.905 149.293 ;
     RECT  64.515 149.023 64.605 149.293 ;
     RECT  67.215 149.023 67.305 149.293 ;
     RECT  69.915 149.023 70.005 149.293 ;
     RECT  72.615 149.023 72.705 149.293 ;
     RECT  75.24 149.135 75.405 149.293 ;
     RECT  75.24 149.293 75.597 150.215 ;
     RECT  37.515 147.929 40.497 165.883 ;
     RECT  37.44 165.883 40.497 165.92 ;
     RECT  37.515 165.92 40.497 167.999 ;
     RECT  2.415 131.837 2.697 168.227 ;
     RECT  5.115 134.159 5.397 168.227 ;
     RECT  7.815 135.239 8.097 168.227 ;
     RECT  10.515 121.739 10.797 168.227 ;
     RECT  13.215 88.529 13.497 168.227 ;
     RECT  15.915 2.413 16.197 168.227 ;
     RECT  18.615 2.413 18.897 168.227 ;
     RECT  21.315 100.013 21.597 168.227 ;
     RECT  24.015 117.533 24.297 168.227 ;
     RECT  26.715 117.437 26.997 168.227 ;
     RECT  29.415 40.733 29.697 168.227 ;
     RECT  32.115 2.413 32.397 168.227 ;
     RECT  34.815 135.473 35.097 168.227 ;
     RECT  40.215 167.999 40.497 168.227 ;
     RECT  42.915 149.293 43.197 168.227 ;
     RECT  45.615 149.293 45.897 168.227 ;
     RECT  48.315 149.293 48.597 168.227 ;
     RECT  51.015 149.293 51.297 168.227 ;
     RECT  53.715 149.293 53.997 168.227 ;
     RECT  56.415 149.293 56.697 168.227 ;
     RECT  59.115 149.293 59.397 168.227 ;
     RECT  61.815 149.293 62.097 168.227 ;
     RECT  64.515 149.293 64.797 168.227 ;
     RECT  67.215 149.293 67.497 168.227 ;
     RECT  69.915 149.293 70.197 168.227 ;
     RECT  72.615 149.293 72.897 168.227 ;
     RECT  75.315 150.215 75.597 168.227 ;
     RECT  78.015 149.009 78.297 168.227 ;
     RECT  80.715 131.081 80.997 168.227 ;
     RECT  83.415 132.125 83.697 168.227 ;
     RECT  86.115 143.159 86.397 168.227 ;
     RECT  88.815 143.429 89.097 168.227 ;
     RECT  91.515 147.821 91.797 168.227 ;
     RECT  94.215 148.469 94.497 168.227 ;
     RECT  2.415 168.227 2.505 168.497 ;
     RECT  5.115 168.227 5.205 168.497 ;
     RECT  7.815 168.227 7.905 168.497 ;
     RECT  10.515 168.227 10.605 168.497 ;
     RECT  13.215 168.227 13.305 168.497 ;
     RECT  15.915 168.227 16.005 168.497 ;
     RECT  18.615 168.227 18.705 168.497 ;
     RECT  21.315 168.227 21.405 168.497 ;
     RECT  24.015 168.227 24.105 168.497 ;
     RECT  26.715 168.227 26.805 168.497 ;
     RECT  29.415 168.227 29.505 168.497 ;
     RECT  32.115 168.227 32.205 168.497 ;
     RECT  34.815 168.227 34.905 168.497 ;
     RECT  37.515 167.999 39.006 168.497 ;
     RECT  40.215 168.227 40.305 168.497 ;
     RECT  42.915 168.227 43.005 168.497 ;
     RECT  45.615 168.227 45.705 168.497 ;
     RECT  48.315 168.227 48.405 168.497 ;
     RECT  51.015 168.227 51.105 168.497 ;
     RECT  53.715 168.227 53.805 168.497 ;
     RECT  56.415 168.227 56.505 168.497 ;
     RECT  59.115 168.227 59.205 168.497 ;
     RECT  61.815 168.227 61.905 168.497 ;
     RECT  64.515 168.227 64.605 168.497 ;
     RECT  67.215 168.227 67.305 168.497 ;
     RECT  69.915 168.227 70.005 168.497 ;
     RECT  72.615 168.227 72.705 168.497 ;
     RECT  75.315 168.227 75.405 168.497 ;
     RECT  78.015 168.227 78.105 168.497 ;
     RECT  80.715 168.227 80.805 168.497 ;
     RECT  83.415 168.227 83.505 168.497 ;
     RECT  86.115 168.227 86.205 168.497 ;
     RECT  88.815 168.227 88.905 168.497 ;
     RECT  91.515 168.227 91.605 168.497 ;
     RECT  94.215 168.227 94.305 168.497 ;
     RECT  38.052 168.497 39.006 170.347 ;
     RECT  37.836 170.347 39.006 170.603 ;
     RECT  37.836 170.603 37.908 170.609 ;
     RECT  37.926 170.603 38.016 170.609 ;
     RECT  38.034 170.603 38.124 170.609 ;
     RECT  38.142 170.603 38.232 170.609 ;
     RECT  38.25 170.603 38.34 170.609 ;
     RECT  38.358 170.603 38.448 170.609 ;
     RECT  38.466 170.603 38.556 170.609 ;
     RECT  38.574 170.603 38.664 170.609 ;
     RECT  38.682 170.603 38.772 170.609 ;
     RECT  38.79 170.603 38.88 170.609 ;
     RECT  38.898 170.603 38.988 170.609 ;
     RECT  37.926 170.609 38.016 170.621 ;
     RECT  38.034 170.609 38.124 170.621 ;
     RECT  38.142 170.609 38.232 170.621 ;
     RECT  38.25 170.609 38.34 170.621 ;
     RECT  38.358 170.609 38.448 170.621 ;
     RECT  38.466 170.609 38.556 170.621 ;
     RECT  38.574 170.609 38.664 170.621 ;
     RECT  38.682 170.609 38.772 170.621 ;
     RECT  38.79 170.609 38.88 170.621 ;
     RECT  38.898 170.609 38.988 170.621 ;
    LAYER M4 ;
     RECT  0.084 31.68 0.097 31.704 ;
     RECT  0.06 31.704 0.097 31.824 ;
     RECT  0.084 31.824 0.097 31.848 ;
     RECT  0.06 31.848 0.097 31.968 ;
     RECT  0.084 31.968 0.097 31.992 ;
     RECT  0.06 31.992 0.097 32.112 ;
     RECT  0.084 32.112 0.097 32.136 ;
     RECT  0.06 32.136 0.097 32.256 ;
     RECT  0.084 32.256 0.097 32.28 ;
     RECT  0.06 32.28 0.097 32.4 ;
     RECT  0.084 32.4 0.097 32.424 ;
     RECT  0.06 32.424 0.097 32.544 ;
     RECT  0.084 32.544 0.097 32.568 ;
     RECT  0.06 32.568 0.097 32.688 ;
     RECT  0.084 32.688 0.097 32.712 ;
     RECT  0.06 32.712 0.097 32.832 ;
     RECT  0.084 32.832 0.097 32.856 ;
     RECT  0.06 32.856 0.097 32.976 ;
     RECT  0.084 32.976 0.097 33 ;
     RECT  0.06 33 0.097 33.12 ;
     RECT  0.084 33.12 0.097 33.144 ;
     RECT  0.06 33.144 0.097 33.264 ;
     RECT  0.084 33.264 0.097 33.288 ;
     RECT  0.06 33.288 0.097 33.408 ;
     RECT  0.084 33.408 0.097 33.432 ;
     RECT  0.06 33.432 0.097 33.552 ;
     RECT  0.084 33.552 0.097 33.576 ;
     RECT  0.06 33.576 0.097 33.696 ;
     RECT  0.084 33.696 0.097 33.72 ;
     RECT  0.06 33.72 0.097 33.84 ;
     RECT  0.084 33.84 0.097 33.864 ;
     RECT  0.06 33.864 0.097 33.984 ;
     RECT  0.084 33.984 0.097 34.008 ;
     RECT  0.06 34.008 0.097 34.128 ;
     RECT  0.084 34.128 0.097 34.152 ;
     RECT  0.06 34.152 0.097 34.272 ;
     RECT  0.084 34.272 0.097 34.296 ;
     RECT  0.06 34.296 0.097 34.416 ;
     RECT  0.084 34.416 0.097 34.44 ;
     RECT  0.06 34.44 0.097 34.56 ;
     RECT  0.084 34.56 0.097 34.584 ;
     RECT  0.06 34.584 0.097 34.704 ;
     RECT  0.084 34.704 0.097 34.728 ;
     RECT  0.06 34.728 0.097 34.848 ;
     RECT  0.084 34.848 0.097 34.872 ;
     RECT  0.06 34.872 0.097 34.992 ;
     RECT  0.084 34.992 0.097 35.016 ;
     RECT  0.06 35.016 0.097 35.136 ;
     RECT  0.084 35.136 0.097 35.16 ;
     RECT  0.06 35.16 0.097 35.28 ;
     RECT  0.084 35.28 0.097 35.304 ;
     RECT  0.06 35.304 0.097 35.424 ;
     RECT  0.084 35.424 0.097 35.448 ;
     RECT  0.06 35.448 0.097 35.568 ;
     RECT  0.084 35.568 0.097 35.592 ;
     RECT  0.06 35.592 0.097 35.712 ;
     RECT  0.084 35.712 0.097 35.736 ;
     RECT  0.06 35.736 0.097 35.856 ;
     RECT  0.084 35.856 0.097 35.88 ;
     RECT  0.06 35.88 0.097 36 ;
     RECT  0.084 36 0.097 36.024 ;
     RECT  0.06 36.024 0.097 36.144 ;
     RECT  0.084 36.144 0.097 36.168 ;
     RECT  0.084 84.672 0.097 84.696 ;
     RECT  0.06 84.696 0.097 84.816 ;
     RECT  0.084 84.816 0.097 84.84 ;
     RECT  0.06 84.84 0.097 84.96 ;
     RECT  0.084 84.96 0.097 84.984 ;
     RECT  0.06 84.984 0.097 85.104 ;
     RECT  0.084 85.104 0.097 85.128 ;
     RECT  0.06 85.128 0.097 85.248 ;
     RECT  0.084 85.248 0.097 85.272 ;
     RECT  0.06 85.272 0.097 85.392 ;
     RECT  0.084 85.392 0.097 85.416 ;
     RECT  0.06 85.416 0.097 85.536 ;
     RECT  0.084 85.536 0.097 85.56 ;
     RECT  0.06 85.56 0.097 85.68 ;
     RECT  0.084 85.68 0.097 85.704 ;
     RECT  0.06 85.704 0.097 85.824 ;
     RECT  0.084 85.824 0.097 85.848 ;
     RECT  0.06 85.848 0.097 85.968 ;
     RECT  0.084 85.968 0.097 85.992 ;
     RECT  0.06 85.992 0.097 86.112 ;
     RECT  0.084 86.112 0.097 86.136 ;
     RECT  0.06 86.136 0.097 86.256 ;
     RECT  0.084 86.256 0.097 86.28 ;
     RECT  0.06 86.28 0.097 86.4 ;
     RECT  0.084 86.4 0.097 86.424 ;
     RECT  0.06 86.424 0.097 86.544 ;
     RECT  0.084 86.544 0.097 86.568 ;
     RECT  0.06 86.568 0.097 86.688 ;
     RECT  0.084 86.688 0.097 86.712 ;
     RECT  0.06 86.712 0.097 86.832 ;
     RECT  0.084 86.832 0.097 86.856 ;
     RECT  0.06 86.856 0.097 86.976 ;
     RECT  0.084 86.976 0.097 87 ;
     RECT  0.06 87 0.097 87.12 ;
     RECT  0.084 87.12 0.097 87.144 ;
     RECT  0.06 87.144 0.097 87.264 ;
     RECT  0.084 87.264 0.097 87.288 ;
     RECT  0.06 87.288 0.097 87.408 ;
     RECT  0.084 87.408 0.097 87.432 ;
     RECT  0.06 87.432 0.097 87.552 ;
     RECT  0.084 87.552 0.097 87.576 ;
     RECT  0.06 87.576 0.097 87.696 ;
     RECT  0.084 87.696 0.097 87.72 ;
     RECT  0.06 87.72 0.097 87.84 ;
     RECT  0.084 87.84 0.097 87.864 ;
     RECT  0.06 87.864 0.097 87.984 ;
     RECT  0.084 87.984 0.097 88.008 ;
     RECT  0.06 88.008 0.097 88.128 ;
     RECT  0.084 88.128 0.097 88.152 ;
     RECT  0.06 88.152 0.097 88.272 ;
     RECT  0.084 88.272 0.097 88.296 ;
     RECT  0.06 88.296 0.097 88.416 ;
     RECT  0.084 88.416 0.097 88.44 ;
     RECT  0.06 88.44 0.097 88.56 ;
     RECT  0.084 88.56 0.097 88.584 ;
     RECT  0.06 88.584 0.097 88.704 ;
     RECT  0.084 88.704 0.097 88.728 ;
     RECT  0.06 88.728 0.097 88.848 ;
     RECT  0.084 88.848 0.097 88.872 ;
     RECT  0.06 88.872 0.097 88.992 ;
     RECT  0.084 88.992 0.097 89.016 ;
     RECT  0.06 89.016 0.097 89.136 ;
     RECT  0.084 89.136 0.097 89.16 ;
     RECT  0.084 118.08 0.097 118.104 ;
     RECT  0.06 118.104 0.097 118.224 ;
     RECT  0.084 118.224 0.097 118.248 ;
     RECT  0.06 118.248 0.097 118.368 ;
     RECT  0.084 118.368 0.097 118.392 ;
     RECT  0.06 118.392 0.097 118.512 ;
     RECT  0.084 118.512 0.097 118.536 ;
     RECT  0.06 118.536 0.097 118.656 ;
     RECT  0.084 118.656 0.097 118.68 ;
     RECT  0.06 118.68 0.097 118.8 ;
     RECT  0.084 118.8 0.097 118.824 ;
     RECT  0.06 118.824 0.097 118.944 ;
     RECT  0.084 118.944 0.097 118.968 ;
     RECT  0.06 118.968 0.097 119.088 ;
     RECT  0.084 119.088 0.097 119.112 ;
     RECT  0.06 119.112 0.097 119.232 ;
     RECT  0.084 119.232 0.097 119.256 ;
     RECT  0.06 119.256 0.097 119.376 ;
     RECT  0.084 119.376 0.097 119.4 ;
     RECT  0.06 119.4 0.097 119.52 ;
     RECT  0.084 119.52 0.097 119.544 ;
     RECT  0.06 119.544 0.097 119.664 ;
     RECT  0.084 119.664 0.097 119.688 ;
     RECT  0.06 119.688 0.097 119.808 ;
     RECT  0.084 119.808 0.097 119.832 ;
     RECT  0.06 119.832 0.097 119.952 ;
     RECT  0.084 119.952 0.097 119.976 ;
     RECT  0.06 119.976 0.097 120.096 ;
     RECT  0.084 120.096 0.097 120.12 ;
     RECT  0.06 120.12 0.097 120.24 ;
     RECT  0.084 120.24 0.097 120.264 ;
     RECT  0.06 120.264 0.097 120.384 ;
     RECT  0.084 120.384 0.097 120.408 ;
     RECT  0.06 120.408 0.097 120.528 ;
     RECT  0.084 120.528 0.097 120.552 ;
     RECT  0.06 120.552 0.097 120.672 ;
     RECT  0.084 120.672 0.097 120.696 ;
     RECT  0.06 120.696 0.097 120.816 ;
     RECT  0.084 120.816 0.097 120.84 ;
     RECT  0.06 120.84 0.097 120.96 ;
     RECT  0.084 120.96 0.097 120.984 ;
     RECT  0.06 120.984 0.097 121.104 ;
     RECT  0.084 121.104 0.097 121.128 ;
     RECT  0.06 121.128 0.097 121.248 ;
     RECT  0.084 121.248 0.097 121.272 ;
     RECT  0.06 121.272 0.097 121.392 ;
     RECT  0.084 121.392 0.097 121.416 ;
     RECT  0.06 121.416 0.097 121.536 ;
     RECT  0.084 121.536 0.097 121.56 ;
     RECT  0.06 121.56 0.097 121.68 ;
     RECT  0.084 121.68 0.097 121.704 ;
     RECT  0.06 121.704 0.097 121.824 ;
     RECT  0.084 121.824 0.097 121.848 ;
     RECT  0.06 121.848 0.097 121.968 ;
     RECT  0.084 121.968 0.097 121.992 ;
     RECT  0.06 121.992 0.097 122.112 ;
     RECT  0.084 122.112 0.097 122.136 ;
     RECT  0.06 122.136 0.097 122.256 ;
     RECT  0.084 122.256 0.097 122.28 ;
     RECT  0.06 122.28 0.097 122.4 ;
     RECT  0.084 122.4 0.097 122.424 ;
     RECT  0.06 122.424 0.097 122.544 ;
     RECT  0.084 122.544 0.097 122.568 ;
     RECT  0.084 40.896 0.137 40.92 ;
     RECT  0.06 40.92 0.137 41.04 ;
     RECT  0.084 41.04 0.137 41.064 ;
     RECT  0.06 41.064 0.137 41.184 ;
     RECT  0.084 41.184 0.137 41.208 ;
     RECT  0.06 41.208 0.137 41.328 ;
     RECT  0.084 41.328 0.137 41.352 ;
     RECT  0.06 41.352 0.137 41.472 ;
     RECT  0.084 41.472 0.137 41.496 ;
     RECT  0.06 41.496 0.137 41.616 ;
     RECT  0.084 41.616 0.137 41.64 ;
     RECT  0.06 41.64 0.137 41.76 ;
     RECT  0.084 41.76 0.137 41.784 ;
     RECT  0.06 41.784 0.137 41.904 ;
     RECT  0.084 41.904 0.137 41.928 ;
     RECT  0.06 41.928 0.137 42.048 ;
     RECT  0.084 42.048 0.137 42.072 ;
     RECT  0.06 42.072 0.137 42.192 ;
     RECT  0.084 42.192 0.137 42.216 ;
     RECT  0.06 42.216 0.137 42.336 ;
     RECT  0.084 42.336 0.137 42.36 ;
     RECT  0.06 42.36 0.137 42.48 ;
     RECT  0.084 42.48 0.137 42.504 ;
     RECT  0.06 42.504 0.137 42.624 ;
     RECT  0.084 42.624 0.137 42.648 ;
     RECT  0.06 42.648 0.137 42.768 ;
     RECT  0.084 42.768 0.137 42.792 ;
     RECT  0.06 42.792 0.137 42.912 ;
     RECT  0.084 42.912 0.137 42.936 ;
     RECT  0.06 42.936 0.137 43.056 ;
     RECT  0.084 43.056 0.137 43.08 ;
     RECT  0.06 43.08 0.137 43.2 ;
     RECT  0.084 43.2 0.137 43.224 ;
     RECT  0.06 43.224 0.137 43.344 ;
     RECT  0.084 43.344 0.137 43.368 ;
     RECT  0.06 43.368 0.137 43.488 ;
     RECT  0.084 43.488 0.137 43.512 ;
     RECT  0.06 43.512 0.137 43.632 ;
     RECT  0.084 43.632 0.137 43.656 ;
     RECT  0.06 43.656 0.137 43.776 ;
     RECT  0.084 43.776 0.137 43.8 ;
     RECT  0.06 43.8 0.137 43.92 ;
     RECT  0.084 43.92 0.137 43.944 ;
     RECT  0.06 43.944 0.137 44.064 ;
     RECT  0.084 44.064 0.137 44.088 ;
     RECT  0.06 44.088 0.137 44.208 ;
     RECT  0.084 44.208 0.137 44.232 ;
     RECT  0.06 44.232 0.137 44.352 ;
     RECT  0.084 44.352 0.137 44.376 ;
     RECT  0.06 44.376 0.137 44.496 ;
     RECT  0.084 44.496 0.137 44.52 ;
     RECT  0.06 44.52 0.137 44.64 ;
     RECT  0.084 44.64 0.137 44.664 ;
     RECT  0.06 44.664 0.137 44.784 ;
     RECT  0.084 44.784 0.137 44.808 ;
     RECT  0.06 44.808 0.137 44.928 ;
     RECT  0.084 44.928 0.137 44.952 ;
     RECT  0.06 44.952 0.137 45.072 ;
     RECT  0.084 45.072 0.137 45.096 ;
     RECT  0.06 45.096 0.137 45.216 ;
     RECT  0.084 45.216 0.137 45.24 ;
     RECT  0.06 45.24 0.137 45.36 ;
     RECT  0.084 45.36 0.137 45.384 ;
     RECT  0.084 74.304 0.137 74.328 ;
     RECT  0.06 74.328 0.137 74.448 ;
     RECT  0.084 74.448 0.137 74.472 ;
     RECT  0.06 74.472 0.137 74.592 ;
     RECT  0.084 74.592 0.137 74.616 ;
     RECT  0.06 74.616 0.137 74.736 ;
     RECT  0.084 74.736 0.137 74.76 ;
     RECT  0.06 74.76 0.137 74.88 ;
     RECT  0.084 74.88 0.137 74.904 ;
     RECT  0.06 74.904 0.137 75.024 ;
     RECT  0.084 75.024 0.137 75.048 ;
     RECT  0.06 75.048 0.137 75.168 ;
     RECT  0.084 75.168 0.137 75.192 ;
     RECT  0.06 75.192 0.137 75.312 ;
     RECT  0.084 75.312 0.137 75.336 ;
     RECT  0.06 75.336 0.137 75.456 ;
     RECT  0.084 75.456 0.137 75.48 ;
     RECT  0.06 75.48 0.137 75.6 ;
     RECT  0.084 75.6 0.137 75.624 ;
     RECT  0.06 75.624 0.137 75.744 ;
     RECT  0.084 75.744 0.137 75.768 ;
     RECT  0.06 75.768 0.137 75.888 ;
     RECT  0.084 75.888 0.137 75.912 ;
     RECT  0.06 75.912 0.137 76.032 ;
     RECT  0.084 76.032 0.137 76.056 ;
     RECT  0.06 76.056 0.137 76.176 ;
     RECT  0.084 76.176 0.137 76.2 ;
     RECT  0.06 76.2 0.137 76.32 ;
     RECT  0.084 76.32 0.137 76.344 ;
     RECT  0.06 76.344 0.137 76.464 ;
     RECT  0.084 76.464 0.137 76.488 ;
     RECT  0.06 76.488 0.137 76.608 ;
     RECT  0.084 76.608 0.137 76.632 ;
     RECT  0.06 76.632 0.137 76.752 ;
     RECT  0.084 76.752 0.137 76.776 ;
     RECT  0.06 76.776 0.137 76.896 ;
     RECT  0.084 76.896 0.137 76.92 ;
     RECT  0.06 76.92 0.137 77.04 ;
     RECT  0.084 77.04 0.137 77.064 ;
     RECT  0.06 77.064 0.137 77.184 ;
     RECT  0.084 77.184 0.137 77.208 ;
     RECT  0.06 77.208 0.137 77.328 ;
     RECT  0.084 77.328 0.137 77.352 ;
     RECT  0.06 77.352 0.137 77.472 ;
     RECT  0.084 77.472 0.137 77.496 ;
     RECT  0.06 77.496 0.137 77.616 ;
     RECT  0.084 77.616 0.137 77.64 ;
     RECT  0.06 77.64 0.137 77.76 ;
     RECT  0.084 77.76 0.137 77.784 ;
     RECT  0.06 77.784 0.137 77.904 ;
     RECT  0.084 77.904 0.137 77.928 ;
     RECT  0.06 77.928 0.137 78.048 ;
     RECT  0.084 78.048 0.137 78.072 ;
     RECT  0.06 78.072 0.137 78.192 ;
     RECT  0.084 78.192 0.137 78.216 ;
     RECT  0.06 78.216 0.137 78.336 ;
     RECT  0.084 78.336 0.137 78.36 ;
     RECT  0.06 78.36 0.137 78.48 ;
     RECT  0.084 78.48 0.137 78.504 ;
     RECT  0.06 78.504 0.137 78.624 ;
     RECT  0.084 78.624 0.137 78.648 ;
     RECT  0.06 78.648 0.137 78.768 ;
     RECT  0.084 78.768 0.137 78.792 ;
     RECT  0.084 129.888 0.137 129.912 ;
     RECT  0.06 129.912 0.137 130.032 ;
     RECT  0.084 130.032 0.137 130.056 ;
     RECT  0.06 130.056 0.137 130.176 ;
     RECT  0.084 130.176 0.137 130.2 ;
     RECT  0.06 130.2 0.137 130.32 ;
     RECT  0.084 130.32 0.137 130.344 ;
     RECT  0.06 130.344 0.137 130.464 ;
     RECT  0.084 130.464 0.137 130.488 ;
     RECT  0.06 130.488 0.137 130.608 ;
     RECT  0.084 130.608 0.137 130.632 ;
     RECT  0.06 130.632 0.137 130.752 ;
     RECT  0.084 130.752 0.137 130.776 ;
     RECT  0.06 130.776 0.137 130.896 ;
     RECT  0.084 130.896 0.137 130.92 ;
     RECT  0.06 130.92 0.137 131.04 ;
     RECT  0.084 131.04 0.137 131.064 ;
     RECT  0.06 131.064 0.137 131.184 ;
     RECT  0.084 131.184 0.137 131.208 ;
     RECT  0.06 131.208 0.137 131.328 ;
     RECT  0.084 131.328 0.137 131.352 ;
     RECT  0.06 131.352 0.137 131.472 ;
     RECT  0.084 131.472 0.137 131.496 ;
     RECT  0.06 131.496 0.137 131.616 ;
     RECT  0.084 131.616 0.137 131.64 ;
     RECT  0.06 131.64 0.137 131.76 ;
     RECT  0.084 131.76 0.137 131.784 ;
     RECT  0.097 31.68 0.173 36.312 ;
     RECT  0.137 130.032 0.173 131.784 ;
     RECT  0.097 84.672 0.569 89.256 ;
     RECT  0.173 130.032 2.293 131.688 ;
     RECT  0.173 31.776 2.408 36.312 ;
     RECT  0.137 41.04 2.408 45.384 ;
     RECT  0.137 74.448 2.408 78.792 ;
     RECT  0.569 84.816 2.408 89.256 ;
     RECT  0.097 118.08 2.408 122.664 ;
     RECT  2.293 129.984 2.408 131.688 ;
     RECT  2.408 2.148 2.512 168.492 ;
     RECT  2.512 2.418 2.704 168.222 ;
     RECT  2.704 118.08 3.449 122.664 ;
     RECT  2.704 41.088 4.025 45.432 ;
     RECT  2.704 31.776 4.097 36.312 ;
     RECT  4.165 39.744 4.489 39.768 ;
     RECT  2.704 84.72 4.489 89.256 ;
     RECT  3.449 118.368 4.597 122.664 ;
     RECT  4.597 118.368 4.933 122.952 ;
     RECT  4.489 84.144 5.065 89.256 ;
     RECT  4.025 41.088 5.101 45.24 ;
     RECT  4.097 31.968 5.108 36.312 ;
     RECT  4.489 39.36 5.108 39.768 ;
     RECT  5.101 40.944 5.108 45.24 ;
     RECT  2.704 74.448 5.108 78.792 ;
     RECT  5.065 84.096 5.108 89.256 ;
     RECT  4.933 118.368 5.108 123.096 ;
     RECT  2.704 129.936 5.108 131.832 ;
     RECT  5.108 2.148 5.212 168.492 ;
     RECT  5.212 2.418 5.404 168.222 ;
     RECT  5.404 35.424 5.465 36.312 ;
     RECT  5.404 40.944 5.465 42.264 ;
     RECT  5.404 76.992 5.465 78.12 ;
     RECT  5.404 119.52 5.501 122.952 ;
     RECT  5.404 79.2 5.555 79.224 ;
     RECT  5.404 84.096 5.555 87.816 ;
     RECT  5.404 43.92 5.573 45.24 ;
     RECT  5.404 129.984 5.573 131.688 ;
     RECT  5.465 35.424 5.609 36.264 ;
     RECT  5.555 84.144 5.609 87.816 ;
     RECT  5.573 43.92 5.645 44.904 ;
     RECT  5.404 32.208 5.681 34.44 ;
     RECT  5.404 88.896 5.681 88.92 ;
     RECT  5.501 119.664 5.681 122.952 ;
     RECT  5.404 74.88 5.717 75.768 ;
     RECT  5.609 85.392 5.717 87.816 ;
     RECT  5.645 43.92 5.753 44.616 ;
     RECT  5.717 74.88 5.789 75.096 ;
     RECT  5.789 74.976 5.825 75.096 ;
     RECT  5.681 119.664 5.861 121.032 ;
     RECT  5.681 34.08 5.897 34.44 ;
     RECT  5.465 40.944 5.987 42.216 ;
     RECT  5.825 74.976 6.041 75 ;
     RECT  5.717 85.392 6.076 86.76 ;
     RECT  5.573 130.896 6.179 131.688 ;
     RECT  6.179 130.896 6.221 131.64 ;
     RECT  5.609 84.144 6.275 84.168 ;
     RECT  5.465 76.992 6.329 77.544 ;
     RECT  5.404 38.064 6.373 38.184 ;
     RECT  6.076 85.392 6.437 85.416 ;
     RECT  5.717 87.792 6.505 87.816 ;
     RECT  5.987 42.192 6.541 42.216 ;
     RECT  6.541 42.192 6.581 42.792 ;
     RECT  5.861 119.664 6.721 119.976 ;
     RECT  5.861 121.008 6.725 121.032 ;
     RECT  6.581 42.768 6.764 42.792 ;
     RECT  5.753 44.592 6.764 44.616 ;
     RECT  6.221 131.328 6.797 131.64 ;
     RECT  6.505 87.792 6.829 88.344 ;
     RECT  6.469 35.04 6.865 35.064 ;
     RECT  5.609 36.24 6.865 36.264 ;
     RECT  6.721 119.616 6.901 119.976 ;
     RECT  6.076 86.736 6.956 86.76 ;
     RECT  6.829 87.792 6.956 88.92 ;
     RECT  5.681 32.448 7.093 32.616 ;
     RECT  7.093 31.872 7.148 32.616 ;
     RECT  7.148 31.872 7.808 33.576 ;
     RECT  6.865 35.04 7.808 36.264 ;
     RECT  6.577 37.632 7.808 37.656 ;
     RECT  5.404 39.744 7.808 39.768 ;
     RECT  6.764 42.768 7.808 44.616 ;
     RECT  6.329 76.992 7.808 77.016 ;
     RECT  6.901 78.624 7.808 78.648 ;
     RECT  6.956 86.736 7.808 88.92 ;
     RECT  7.093 117.504 7.808 117.528 ;
     RECT  6.901 119.616 7.808 120.888 ;
     RECT  5.681 122.352 7.808 122.952 ;
     RECT  6.997 124.272 7.808 124.296 ;
     RECT  7.729 130.464 7.808 130.488 ;
     RECT  6.797 131.616 7.808 131.64 ;
     RECT  7.808 2.148 7.912 168.492 ;
     RECT  7.912 2.418 8.104 168.222 ;
     RECT  8.104 78.624 8.165 78.648 ;
     RECT  8.104 121.872 8.237 122.952 ;
     RECT  8.104 33.936 8.309 34.824 ;
     RECT  8.309 34.8 8.345 34.824 ;
     RECT  8.104 36.432 8.387 36.456 ;
     RECT  8.237 122.928 8.387 122.952 ;
     RECT  8.104 130.464 8.387 130.488 ;
     RECT  8.237 121.872 8.453 121.896 ;
     RECT  8.104 119.28 8.483 119.976 ;
     RECT  8.104 41.376 8.489 42.216 ;
     RECT  8.483 119.28 8.524 119.304 ;
     RECT  8.104 124.656 8.633 124.68 ;
     RECT  8.104 39.744 10.508 40.056 ;
     RECT  8.104 76.992 10.508 77.016 ;
     RECT  8.104 117.504 10.508 117.528 ;
     RECT  10.508 2.148 10.612 168.492 ;
     RECT  10.612 2.418 10.804 168.222 ;
     RECT  10.804 39.744 12.083 40.056 ;
     RECT  10.804 76.992 12.083 77.016 ;
     RECT  12.083 40.032 13.208 40.056 ;
     RECT  12.037 74.688 13.208 74.712 ;
     RECT  10.804 117.504 13.208 117.528 ;
     RECT  13.208 2.148 13.312 168.492 ;
     RECT  13.312 2.418 13.504 168.222 ;
     RECT  13.504 39.888 13.619 40.728 ;
     RECT  13.504 74.688 13.745 74.904 ;
     RECT  13.619 40.704 14.821 40.728 ;
     RECT  14.821 40.608 14.861 40.728 ;
     RECT  14.861 40.608 15.908 40.632 ;
     RECT  13.745 74.88 15.908 74.904 ;
     RECT  13.504 117.504 15.908 117.528 ;
     RECT  15.908 2.148 16.012 168.492 ;
     RECT  16.012 2.418 16.204 168.222 ;
     RECT  16.204 40.608 18.608 40.632 ;
     RECT  16.204 74.88 18.608 74.904 ;
     RECT  16.204 117.504 18.608 117.528 ;
     RECT  18.608 2.148 18.712 168.492 ;
     RECT  18.712 2.418 18.904 168.222 ;
     RECT  18.904 40.608 21.308 40.632 ;
     RECT  18.904 74.88 21.308 74.904 ;
     RECT  18.904 117.504 21.308 117.528 ;
     RECT  21.308 2.148 21.412 168.492 ;
     RECT  21.412 2.418 21.604 168.222 ;
     RECT  21.604 40.608 21.701 40.728 ;
     RECT  21.604 93.168 22.163 93.336 ;
     RECT  21.604 99.744 22.457 100.008 ;
     RECT  21.604 74.88 22.499 74.904 ;
     RECT  22.163 93.168 22.499 93.192 ;
     RECT  21.701 40.704 22.813 40.728 ;
     RECT  22.813 40.608 22.853 40.728 ;
     RECT  22.853 40.608 24.008 40.632 ;
     RECT  22.457 99.984 24.008 100.008 ;
     RECT  21.604 117.072 24.008 117.528 ;
     RECT  24.008 2.148 24.112 168.492 ;
     RECT  24.112 2.418 24.304 168.222 ;
     RECT  24.304 117.072 24.905 117.528 ;
     RECT  24.304 40.608 26.708 40.632 ;
     RECT  24.304 99.984 26.708 100.008 ;
     RECT  24.905 117.408 26.708 117.432 ;
     RECT  26.708 2.148 26.812 168.492 ;
     RECT  26.812 2.418 27.004 168.222 ;
     RECT  27.004 40.608 29.408 40.632 ;
     RECT  27.004 99.984 29.408 100.008 ;
     RECT  27.004 117.312 29.408 117.336 ;
     RECT  29.408 2.148 29.512 168.492 ;
     RECT  29.512 2.418 29.704 168.222 ;
     RECT  29.704 40.608 29.801 40.728 ;
     RECT  29.801 40.704 30.769 40.728 ;
     RECT  29.704 117.216 30.769 117.24 ;
     RECT  30.769 40.608 30.809 40.728 ;
     RECT  30.769 117.216 30.809 117.336 ;
     RECT  30.809 40.608 32.108 40.632 ;
     RECT  29.704 99.984 32.108 100.008 ;
     RECT  30.809 117.312 32.108 117.336 ;
     RECT  32.108 2.148 32.212 168.492 ;
     RECT  32.212 2.418 32.404 168.222 ;
     RECT  34.549 128.496 34.597 128.52 ;
     RECT  34.549 129.984 34.597 130.008 ;
     RECT  32.404 40.608 34.808 40.632 ;
     RECT  32.404 99.984 34.808 100.008 ;
     RECT  32.404 117.312 34.808 117.336 ;
     RECT  34.597 128.496 34.808 130.008 ;
     RECT  34.693 131.088 34.808 131.112 ;
     RECT  34.808 2.148 34.912 168.492 ;
     RECT  34.912 2.418 35.104 168.222 ;
     RECT  35.104 121.536 35.219 121.56 ;
     RECT  35.104 131.088 35.219 132.024 ;
     RECT  35.104 122.88 35.273 124.536 ;
     RECT  35.219 131.568 35.381 132.024 ;
     RECT  35.104 126.96 35.596 127.416 ;
     RECT  35.273 123.12 35.597 124.536 ;
     RECT  35.381 131.664 35.633 132.024 ;
     RECT  35.104 129.216 35.669 129.24 ;
     RECT  35.597 123.12 35.741 123.144 ;
     RECT  35.104 119.04 36.277 119.688 ;
     RECT  35.104 135.168 36.277 136.056 ;
     RECT  35.633 131.76 36.349 132.024 ;
     RECT  35.104 133.344 36.349 133.368 ;
     RECT  36.277 118.848 36.385 119.688 ;
     RECT  36.277 135.168 36.461 136.536 ;
     RECT  35.597 124.512 36.493 124.536 ;
     RECT  36.385 118.848 36.517 119.976 ;
     RECT  36.476 121.776 36.517 121.8 ;
     RECT  36.461 135.456 36.781 136.536 ;
     RECT  36.493 124.512 36.889 124.92 ;
     RECT  36.349 131.76 36.956 133.368 ;
     RECT  35.596 126.96 36.961 127.08 ;
     RECT  36.517 118.848 36.997 121.8 ;
     RECT  36.925 129.36 37.141 129.912 ;
     RECT  36.889 124.368 37.177 124.92 ;
     RECT  36.961 140.208 37.177 140.232 ;
     RECT  37.177 124.368 37.321 125.208 ;
     RECT  36.781 135.456 37.333 137.352 ;
     RECT  37.177 139.248 37.349 140.232 ;
     RECT  36.997 118.848 37.357 122.664 ;
     RECT  36.961 126.48 37.381 127.08 ;
     RECT  37.349 139.248 37.381 140.904 ;
     RECT  36.956 131.76 37.501 134.28 ;
     RECT  35.104 40.608 37.508 40.632 ;
     RECT  35.104 99.984 37.508 100.008 ;
     RECT  36.565 110.496 37.508 110.52 ;
     RECT  35.104 117.312 37.508 117.336 ;
     RECT  37.357 118.848 37.508 123.336 ;
     RECT  37.321 124.368 37.508 125.4 ;
     RECT  37.381 126.48 37.508 127.896 ;
     RECT  37.141 129.36 37.508 130.248 ;
     RECT  37.501 131.76 37.508 134.328 ;
     RECT  37.333 135.456 37.508 137.688 ;
     RECT  37.381 139.152 37.508 140.904 ;
     RECT  37.349 141.888 37.508 141.912 ;
     RECT  37.381 165.888 37.508 165.912 ;
     RECT  37.508 2.148 37.612 168.492 ;
     RECT  37.612 2.418 37.804 168.222 ;
     RECT  37.804 121.296 37.865 121.368 ;
     RECT  37.804 128.976 37.901 129.144 ;
     RECT  37.825 170.352 37.957 170.376 ;
     RECT  37.804 133.008 37.973 135.48 ;
     RECT  37.804 99.984 38.003 100.008 ;
     RECT  37.957 170.352 38.044 170.52 ;
     RECT  37.804 139.152 38.099 140.04 ;
     RECT  37.901 129.12 38.147 129.144 ;
     RECT  38.044 170.352 38.153 170.472 ;
     RECT  37.804 127.056 38.189 127.224 ;
     RECT  37.804 130.464 38.225 131.88 ;
     RECT  37.804 142.896 38.225 144.12 ;
     RECT  37.804 53.568 38.339 53.592 ;
     RECT  37.804 52.08 38.38 52.392 ;
     RECT  37.804 148.224 38.449 148.488 ;
     RECT  37.804 122.496 38.477 125.4 ;
     RECT  37.865 121.296 38.483 121.32 ;
     RECT  37.804 117.312 38.531 117.336 ;
     RECT  37.804 119.088 38.585 119.112 ;
     RECT  38.225 143.904 38.627 144.12 ;
     RECT  37.804 145.44 38.627 145.464 ;
     RECT  38.225 130.464 38.657 131.64 ;
     RECT  37.804 164.448 38.723 164.472 ;
     RECT  37.804 166.32 38.723 166.344 ;
     RECT  37.804 162.288 38.737 162.456 ;
     RECT  37.804 136.512 38.771 136.536 ;
     RECT  38.449 148.464 38.771 148.488 ;
     RECT  38.737 162.288 38.771 162.312 ;
     RECT  37.973 133.008 38.801 134.808 ;
     RECT  37.804 167.616 38.801 167.64 ;
     RECT  38.801 133.632 38.812 134.808 ;
     RECT  38.38 52.368 38.905 52.392 ;
     RECT  37.804 91.2 38.905 91.224 ;
     RECT  38.905 52.368 38.989 52.44 ;
     RECT  38.905 91.2 39.085 91.704 ;
     RECT  37.804 93.216 39.085 95.016 ;
     RECT  38.477 123.936 39.157 125.4 ;
     RECT  38.189 127.2 39.157 127.224 ;
     RECT  38.627 143.904 39.197 143.928 ;
     RECT  38.225 142.896 39.404 142.92 ;
     RECT  37.804 105.984 39.445 106.584 ;
     RECT  38.153 170.448 39.491 170.472 ;
     RECT  39.121 121.968 39.548 121.992 ;
     RECT  38.099 139.152 39.548 139.176 ;
     RECT  39.481 89.424 39.589 89.448 ;
     RECT  39.589 88.896 39.625 89.448 ;
     RECT  38.812 134.256 39.692 134.808 ;
     RECT  38.797 50.928 39.74 50.952 ;
     RECT  39.481 48.192 39.769 48.216 ;
     RECT  39.553 49.536 39.769 49.56 ;
     RECT  39.74 50.928 39.769 51.384 ;
     RECT  37.804 96.864 39.769 96.888 ;
     RECT  37.804 40.608 39.781 40.632 ;
     RECT  39.625 88.896 39.781 89.832 ;
     RECT  39.445 105.936 39.829 106.584 ;
     RECT  39.781 88.224 39.841 89.832 ;
     RECT  39.085 91.2 39.841 95.016 ;
     RECT  39.769 48.192 39.877 51.384 ;
     RECT  39.692 134.256 39.877 135.672 ;
     RECT  39.841 88.224 40.057 95.016 ;
     RECT  37.804 109.152 40.069 109.176 ;
     RECT  39.781 40.608 40.208 41.112 ;
     RECT  39.697 43.536 40.208 43.56 ;
     RECT  39.877 47.952 40.208 51.384 ;
     RECT  38.989 52.368 40.208 52.392 ;
     RECT  38.917 60.672 40.208 60.696 ;
     RECT  40.057 87.648 40.208 95.016 ;
     RECT  39.769 96.048 40.208 96.888 ;
     RECT  39.829 105.84 40.208 106.584 ;
     RECT  40.069 108.96 40.208 109.176 ;
     RECT  37.804 110.496 40.208 110.52 ;
     RECT  39.589 120.576 40.208 120.6 ;
     RECT  39.548 121.632 40.208 121.992 ;
     RECT  39.157 123.936 40.208 127.224 ;
     RECT  40.165 128.256 40.208 128.616 ;
     RECT  38.657 130.464 40.208 130.488 ;
     RECT  39.373 131.664 40.208 131.688 ;
     RECT  39.877 134.256 40.208 135.864 ;
     RECT  39.553 136.944 40.208 137.832 ;
     RECT  39.548 139.152 40.208 139.704 ;
     RECT  39.404 142.896 40.208 143.304 ;
     RECT  40.208 2.148 40.312 168.492 ;
     RECT  40.312 2.418 40.504 168.222 ;
     RECT  40.504 109.968 40.643 110.52 ;
     RECT  40.504 113.424 40.643 113.448 ;
     RECT  40.504 120.192 40.643 120.6 ;
     RECT  40.504 40.608 40.673 40.632 ;
     RECT  40.504 121.92 40.745 122.664 ;
     RECT  40.504 142.368 40.745 143.16 ;
     RECT  40.504 123.696 40.817 127.08 ;
     RECT  40.745 142.512 40.889 143.16 ;
     RECT  40.504 137.376 40.925 140.184 ;
     RECT  40.889 142.944 40.925 143.16 ;
     RECT  40.504 102 40.979 102.024 ;
     RECT  40.504 98.64 40.997 98.664 ;
     RECT  40.504 100.272 41.027 100.296 ;
     RECT  40.925 143.136 41.033 143.16 ;
     RECT  40.817 123.696 41.315 123.72 ;
     RECT  40.745 122.496 41.357 122.664 ;
     RECT  40.504 114.528 41.465 114.936 ;
     RECT  40.817 124.8 41.507 127.08 ;
     RECT  41.497 46.752 41.533 46.776 ;
     RECT  40.504 131.52 41.533 131.544 ;
     RECT  40.643 120.192 41.537 120.216 ;
     RECT  41.507 125.424 41.548 127.08 ;
     RECT  40.925 137.376 41.605 138.552 ;
     RECT  41.548 126.576 41.645 127.08 ;
     RECT  41.533 131.52 41.677 132.216 ;
     RECT  41.533 45.792 41.713 46.776 ;
     RECT  40.504 134.208 41.713 135 ;
     RECT  41.677 131.52 41.749 132.792 ;
     RECT  41.713 134.112 41.749 135 ;
     RECT  41.465 114.528 41.833 114.6 ;
     RECT  41.749 131.52 41.857 135 ;
     RECT  41.821 40.464 41.893 40.488 ;
     RECT  41.749 84.336 41.941 84.36 ;
     RECT  40.504 87.648 41.941 96.984 ;
     RECT  41.713 45.6 41.965 46.776 ;
     RECT  40.504 47.808 41.965 53.784 ;
     RECT  41.965 45.6 42.037 53.784 ;
     RECT  41.857 131.136 42.037 135 ;
     RECT  41.569 44.352 42.109 44.376 ;
     RECT  42.037 45.408 42.109 53.784 ;
     RECT  41.941 87.264 42.133 96.984 ;
     RECT  42.037 130.56 42.145 135 ;
     RECT  41.605 137.28 42.145 138.552 ;
     RECT  40.925 139.776 42.145 140.184 ;
     RECT  41.357 122.544 42.181 122.664 ;
     RECT  41.857 120.816 42.217 120.84 ;
     RECT  42.145 130.56 42.253 135.288 ;
     RECT  42.253 130.56 42.289 135.384 ;
     RECT  41.893 40.464 42.325 40.584 ;
     RECT  42.133 39.312 42.353 39.336 ;
     RECT  42.325 40.416 42.353 40.584 ;
     RECT  41.941 83.616 42.373 84.36 ;
     RECT  42.217 120.816 42.373 121.368 ;
     RECT  42.109 44.352 42.421 53.784 ;
     RECT  40.504 103.776 42.421 104.376 ;
     RECT  42.421 44.256 42.469 53.784 ;
     RECT  42.373 129.168 42.469 129.192 ;
     RECT  42.373 120.816 42.505 121.464 ;
     RECT  42.181 122.544 42.505 123.24 ;
     RECT  40.504 147.12 42.505 147.768 ;
     RECT  42.469 129.168 42.515 129.288 ;
     RECT  42.505 120.816 42.517 123.24 ;
     RECT  42.133 64.704 42.565 64.728 ;
     RECT  42.517 120.816 42.565 123.288 ;
     RECT  42.277 124.272 42.565 124.296 ;
     RECT  42.469 44.16 42.661 53.784 ;
     RECT  42.515 129.264 42.661 129.288 ;
     RECT  42.661 129.264 42.707 129.432 ;
     RECT  42.565 64.704 42.709 64.92 ;
     RECT  42.565 107.28 42.709 107.304 ;
     RECT  42.707 129.312 42.709 129.432 ;
     RECT  42.289 130.56 42.709 135.48 ;
     RECT  41.645 126.576 42.757 126.6 ;
     RECT  42.757 126.576 42.793 126.888 ;
     RECT  42.709 129.312 42.869 135.48 ;
     RECT  42.661 43.968 42.901 53.784 ;
     RECT  42.869 129.408 42.905 135.48 ;
     RECT  42.517 33.648 42.908 33.672 ;
     RECT  42.605 37.92 42.908 37.944 ;
     RECT  42.353 39.312 42.908 40.584 ;
     RECT  42.709 64.608 42.908 64.92 ;
     RECT  42.373 83.52 42.908 84.36 ;
     RECT  40.504 105.936 42.908 105.96 ;
     RECT  42.709 107.28 42.908 108.648 ;
     RECT  40.643 110.496 42.908 110.52 ;
     RECT  42.101 114.432 42.908 114.456 ;
     RECT  42.661 119.664 42.908 119.688 ;
     RECT  42.565 120.816 42.908 124.296 ;
     RECT  41.548 125.424 42.908 125.496 ;
     RECT  42.793 126.576 42.908 127.368 ;
     RECT  42.908 2.148 43.012 41.052 ;
     RECT  42.908 62.628 43.012 84.36 ;
     RECT  42.908 105.828 43.012 127.452 ;
     RECT  42.908 149.028 43.012 168.492 ;
     RECT  43.012 105.936 43.085 127.368 ;
     RECT  42.905 129.456 43.2 135.48 ;
     RECT  42.145 137.28 43.2 140.184 ;
     RECT  43.012 2.418 43.204 40.782 ;
     RECT  43.012 62.898 43.204 84.36 ;
     RECT  43.085 105.936 43.204 127.182 ;
     RECT  43.012 149.298 43.204 168.222 ;
     RECT  43.204 83.664 43.229 84.36 ;
     RECT  43.204 107.28 43.265 108.648 ;
     RECT  42.901 43.968 43.272 54.12 ;
     RECT  40.504 60.672 43.272 61.032 ;
     RECT  40.504 86.016 43.272 86.04 ;
     RECT  42.133 87.168 43.272 96.984 ;
     RECT  42.421 103.2 43.272 104.376 ;
     RECT  43.2 129.456 43.272 140.184 ;
     RECT  42.505 147.072 43.272 147.768 ;
     RECT  43.272 129.456 43.331 147.768 ;
     RECT  43.204 64.608 43.372 64.968 ;
     RECT  43.265 107.952 43.409 108.648 ;
     RECT  43.372 64.608 43.553 64.728 ;
     RECT  43.229 83.664 43.553 84.12 ;
     RECT  43.204 105.936 45.608 105.96 ;
     RECT  43.204 110.496 45.608 110.52 ;
     RECT  45.608 2.148 45.712 41.052 ;
     RECT  45.608 62.628 45.712 84.252 ;
     RECT  45.608 105.828 45.712 127.452 ;
     RECT  45.608 149.028 45.712 168.492 ;
     RECT  45.712 2.418 45.904 40.782 ;
     RECT  45.712 62.898 45.904 83.982 ;
     RECT  45.712 105.936 45.904 127.182 ;
     RECT  45.712 149.298 45.904 168.222 ;
     RECT  45.904 105.936 48.308 105.96 ;
     RECT  45.904 110.496 48.308 110.52 ;
     RECT  48.308 2.148 48.412 41.052 ;
     RECT  48.308 62.628 48.412 84.252 ;
     RECT  48.308 105.828 48.412 127.452 ;
     RECT  48.308 149.028 48.412 168.492 ;
     RECT  48.412 2.418 48.604 40.782 ;
     RECT  48.412 62.898 48.604 83.982 ;
     RECT  48.412 105.936 48.604 127.182 ;
     RECT  48.412 149.298 48.604 168.222 ;
     RECT  48.604 105.936 51.008 105.96 ;
     RECT  48.604 110.496 51.008 110.52 ;
     RECT  51.008 2.148 51.112 41.052 ;
     RECT  51.008 62.628 51.112 84.252 ;
     RECT  51.008 105.828 51.112 127.452 ;
     RECT  51.008 149.028 51.112 168.492 ;
     RECT  51.112 2.418 51.304 40.782 ;
     RECT  51.112 62.898 51.304 83.982 ;
     RECT  51.112 105.936 51.304 127.182 ;
     RECT  51.112 149.298 51.304 168.222 ;
     RECT  51.304 105.936 53.708 105.96 ;
     RECT  51.304 110.496 53.708 110.52 ;
     RECT  53.708 2.148 53.812 41.052 ;
     RECT  53.708 62.628 53.812 84.252 ;
     RECT  53.708 105.828 53.812 127.452 ;
     RECT  53.708 149.028 53.812 168.492 ;
     RECT  53.812 2.418 54.004 40.782 ;
     RECT  53.812 62.898 54.004 83.982 ;
     RECT  53.812 105.936 54.004 127.182 ;
     RECT  53.812 149.298 54.004 168.222 ;
     RECT  54.004 105.936 56.408 105.96 ;
     RECT  54.004 110.496 56.408 110.52 ;
     RECT  56.408 2.148 56.512 41.052 ;
     RECT  56.408 62.628 56.512 84.252 ;
     RECT  56.408 105.828 56.512 127.452 ;
     RECT  56.408 149.028 56.512 168.492 ;
     RECT  56.512 2.418 56.704 40.782 ;
     RECT  56.512 62.898 56.704 83.982 ;
     RECT  56.512 105.936 56.704 127.182 ;
     RECT  56.512 149.298 56.704 168.222 ;
     RECT  56.704 105.936 59.108 105.96 ;
     RECT  56.704 110.496 59.108 110.52 ;
     RECT  59.108 2.148 59.212 41.052 ;
     RECT  59.108 62.628 59.212 84.252 ;
     RECT  59.108 105.828 59.212 127.452 ;
     RECT  59.108 149.028 59.212 168.492 ;
     RECT  59.212 2.418 59.404 40.782 ;
     RECT  59.212 62.898 59.404 83.982 ;
     RECT  59.212 105.936 59.404 127.182 ;
     RECT  59.212 149.298 59.404 168.222 ;
     RECT  59.404 105.936 61.808 105.96 ;
     RECT  59.404 110.496 61.808 110.52 ;
     RECT  61.808 2.148 61.912 41.052 ;
     RECT  61.808 62.628 61.912 84.252 ;
     RECT  61.808 105.828 61.912 127.452 ;
     RECT  61.808 149.028 61.912 168.492 ;
     RECT  61.912 2.418 62.104 40.782 ;
     RECT  61.912 62.898 62.104 83.982 ;
     RECT  61.912 105.936 62.104 127.182 ;
     RECT  61.912 149.298 62.104 168.222 ;
     RECT  62.104 105.936 64.508 105.96 ;
     RECT  62.104 110.496 64.508 110.52 ;
     RECT  64.508 2.148 64.612 41.052 ;
     RECT  64.508 62.628 64.612 84.252 ;
     RECT  64.508 105.828 64.612 127.452 ;
     RECT  64.508 149.028 64.612 168.492 ;
     RECT  64.612 62.898 64.717 84.252 ;
     RECT  64.612 2.418 64.804 40.782 ;
     RECT  64.717 62.898 64.804 84.36 ;
     RECT  64.612 105.828 64.804 127.182 ;
     RECT  64.612 149.298 64.804 168.222 ;
     RECT  64.804 84.336 65.123 84.36 ;
     RECT  65.077 105.456 65.161 105.48 ;
     RECT  66.277 73.824 67.208 73.848 ;
     RECT  66.236 84.096 67.208 84.12 ;
     RECT  64.804 110.016 67.208 110.52 ;
     RECT  66.277 126.144 67.208 126.168 ;
     RECT  67.208 2.148 67.312 41.052 ;
     RECT  67.208 62.628 67.312 84.252 ;
     RECT  67.208 105.828 67.312 127.452 ;
     RECT  67.208 149.028 67.312 168.492 ;
     RECT  67.312 2.418 67.504 40.782 ;
     RECT  67.312 62.898 67.504 83.982 ;
     RECT  67.312 106.098 67.504 127.182 ;
     RECT  67.312 149.298 67.504 168.222 ;
     RECT  67.504 73.824 69.908 73.848 ;
     RECT  67.504 126.144 69.908 126.168 ;
     RECT  69.908 2.148 70.012 41.052 ;
     RECT  69.908 62.628 70.012 84.252 ;
     RECT  69.908 105.828 70.012 127.452 ;
     RECT  69.908 149.028 70.012 168.492 ;
     RECT  70.012 2.418 70.204 40.782 ;
     RECT  70.012 62.898 70.204 83.982 ;
     RECT  70.012 106.098 70.204 127.182 ;
     RECT  70.012 149.298 70.204 168.222 ;
     RECT  70.204 73.824 72.608 73.848 ;
     RECT  70.204 126.144 72.608 126.168 ;
     RECT  72.608 2.148 72.712 41.052 ;
     RECT  72.608 62.628 72.712 84.252 ;
     RECT  72.608 105.828 72.712 127.452 ;
     RECT  72.608 149.028 72.712 168.492 ;
     RECT  72.712 2.418 72.904 40.782 ;
     RECT  72.712 62.898 72.904 83.982 ;
     RECT  72.712 106.098 72.904 127.182 ;
     RECT  72.712 149.298 72.904 168.222 ;
     RECT  72.904 126.144 74.077 126.168 ;
     RECT  43.272 43.2 75.12 61.032 ;
     RECT  43.272 86.016 75.12 104.376 ;
     RECT  43.331 129.6 75.12 147.768 ;
     RECT  75.12 43.2 75.157 53.88 ;
     RECT  75.116 41.616 75.203 41.64 ;
     RECT  74.077 125.952 75.301 126.168 ;
     RECT  75.157 43.056 75.305 53.88 ;
     RECT  75.12 87.168 75.305 96.984 ;
     RECT  72.904 73.824 75.308 73.848 ;
     RECT  75.301 125.952 75.308 126.456 ;
     RECT  74.509 128.256 75.308 128.28 ;
     RECT  75.305 44.064 75.341 53.88 ;
     RECT  75.341 44.064 75.377 53.688 ;
     RECT  75.308 2.148 75.412 41.052 ;
     RECT  75.308 62.628 75.412 84.252 ;
     RECT  75.308 105.828 75.412 128.28 ;
     RECT  75.308 149.028 75.412 168.492 ;
     RECT  75.305 43.056 75.413 43.08 ;
     RECT  75.12 130.32 75.413 140.184 ;
     RECT  75.305 87.264 75.485 96.984 ;
     RECT  75.413 130.32 75.557 139.896 ;
     RECT  75.485 87.264 75.593 96.696 ;
     RECT  75.412 2.418 75.604 40.782 ;
     RECT  75.412 62.898 75.604 84.168 ;
     RECT  75.412 106.098 75.604 128.28 ;
     RECT  75.412 149.298 75.604 168.222 ;
     RECT  75.557 130.32 75.629 139.8 ;
     RECT  75.377 44.064 75.665 53.592 ;
     RECT  75.604 83.76 75.731 84.168 ;
     RECT  75.604 125.712 75.731 128.28 ;
     RECT  75.665 44.064 75.737 53.496 ;
     RECT  75.731 125.712 75.772 127.128 ;
     RECT  75.772 125.712 75.779 126.456 ;
     RECT  75.779 125.712 75.827 126.168 ;
     RECT  75.731 128.16 75.827 128.28 ;
     RECT  75.629 130.32 76.745 139.704 ;
     RECT  75.604 73.824 76.849 73.848 ;
     RECT  75.827 125.952 76.94 126.168 ;
     RECT  75.737 44.064 76.997 53.4 ;
     RECT  76.94 125.952 76.997 126.36 ;
     RECT  76.997 126.144 77.027 126.36 ;
     RECT  76.849 73.824 77.132 74.28 ;
     RECT  76.997 44.064 78.008 53.304 ;
     RECT  75.12 60.672 78.008 61.032 ;
     RECT  77.132 73.728 78.008 74.28 ;
     RECT  75.731 84.048 78.008 84.168 ;
     RECT  75.12 86.016 78.008 86.04 ;
     RECT  75.593 87.264 78.008 96.6 ;
     RECT  75.12 103.776 78.008 104.376 ;
     RECT  77.027 126.144 78.008 126.168 ;
     RECT  76.745 130.32 78.008 133.944 ;
     RECT  76.745 134.976 78.008 139.704 ;
     RECT  75.12 147.072 78.008 147.768 ;
     RECT  78.008 2.148 78.112 168.492 ;
     RECT  78.112 2.418 78.304 168.222 ;
     RECT  78.304 86.016 78.941 86.04 ;
     RECT  78.304 44.064 80.708 47.64 ;
     RECT  78.304 60.672 80.708 60.696 ;
     RECT  78.304 84.048 80.708 84.168 ;
     RECT  78.304 87.264 80.708 90.888 ;
     RECT  78.304 103.776 80.708 104.328 ;
     RECT  78.304 126.144 80.708 126.168 ;
     RECT  78.304 130.32 80.708 132.408 ;
     RECT  78.304 147.072 80.708 147.768 ;
     RECT  80.708 2.148 80.812 168.492 ;
     RECT  80.812 2.418 81.004 168.222 ;
     RECT  81.004 44.064 81.245 47.64 ;
     RECT  81.004 87.264 82.321 90.888 ;
     RECT  81.245 44.064 83.408 47.448 ;
     RECT  81.004 60.672 83.408 60.696 ;
     RECT  81.004 84.048 83.408 84.168 ;
     RECT  82.321 86.544 83.408 90.888 ;
     RECT  81.004 103.776 83.408 104.328 ;
     RECT  81.004 126.144 83.408 126.168 ;
     RECT  81.004 130.32 83.408 132.408 ;
     RECT  81.004 147.072 83.408 147.768 ;
     RECT  83.408 2.148 83.512 168.492 ;
     RECT  83.512 2.418 83.704 168.222 ;
     RECT  83.704 130.32 83.837 132.408 ;
     RECT  83.704 44.064 86.108 47.448 ;
     RECT  83.704 60.672 86.108 60.696 ;
     RECT  83.704 83.76 86.108 84.36 ;
     RECT  83.704 86.544 86.108 90.888 ;
     RECT  83.704 103.776 86.108 104.328 ;
     RECT  83.704 126.144 86.108 126.168 ;
     RECT  83.837 130.464 86.108 132.408 ;
     RECT  83.704 147.072 86.108 147.768 ;
     RECT  86.108 2.148 86.212 168.492 ;
     RECT  86.212 2.418 86.404 168.222 ;
     RECT  86.404 85.92 87.257 90.888 ;
     RECT  88.685 82.704 88.693 82.728 ;
     RECT  86.404 44.352 88.808 47.448 ;
     RECT  86.404 60.672 88.808 60.696 ;
     RECT  88.693 81.984 88.808 82.728 ;
     RECT  86.404 83.76 88.808 84.36 ;
     RECT  87.257 85.92 88.808 85.944 ;
     RECT  87.257 87.264 88.808 90.888 ;
     RECT  86.404 103.776 88.808 104.328 ;
     RECT  86.404 126.144 88.808 126.168 ;
     RECT  86.404 130.464 88.808 132.264 ;
     RECT  86.404 147.072 88.808 147.768 ;
     RECT  88.808 2.148 88.912 168.492 ;
     RECT  88.912 2.418 89.104 168.222 ;
     RECT  89.104 81.84 89.201 82.008 ;
     RECT  89.104 44.352 89.417 47.448 ;
     RECT  89.417 44.352 89.489 47.352 ;
     RECT  89.104 87.264 89.525 90.888 ;
     RECT  89.104 143.088 89.533 143.112 ;
     RECT  89.104 39.264 89.597 39.96 ;
     RECT  89.525 87.648 89.777 90.888 ;
     RECT  89.489 44.352 89.921 47.064 ;
     RECT  89.104 125.904 90.083 126.696 ;
     RECT  89.104 43.296 90.097 43.32 ;
     RECT  90.097 42.72 90.137 43.32 ;
     RECT  89.104 56.4 90.137 56.424 ;
     RECT  89.104 141.888 90.137 141.912 ;
     RECT  90.169 140.4 90.205 140.424 ;
     RECT  89.104 97.44 90.277 97.464 ;
     RECT  89.104 98.88 90.281 98.904 ;
     RECT  89.201 81.84 90.385 81.864 ;
     RECT  89.104 54.096 90.497 54.12 ;
     RECT  89.104 85.776 90.529 85.944 ;
     RECT  89.104 60.672 91.045 60.696 ;
     RECT  89.104 130.464 91.093 131.64 ;
     RECT  91.045 58.56 91.141 58.584 ;
     RECT  90.205 139.488 91.141 140.424 ;
     RECT  90.137 42.72 91.249 42.744 ;
     RECT  90.493 56.832 91.381 56.952 ;
     RECT  89.597 39.936 91.508 39.96 ;
     RECT  91.349 40.992 91.508 41.016 ;
     RECT  91.249 42.192 91.508 42.744 ;
     RECT  89.921 44.352 91.508 46.584 ;
     RECT  91.141 48.432 91.508 48.456 ;
     RECT  90.493 52.704 91.508 52.728 ;
     RECT  89.104 55.152 91.508 55.176 ;
     RECT  91.381 56.352 91.508 56.952 ;
     RECT  91.141 58.08 91.508 58.584 ;
     RECT  91.045 60.672 91.508 60.792 ;
     RECT  90.385 81.84 91.508 82.632 ;
     RECT  89.104 83.76 91.508 84.36 ;
     RECT  90.529 85.776 91.508 85.992 ;
     RECT  89.777 87.84 91.508 90.888 ;
     RECT  90.277 96.864 91.508 97.464 ;
     RECT  89.104 100.32 91.508 100.344 ;
     RECT  89.104 103.776 91.508 104.328 ;
     RECT  90.083 125.904 91.508 126.168 ;
     RECT  91.093 130.464 91.508 132.552 ;
     RECT  91.141 139.488 91.508 140.808 ;
     RECT  89.104 147.072 91.508 147.768 ;
     RECT  91.508 2.148 91.612 168.492 ;
     RECT  91.612 2.418 91.804 168.222 ;
     RECT  91.804 44.352 91.865 45.192 ;
     RECT  91.804 56.4 91.865 56.856 ;
     RECT  91.804 87.84 92.045 90.552 ;
     RECT  91.804 52.704 92.081 54.6 ;
     RECT  92.045 88.176 92.297 90.552 ;
     RECT  92.297 88.176 92.333 90.264 ;
     RECT  91.804 42.192 92.405 42.36 ;
     RECT  91.804 84.096 92.405 84.168 ;
     RECT  91.804 85.488 92.579 85.944 ;
     RECT  91.804 93.408 92.62 94.056 ;
     RECT  92.333 88.176 92.621 89.784 ;
     RECT  92.62 94.032 92.627 94.056 ;
     RECT  91.804 99.792 92.627 100.776 ;
     RECT  91.804 139.968 92.657 140.808 ;
     RECT  91.804 96.72 92.693 97.224 ;
     RECT  91.804 125.616 92.771 127.176 ;
     RECT  91.804 130.464 92.771 132.216 ;
     RECT  92.771 130.464 92.801 131.352 ;
     RECT  91.804 39.888 92.869 39.912 ;
     RECT  91.804 82.656 92.905 82.68 ;
     RECT  92.657 140.208 92.905 140.808 ;
     RECT  91.804 143.088 92.905 143.112 ;
     RECT  92.621 88.704 92.909 89.784 ;
     RECT  92.405 84.096 92.945 84.12 ;
     RECT  92.081 52.992 93.011 54.6 ;
     RECT  92.627 99.792 93.013 99.816 ;
     RECT  93.013 99.696 93.053 99.816 ;
     RECT  92.801 130.848 93.089 131.352 ;
     RECT  92.905 82.656 93.373 82.968 ;
     RECT  93.365 98.592 93.404 98.616 ;
     RECT  92.869 39.888 93.445 40.392 ;
     RECT  91.804 48.432 93.445 48.456 ;
     RECT  92.693 96.72 93.445 96.936 ;
     RECT  93.011 53.52 93.493 54.6 ;
     RECT  92.579 85.488 93.548 85.512 ;
     RECT  92.405 42.336 93.553 42.36 ;
     RECT  92.771 127.152 93.553 127.176 ;
     RECT  93.445 39.504 93.589 40.392 ;
     RECT  93.548 85.488 93.589 86.04 ;
     RECT  93.553 42.288 93.836 42.744 ;
     RECT  91.865 44.4 93.836 45.192 ;
     RECT  93.373 82.08 94.021 82.968 ;
     RECT  93.493 53.52 94.165 55.32 ;
     RECT  94.021 82.08 94.165 83.256 ;
     RECT  93.445 84.384 94.165 84.408 ;
     RECT  93.589 39.504 94.208 40.44 ;
     RECT  93.836 42.288 94.208 45.192 ;
     RECT  93.445 48.432 94.208 48.696 ;
     RECT  94.165 52.8 94.208 55.32 ;
     RECT  91.865 56.4 94.208 56.424 ;
     RECT  94.165 82.08 94.208 84.408 ;
     RECT  93.589 85.488 94.208 86.664 ;
     RECT  92.909 88.704 94.208 89.256 ;
     RECT  93.445 96.288 94.208 96.936 ;
     RECT  93.404 98.304 94.208 98.616 ;
     RECT  93.053 99.696 94.208 99.72 ;
     RECT  91.804 103.776 94.208 104.328 ;
     RECT  92.771 125.616 94.208 126.024 ;
     RECT  93.553 127.152 94.208 127.368 ;
     RECT  93.089 131.328 94.208 131.352 ;
     RECT  92.905 140.208 94.208 141.144 ;
     RECT  92.905 142.704 94.208 143.112 ;
     RECT  91.804 147.072 94.208 147.768 ;
     RECT  94.208 2.148 94.312 168.492 ;
     RECT  94.312 2.418 94.504 168.222 ;
     RECT  94.504 45.168 94.601 45.192 ;
     RECT  94.504 125.856 94.601 126.024 ;
     RECT  94.504 127.344 94.709 127.368 ;
     RECT  94.504 147.072 94.745 147.768 ;
     RECT  94.504 103.776 95.033 104.328 ;
     RECT  95.033 104.304 95.069 104.328 ;
     RECT  94.504 48.432 95.075 48.696 ;
     RECT  94.504 52.368 95.075 54.168 ;
     RECT  94.745 147.072 95.249 147.096 ;
     RECT  94.504 41.616 95.569 41.64 ;
     RECT  94.504 81.504 95.677 84.408 ;
     RECT  95.569 41.616 95.713 41.784 ;
     RECT  95.677 42.768 95.713 42.792 ;
     RECT  94.504 141.696 95.713 142.632 ;
     RECT  94.504 55.728 95.749 56.184 ;
     RECT  95.677 81.504 95.749 85.272 ;
     RECT  94.504 98.064 95.749 99.528 ;
     RECT  94.504 100.656 95.749 100.68 ;
     RECT  94.504 138.96 95.749 139.416 ;
     RECT  94.504 38.88 95.785 40.632 ;
     RECT  95.713 41.616 95.785 42.792 ;
     RECT  94.504 96.336 95.785 96.648 ;
     RECT  95.749 98.064 95.785 100.68 ;
     RECT  94.601 125.856 95.785 125.88 ;
     RECT  95.785 38.88 95.893 42.792 ;
     RECT  95.075 52.704 95.893 54.168 ;
     RECT  95.749 81.504 95.893 85.416 ;
     RECT  95.785 125.856 95.893 126.312 ;
     RECT  95.749 138.96 95.893 140.28 ;
     RECT  95.713 141.696 95.893 143.016 ;
     RECT  95.893 52.704 96.289 54.312 ;
     RECT  95.749 55.728 96.289 56.76 ;
     RECT  95.893 81.504 96.289 85.848 ;
     RECT  95.893 138.96 96.289 143.016 ;
     RECT  96.289 52.704 96.325 57.048 ;
     RECT  95.893 125.856 96.325 126.888 ;
     RECT  95.893 38.88 96.901 43.224 ;
     RECT  95.785 96.336 96.901 100.68 ;
     RECT  96.325 125.712 96.901 126.888 ;
     RECT  96.901 125.568 97.477 126.888 ;
     RECT  96.289 138.96 97.513 143.304 ;
     RECT  96.901 38.736 98.196 38.76 ;
     RECT  96.901 38.76 98.22 38.88 ;
     RECT  96.901 38.88 98.196 38.904 ;
     RECT  96.901 38.904 98.22 39.024 ;
     RECT  96.901 39.024 98.196 39.048 ;
     RECT  96.901 39.048 98.22 39.168 ;
     RECT  96.901 39.168 98.196 39.192 ;
     RECT  96.901 39.192 98.22 39.312 ;
     RECT  96.901 39.312 98.196 39.336 ;
     RECT  96.901 39.336 98.22 39.456 ;
     RECT  96.901 39.456 98.196 39.48 ;
     RECT  96.901 39.48 98.22 39.6 ;
     RECT  96.901 39.6 98.196 39.624 ;
     RECT  96.901 39.624 98.22 39.744 ;
     RECT  96.901 39.744 98.196 39.768 ;
     RECT  96.901 39.768 98.22 39.888 ;
     RECT  96.901 39.888 98.196 39.912 ;
     RECT  96.901 39.912 98.22 40.032 ;
     RECT  96.901 40.032 98.196 40.056 ;
     RECT  96.901 40.056 98.22 40.176 ;
     RECT  96.901 40.176 98.196 40.2 ;
     RECT  96.901 40.2 98.22 40.32 ;
     RECT  96.901 40.32 98.196 40.344 ;
     RECT  96.901 40.344 98.22 40.464 ;
     RECT  96.901 40.464 98.196 40.488 ;
     RECT  96.901 40.488 98.22 40.608 ;
     RECT  96.901 40.608 98.196 40.632 ;
     RECT  96.901 40.632 98.22 40.752 ;
     RECT  96.901 40.752 98.196 40.776 ;
     RECT  96.901 40.776 98.22 40.896 ;
     RECT  96.901 40.896 98.196 40.92 ;
     RECT  96.901 40.92 98.22 41.04 ;
     RECT  96.901 41.04 98.196 41.064 ;
     RECT  96.901 41.064 98.22 41.184 ;
     RECT  96.901 41.184 98.196 41.208 ;
     RECT  96.901 41.208 98.22 41.328 ;
     RECT  96.901 41.328 98.196 41.352 ;
     RECT  96.901 41.352 98.22 41.472 ;
     RECT  96.901 41.472 98.196 41.496 ;
     RECT  96.901 41.496 98.22 41.616 ;
     RECT  96.901 41.616 98.196 41.64 ;
     RECT  96.901 41.64 98.22 41.76 ;
     RECT  96.901 41.76 98.196 41.784 ;
     RECT  96.901 41.784 98.22 41.904 ;
     RECT  96.901 41.904 98.196 41.928 ;
     RECT  96.901 41.928 98.22 42.048 ;
     RECT  96.901 42.048 98.196 42.072 ;
     RECT  96.901 42.072 98.22 42.192 ;
     RECT  96.901 42.192 98.196 42.216 ;
     RECT  96.901 42.216 98.22 42.336 ;
     RECT  96.901 42.336 98.196 42.36 ;
     RECT  96.901 42.36 98.22 42.48 ;
     RECT  96.901 42.48 98.196 42.504 ;
     RECT  96.901 42.504 98.22 42.624 ;
     RECT  96.901 42.624 98.196 42.648 ;
     RECT  96.901 42.648 98.22 42.768 ;
     RECT  96.901 42.768 98.196 42.792 ;
     RECT  96.901 42.792 98.22 42.912 ;
     RECT  96.901 42.912 98.196 42.936 ;
     RECT  96.901 42.936 98.22 43.056 ;
     RECT  96.901 43.056 98.196 43.08 ;
     RECT  96.901 43.08 98.22 43.2 ;
     RECT  96.901 43.2 98.196 43.224 ;
     RECT  96.325 52.56 98.196 52.584 ;
     RECT  96.325 52.584 98.22 52.704 ;
     RECT  96.325 52.704 98.196 52.728 ;
     RECT  96.325 52.728 98.22 52.848 ;
     RECT  96.325 52.848 98.196 52.872 ;
     RECT  96.325 52.872 98.22 52.992 ;
     RECT  96.325 52.992 98.196 53.016 ;
     RECT  96.325 53.016 98.22 53.136 ;
     RECT  96.325 53.136 98.196 53.16 ;
     RECT  96.325 53.16 98.22 53.28 ;
     RECT  96.325 53.28 98.196 53.304 ;
     RECT  96.325 53.304 98.22 53.424 ;
     RECT  96.325 53.424 98.196 53.448 ;
     RECT  96.325 53.448 98.22 53.568 ;
     RECT  96.325 53.568 98.196 53.592 ;
     RECT  96.325 53.592 98.22 53.712 ;
     RECT  96.325 53.712 98.196 53.736 ;
     RECT  96.325 53.736 98.22 53.856 ;
     RECT  96.325 53.856 98.196 53.88 ;
     RECT  96.325 53.88 98.22 54 ;
     RECT  96.325 54 98.196 54.024 ;
     RECT  96.325 54.024 98.22 54.144 ;
     RECT  96.325 54.144 98.196 54.168 ;
     RECT  96.325 54.168 98.22 54.288 ;
     RECT  96.325 54.288 98.196 54.312 ;
     RECT  96.325 54.312 98.22 54.432 ;
     RECT  96.325 54.432 98.196 54.456 ;
     RECT  96.325 54.456 98.22 54.576 ;
     RECT  96.325 54.576 98.196 54.6 ;
     RECT  96.325 54.6 98.22 54.72 ;
     RECT  96.325 54.72 98.196 54.744 ;
     RECT  96.325 54.744 98.22 54.864 ;
     RECT  96.325 54.864 98.196 54.888 ;
     RECT  96.325 54.888 98.22 55.008 ;
     RECT  96.325 55.008 98.196 55.032 ;
     RECT  96.325 55.032 98.22 55.152 ;
     RECT  96.325 55.152 98.196 55.176 ;
     RECT  96.325 55.176 98.22 55.296 ;
     RECT  96.325 55.296 98.196 55.32 ;
     RECT  96.325 55.32 98.22 55.44 ;
     RECT  96.325 55.44 98.196 55.464 ;
     RECT  96.325 55.464 98.22 55.584 ;
     RECT  96.325 55.584 98.196 55.608 ;
     RECT  96.325 55.608 98.22 55.728 ;
     RECT  96.325 55.728 98.196 55.752 ;
     RECT  96.325 55.752 98.22 55.872 ;
     RECT  96.325 55.872 98.196 55.896 ;
     RECT  96.325 55.896 98.22 56.016 ;
     RECT  96.325 56.016 98.196 56.04 ;
     RECT  96.325 56.04 98.22 56.16 ;
     RECT  96.325 56.16 98.196 56.184 ;
     RECT  96.325 56.184 98.22 56.304 ;
     RECT  96.325 56.304 98.196 56.328 ;
     RECT  96.325 56.328 98.22 56.448 ;
     RECT  96.325 56.448 98.196 56.472 ;
     RECT  96.325 56.472 98.22 56.592 ;
     RECT  96.325 56.592 98.196 56.616 ;
     RECT  96.325 56.616 98.22 56.736 ;
     RECT  96.325 56.736 98.196 56.76 ;
     RECT  96.325 56.76 98.22 56.88 ;
     RECT  96.325 56.88 98.196 56.904 ;
     RECT  96.325 56.904 98.22 57.024 ;
     RECT  96.325 57.024 98.196 57.048 ;
     RECT  96.289 81.36 98.196 81.384 ;
     RECT  96.289 81.384 98.22 81.504 ;
     RECT  96.289 81.504 98.196 81.528 ;
     RECT  96.289 81.528 98.22 81.648 ;
     RECT  96.289 81.648 98.196 81.672 ;
     RECT  96.289 81.672 98.22 81.792 ;
     RECT  96.289 81.792 98.196 81.816 ;
     RECT  96.289 81.816 98.22 81.936 ;
     RECT  96.289 81.936 98.196 81.96 ;
     RECT  96.289 81.96 98.22 82.08 ;
     RECT  96.289 82.08 98.196 82.104 ;
     RECT  96.289 82.104 98.22 82.224 ;
     RECT  96.289 82.224 98.196 82.248 ;
     RECT  96.289 82.248 98.22 82.368 ;
     RECT  96.289 82.368 98.196 82.392 ;
     RECT  96.289 82.392 98.22 82.512 ;
     RECT  96.289 82.512 98.196 82.536 ;
     RECT  96.289 82.536 98.22 82.656 ;
     RECT  96.289 82.656 98.196 82.68 ;
     RECT  96.289 82.68 98.22 82.8 ;
     RECT  96.289 82.8 98.196 82.824 ;
     RECT  96.289 82.824 98.22 82.944 ;
     RECT  96.289 82.944 98.196 82.968 ;
     RECT  96.289 82.968 98.22 83.088 ;
     RECT  96.289 83.088 98.196 83.112 ;
     RECT  96.289 83.112 98.22 83.232 ;
     RECT  96.289 83.232 98.196 83.256 ;
     RECT  96.289 83.256 98.22 83.376 ;
     RECT  96.289 83.376 98.196 83.4 ;
     RECT  96.289 83.4 98.22 83.52 ;
     RECT  96.289 83.52 98.196 83.544 ;
     RECT  96.289 83.544 98.22 83.664 ;
     RECT  96.289 83.664 98.196 83.688 ;
     RECT  96.289 83.688 98.22 83.808 ;
     RECT  96.289 83.808 98.196 83.832 ;
     RECT  96.289 83.832 98.22 83.952 ;
     RECT  96.289 83.952 98.196 83.976 ;
     RECT  96.289 83.976 98.22 84.096 ;
     RECT  96.289 84.096 98.196 84.12 ;
     RECT  96.289 84.12 98.22 84.24 ;
     RECT  96.289 84.24 98.196 84.264 ;
     RECT  96.289 84.264 98.22 84.384 ;
     RECT  96.289 84.384 98.196 84.408 ;
     RECT  96.289 84.408 98.22 84.528 ;
     RECT  96.289 84.528 98.196 84.552 ;
     RECT  96.289 84.552 98.22 84.672 ;
     RECT  96.289 84.672 98.196 84.696 ;
     RECT  96.289 84.696 98.22 84.816 ;
     RECT  96.289 84.816 98.196 84.84 ;
     RECT  96.289 84.84 98.22 84.96 ;
     RECT  96.289 84.96 98.196 84.984 ;
     RECT  96.289 84.984 98.22 85.104 ;
     RECT  96.289 85.104 98.196 85.128 ;
     RECT  96.289 85.128 98.22 85.248 ;
     RECT  96.289 85.248 98.196 85.272 ;
     RECT  96.289 85.272 98.22 85.392 ;
     RECT  96.289 85.392 98.196 85.416 ;
     RECT  96.289 85.416 98.22 85.536 ;
     RECT  96.289 85.536 98.196 85.56 ;
     RECT  96.289 85.56 98.22 85.68 ;
     RECT  96.289 85.68 98.196 85.704 ;
     RECT  96.289 85.704 98.22 85.824 ;
     RECT  96.289 85.824 98.196 85.848 ;
     RECT  96.901 96.336 98.196 96.36 ;
     RECT  96.901 96.36 98.22 96.48 ;
     RECT  96.901 96.48 98.196 96.504 ;
     RECT  96.901 96.504 98.22 96.624 ;
     RECT  96.901 96.624 98.196 96.648 ;
     RECT  96.901 96.648 98.22 96.768 ;
     RECT  96.901 96.768 98.196 96.792 ;
     RECT  96.901 96.792 98.22 96.912 ;
     RECT  96.901 96.912 98.196 96.936 ;
     RECT  96.901 96.936 98.22 97.056 ;
     RECT  96.901 97.056 98.196 97.08 ;
     RECT  96.901 97.08 98.22 97.2 ;
     RECT  96.901 97.2 98.196 97.224 ;
     RECT  96.901 97.224 98.22 97.344 ;
     RECT  96.901 97.344 98.196 97.368 ;
     RECT  96.901 97.368 98.22 97.488 ;
     RECT  96.901 97.488 98.196 97.512 ;
     RECT  96.901 97.512 98.22 97.632 ;
     RECT  96.901 97.632 98.196 97.656 ;
     RECT  96.901 97.656 98.22 97.776 ;
     RECT  96.901 97.776 98.196 97.8 ;
     RECT  96.901 97.8 98.22 97.92 ;
     RECT  96.901 97.92 98.196 97.944 ;
     RECT  96.901 97.944 98.22 98.064 ;
     RECT  96.901 98.064 98.196 98.088 ;
     RECT  96.901 98.088 98.22 98.208 ;
     RECT  96.901 98.208 98.196 98.232 ;
     RECT  96.901 98.232 98.22 98.352 ;
     RECT  96.901 98.352 98.196 98.376 ;
     RECT  96.901 98.376 98.22 98.496 ;
     RECT  96.901 98.496 98.196 98.52 ;
     RECT  96.901 98.52 98.22 98.64 ;
     RECT  96.901 98.64 98.196 98.664 ;
     RECT  96.901 98.664 98.22 98.784 ;
     RECT  96.901 98.784 98.196 98.808 ;
     RECT  96.901 98.808 98.22 98.928 ;
     RECT  96.901 98.928 98.196 98.952 ;
     RECT  96.901 98.952 98.22 99.072 ;
     RECT  96.901 99.072 98.196 99.096 ;
     RECT  96.901 99.096 98.22 99.216 ;
     RECT  96.901 99.216 98.196 99.24 ;
     RECT  96.901 99.24 98.22 99.36 ;
     RECT  96.901 99.36 98.196 99.384 ;
     RECT  96.901 99.384 98.22 99.504 ;
     RECT  96.901 99.504 98.196 99.528 ;
     RECT  96.901 99.528 98.22 99.648 ;
     RECT  96.901 99.648 98.196 99.672 ;
     RECT  96.901 99.672 98.22 99.792 ;
     RECT  96.901 99.792 98.196 99.816 ;
     RECT  96.901 99.816 98.22 99.936 ;
     RECT  96.901 99.936 98.196 99.96 ;
     RECT  96.901 99.96 98.22 100.08 ;
     RECT  96.901 100.08 98.196 100.104 ;
     RECT  96.901 100.104 98.22 100.224 ;
     RECT  96.901 100.224 98.196 100.248 ;
     RECT  96.901 100.248 98.22 100.368 ;
     RECT  96.901 100.368 98.196 100.392 ;
     RECT  96.901 100.392 98.22 100.512 ;
     RECT  96.901 100.512 98.196 100.536 ;
     RECT  96.901 100.536 98.22 100.656 ;
     RECT  96.901 100.656 98.196 100.68 ;
     RECT  96.901 100.68 98.22 100.8 ;
     RECT  96.901 100.8 98.196 100.824 ;
     RECT  97.477 125.136 98.196 125.16 ;
     RECT  97.477 125.16 98.22 125.28 ;
     RECT  97.477 125.28 98.196 125.304 ;
     RECT  97.477 125.304 98.22 125.424 ;
     RECT  97.477 125.424 98.196 125.448 ;
     RECT  97.477 125.448 98.22 125.568 ;
     RECT  97.477 125.568 98.196 125.592 ;
     RECT  97.477 125.592 98.22 125.712 ;
     RECT  97.477 125.712 98.196 125.736 ;
     RECT  97.477 125.736 98.22 125.856 ;
     RECT  97.477 125.856 98.196 125.88 ;
     RECT  97.477 125.88 98.22 126 ;
     RECT  97.477 126 98.196 126.024 ;
     RECT  97.477 126.024 98.22 126.144 ;
     RECT  97.477 126.144 98.196 126.168 ;
     RECT  97.477 126.168 98.22 126.288 ;
     RECT  97.477 126.288 98.196 126.312 ;
     RECT  97.477 126.312 98.22 126.432 ;
     RECT  97.477 126.432 98.196 126.456 ;
     RECT  97.477 126.456 98.22 126.576 ;
     RECT  97.477 126.576 98.196 126.6 ;
     RECT  97.477 126.6 98.22 126.72 ;
     RECT  97.477 126.72 98.196 126.744 ;
     RECT  97.477 126.744 98.22 126.864 ;
     RECT  97.477 126.864 98.196 126.888 ;
     RECT  97.477 126.888 98.22 127.008 ;
     RECT  97.477 127.008 98.196 127.032 ;
     RECT  97.513 138.96 98.196 138.984 ;
     RECT  97.513 138.984 98.22 139.104 ;
     RECT  97.513 139.104 98.196 139.128 ;
     RECT  97.513 139.128 98.22 139.248 ;
     RECT  97.513 139.248 98.196 139.272 ;
     RECT  97.513 139.272 98.22 139.392 ;
     RECT  97.513 139.392 98.196 139.416 ;
     RECT  97.513 139.416 98.22 139.536 ;
     RECT  97.513 139.536 98.196 139.56 ;
     RECT  97.513 139.56 98.22 139.68 ;
     RECT  97.513 139.68 98.196 139.704 ;
     RECT  97.513 139.704 98.22 139.824 ;
     RECT  97.513 139.824 98.196 139.848 ;
     RECT  97.513 139.848 98.22 139.968 ;
     RECT  97.513 139.968 98.196 139.992 ;
     RECT  97.513 139.992 98.22 140.112 ;
     RECT  97.513 140.112 98.196 140.136 ;
     RECT  97.513 140.136 98.22 140.256 ;
     RECT  97.513 140.256 98.196 140.28 ;
     RECT  97.513 140.28 98.22 140.4 ;
     RECT  97.513 140.4 98.196 140.424 ;
     RECT  97.513 140.424 98.22 140.544 ;
     RECT  97.513 140.544 98.196 140.568 ;
     RECT  97.513 140.568 98.22 140.688 ;
     RECT  97.513 140.688 98.196 140.712 ;
     RECT  97.513 140.712 98.22 140.832 ;
     RECT  97.513 140.832 98.196 140.856 ;
     RECT  97.513 140.856 98.22 140.976 ;
     RECT  97.513 140.976 98.196 141 ;
     RECT  97.513 141 98.22 141.12 ;
     RECT  97.513 141.12 98.196 141.144 ;
     RECT  97.513 141.144 98.22 141.264 ;
     RECT  97.513 141.264 98.196 141.288 ;
     RECT  97.513 141.288 98.22 141.408 ;
     RECT  97.513 141.408 98.196 141.432 ;
     RECT  97.513 141.432 98.22 141.552 ;
     RECT  97.513 141.552 98.196 141.576 ;
     RECT  97.513 141.576 98.22 141.696 ;
     RECT  97.513 141.696 98.196 141.72 ;
     RECT  97.513 141.72 98.22 141.84 ;
     RECT  97.513 141.84 98.196 141.864 ;
     RECT  97.513 141.864 98.22 141.984 ;
     RECT  97.513 141.984 98.196 142.008 ;
     RECT  97.513 142.008 98.22 142.128 ;
     RECT  97.513 142.128 98.196 142.152 ;
     RECT  97.513 142.152 98.22 142.272 ;
     RECT  97.513 142.272 98.196 142.296 ;
     RECT  97.513 142.296 98.22 142.416 ;
     RECT  97.513 142.416 98.196 142.44 ;
     RECT  97.513 142.44 98.22 142.56 ;
     RECT  97.513 142.56 98.196 142.584 ;
     RECT  97.513 142.584 98.22 142.704 ;
     RECT  97.513 142.704 98.196 142.728 ;
     RECT  97.513 142.728 98.22 142.848 ;
     RECT  97.513 142.848 98.196 142.872 ;
     RECT  97.513 142.872 98.22 142.992 ;
     RECT  97.513 142.992 98.196 143.016 ;
     RECT  97.513 143.016 98.22 143.136 ;
     RECT  97.513 143.136 98.196 143.16 ;
     RECT  97.513 143.16 98.22 143.28 ;
     RECT  97.513 143.28 98.196 143.304 ;
     RECT  97.513 143.304 98.22 143.424 ;
     RECT  97.513 143.424 98.196 143.448 ;
     RECT  98.22 142.608 98.273 142.632 ;
    LAYER M5 ;
     RECT  2.4 2.137 2.52 2.151 ;
     RECT  5.1 2.137 5.22 2.151 ;
     RECT  7.8 2.137 7.92 2.151 ;
     RECT  10.5 2.137 10.62 2.151 ;
     RECT  13.2 2.137 13.32 2.151 ;
     RECT  15.9 2.137 16.02 2.151 ;
     RECT  18.6 2.137 18.72 2.151 ;
     RECT  21.3 2.137 21.42 2.151 ;
     RECT  24 2.137 24.12 2.151 ;
     RECT  26.7 2.137 26.82 2.151 ;
     RECT  29.4 2.137 29.52 2.151 ;
     RECT  32.1 2.137 32.22 2.151 ;
     RECT  34.8 2.137 34.92 2.151 ;
     RECT  37.5 2.137 37.62 2.151 ;
     RECT  40.2 2.137 40.32 2.151 ;
     RECT  42.9 2.137 43.02 2.151 ;
     RECT  45.6 2.137 45.72 2.151 ;
     RECT  48.3 2.137 48.42 2.151 ;
     RECT  51 2.137 51.12 2.151 ;
     RECT  53.7 2.137 53.82 2.151 ;
     RECT  56.4 2.137 56.52 2.151 ;
     RECT  59.1 2.137 59.22 2.151 ;
     RECT  61.8 2.137 61.92 2.151 ;
     RECT  64.5 2.137 64.62 2.151 ;
     RECT  67.2 2.137 67.32 2.151 ;
     RECT  69.9 2.137 70.02 2.151 ;
     RECT  72.6 2.137 72.72 2.151 ;
     RECT  75.3 2.137 75.42 2.151 ;
     RECT  78 2.137 78.12 2.151 ;
     RECT  80.7 2.137 80.82 2.151 ;
     RECT  83.4 2.137 83.52 2.151 ;
     RECT  86.1 2.137 86.22 2.151 ;
     RECT  88.8 2.137 88.92 2.151 ;
     RECT  91.5 2.137 91.62 2.151 ;
     RECT  94.2 2.137 94.32 2.151 ;
     RECT  7.8 2.151 8.112 31.861 ;
     RECT  7.104 31.861 8.112 32.483 ;
     RECT  7.8 32.483 8.112 33.541 ;
     RECT  42.9 2.151 43.212 33.637 ;
     RECT  7.2 33.541 8.112 33.925 ;
     RECT  7.2 33.925 8.232 34.835 ;
     RECT  7.2 34.835 8.112 35.029 ;
     RECT  5.1 2.151 5.412 35.845 ;
     RECT  6.864 35.029 8.112 36.421 ;
     RECT  6.864 36.421 8.376 37.667 ;
     RECT  4.512 35.845 5.412 38.053 ;
     RECT  88.8 2.151 89.112 39.253 ;
     RECT  42.528 33.637 43.212 39.301 ;
     RECT  4.512 38.053 6.36 39.779 ;
     RECT  13.2 2.151 13.512 39.877 ;
     RECT  88.8 39.253 89.544 39.923 ;
     RECT  94.2 2.151 94.512 40.405 ;
     RECT  42.144 39.301 43.212 40.453 ;
     RECT  42.096 40.453 43.212 40.549 ;
     RECT  40.2 2.151 40.512 40.597 ;
     RECT  13.2 39.877 13.608 40.739 ;
     RECT  91.5 2.151 91.812 40.981 ;
     RECT  39.792 40.597 40.512 41.123 ;
     RECT  4.512 39.779 5.976 41.363 ;
     RECT  75.3 2.151 75.612 41.605 ;
     RECT  4.512 41.363 5.412 41.699 ;
     RECT  7.8 37.667 8.376 42.227 ;
     RECT  93.6 40.405 94.512 42.323 ;
     RECT  75.168 41.605 75.612 43.091 ;
     RECT  7.8 42.227 8.112 43.717 ;
     RECT  6.816 43.717 8.112 44.627 ;
     RECT  42.048 40.549 43.212 45.443 ;
     RECT  42.096 45.443 43.212 45.731 ;
     RECT  42.144 45.731 43.212 46.883 ;
     RECT  91.392 40.981 91.812 48.421 ;
     RECT  93.888 42.323 94.512 48.421 ;
     RECT  93.888 48.421 95.064 48.707 ;
     RECT  40.2 41.123 40.512 50.101 ;
     RECT  39.792 50.101 40.512 51.395 ;
     RECT  37.5 2.151 37.812 52.069 ;
     RECT  37.5 52.069 38.328 52.405 ;
     RECT  94.2 48.707 95.064 52.835 ;
     RECT  37.5 52.405 38.952 53.603 ;
     RECT  92.976 52.981 93 54.611 ;
     RECT  94.2 52.835 94.512 55.285 ;
     RECT  93.504 55.285 94.512 56.435 ;
     RECT  91.152 48.421 91.812 56.821 ;
     RECT  90.624 56.821 91.812 56.963 ;
     RECT  78 2.151 78.312 60.661 ;
     RECT  38.928 53.603 38.952 60.707 ;
     RECT  91.056 56.963 91.812 60.803 ;
     RECT  42.432 46.883 43.212 64.693 ;
     RECT  42.144 64.693 43.212 64.933 ;
     RECT  67.2 2.151 67.512 73.813 ;
     RECT  21.3 2.151 21.612 74.869 ;
     RECT  2.4 2.151 2.712 75.781 ;
     RECT  5.1 41.699 5.412 76.309 ;
     RECT  2.4 75.781 3.432 76.979 ;
     RECT  4.752 76.309 5.412 76.979 ;
     RECT  12.048 39.733 12.072 77.027 ;
     RECT  5.1 76.979 5.412 77.173 ;
     RECT  91.152 60.803 91.812 81.875 ;
     RECT  88.8 39.923 89.112 81.973 ;
     RECT  88.704 81.973 89.112 82.739 ;
     RECT  42.144 64.933 43.32 83.605 ;
     RECT  75.3 43.091 75.612 83.749 ;
     RECT  41.952 83.605 43.32 83.795 ;
     RECT  75.3 83.749 75.72 84.083 ;
     RECT  91.5 81.875 91.812 84.085 ;
     RECT  77.184 60.661 78.312 84.131 ;
     RECT  5.1 77.173 6.264 84.179 ;
     RECT  41.952 83.795 43.212 84.325 ;
     RECT  64.5 2.151 64.812 84.325 ;
     RECT  5.1 84.179 5.976 85.381 ;
     RECT  0.144 85.381 0.168 85.811 ;
     RECT  90.192 84.181 90.216 85.811 ;
     RECT  91.5 84.085 92.232 85.909 ;
     RECT  40.2 51.395 40.512 86.005 ;
     RECT  41.76 84.325 43.212 86.005 ;
     RECT  94.2 56.435 94.512 86.005 ;
     RECT  2.4 76.979 2.712 86.581 ;
     RECT  5.1 85.381 6.024 86.675 ;
     RECT  93.6 86.005 94.512 86.675 ;
     RECT  7.8 44.627 8.112 86.725 ;
     RECT  2.4 86.581 3.432 86.819 ;
     RECT  7.008 86.725 8.112 87.251 ;
     RECT  5.1 86.675 5.976 87.827 ;
     RECT  2.4 86.819 2.712 87.925 ;
     RECT  2.304 87.925 2.712 88.115 ;
     RECT  40.2 86.005 43.212 88.213 ;
     RECT  75.3 84.083 75.612 88.645 ;
     RECT  75.3 88.645 75.816 88.787 ;
     RECT  39.792 88.213 43.212 94.021 ;
     RECT  91.5 85.909 92.568 94.021 ;
     RECT  39.696 94.021 43.212 95.027 ;
     RECT  91.5 94.021 92.616 96.901 ;
     RECT  94.2 86.675 94.512 96.901 ;
     RECT  91.5 96.901 94.512 97.235 ;
     RECT  93.456 97.235 94.512 98.581 ;
     RECT  93.408 98.581 94.512 99.731 ;
     RECT  37.5 53.603 37.812 99.973 ;
     RECT  91.5 97.235 92.232 100.741 ;
     RECT  39.84 95.027 43.212 104.387 ;
     RECT  64.5 84.325 65.112 105.491 ;
     RECT  39.84 104.387 40.512 105.925 ;
     RECT  37.5 99.973 37.992 105.973 ;
     RECT  39.456 105.925 40.512 105.973 ;
     RECT  41.76 104.387 43.212 107.941 ;
     RECT  37.5 105.973 40.512 109.957 ;
     RECT  37.5 109.957 40.632 110.485 ;
     RECT  36.576 110.485 40.632 114.517 ;
     RECT  41.76 107.941 43.32 114.517 ;
     RECT  36.576 114.517 43.32 114.611 ;
     RECT  21.3 74.869 22.488 117.107 ;
     RECT  7.8 87.251 8.112 117.493 ;
     RECT  7.104 117.493 8.112 119.269 ;
     RECT  34.8 2.151 35.112 119.653 ;
     RECT  7.104 119.269 8.472 119.987 ;
     RECT  36.576 114.611 41.016 120.805 ;
     RECT  42.48 114.611 43.32 120.805 ;
     RECT  5.1 87.827 5.412 121.381 ;
     RECT  42.384 120.805 43.32 121.475 ;
     RECT  36.528 120.805 41.016 121.811 ;
     RECT  36.576 121.811 41.016 122.485 ;
     RECT  0.144 122.389 0.168 122.531 ;
     RECT  42.672 121.475 43.32 122.533 ;
     RECT  7.104 119.987 8.112 122.917 ;
     RECT  36.576 122.485 41.304 122.917 ;
     RECT  42.288 122.533 43.32 122.917 ;
     RECT  4.992 121.381 5.412 123.061 ;
     RECT  36.576 122.917 43.32 123.251 ;
     RECT  36.576 123.251 41.304 123.731 ;
     RECT  7.008 122.917 8.376 124.307 ;
     RECT  34.8 119.653 35.208 124.307 ;
     RECT  42.288 123.251 43.32 124.307 ;
     RECT  36.576 123.731 41.016 124.789 ;
     RECT  36.576 124.789 41.496 125.413 ;
     RECT  42.48 124.307 43.32 125.413 ;
     RECT  91.5 100.741 92.616 125.651 ;
     RECT  75.3 88.787 75.612 125.701 ;
     RECT  88.8 82.739 89.112 125.893 ;
     RECT  91.5 125.651 91.812 126.133 ;
     RECT  66.288 73.813 67.512 126.179 ;
     RECT  88.8 125.893 90.072 126.707 ;
     RECT  91.152 126.133 91.812 126.757 ;
     RECT  34.8 124.307 35.112 126.949 ;
     RECT  36.576 125.413 43.32 127.091 ;
     RECT  37.008 127.091 41.016 127.235 ;
     RECT  34.8 126.949 35.544 128.485 ;
     RECT  34.608 128.485 35.544 129.251 ;
     RECT  42.096 127.091 43.32 129.491 ;
     RECT  37.008 127.235 38.424 129.877 ;
     RECT  2.4 88.115 2.712 129.973 ;
     RECT  34.608 129.251 35.112 130.019 ;
     RECT  4.944 123.061 5.412 130.115 ;
     RECT  2.304 129.973 2.712 130.211 ;
     RECT  7.8 124.307 8.376 130.499 ;
     RECT  5.1 130.115 5.412 130.885 ;
     RECT  36.96 129.877 38.424 131.029 ;
     RECT  34.8 130.019 35.112 131.077 ;
     RECT  78 84.131 78.312 131.077 ;
     RECT  91.152 126.757 92.76 131.077 ;
     RECT  90.624 131.077 92.76 131.219 ;
     RECT  76.992 126.325 77.016 131.315 ;
     RECT  5.1 130.885 6.168 131.699 ;
     RECT  34.8 131.077 35.208 131.699 ;
     RECT  36.96 131.029 38.472 132.035 ;
     RECT  42.096 129.491 43.212 132.131 ;
     RECT  78 131.077 78.696 132.131 ;
     RECT  91.152 131.219 92.76 132.227 ;
     RECT  42.528 132.131 43.212 132.419 ;
     RECT  42.576 132.419 43.212 132.515 ;
     RECT  91.152 132.227 91.812 132.517 ;
     RECT  78 132.131 78.312 132.757 ;
     RECT  37.008 132.035 38.472 133.621 ;
     RECT  39.456 127.235 41.016 133.621 ;
     RECT  77.568 132.757 78.312 133.715 ;
     RECT  75.3 125.701 75.816 134.627 ;
     RECT  75.3 134.627 75.72 134.723 ;
     RECT  37.008 133.621 41.016 136.547 ;
     RECT  37.008 136.547 38.424 140.243 ;
     RECT  91.104 132.517 91.812 140.435 ;
     RECT  91.152 140.435 91.812 140.819 ;
     RECT  37.392 140.243 38.424 140.915 ;
     RECT  37.5 140.915 38.424 141.877 ;
     RECT  88.8 126.707 89.112 141.877 ;
     RECT  88.8 141.877 89.496 143.123 ;
     RECT  39.456 136.547 41.016 143.171 ;
     RECT  37.392 141.877 38.424 144.085 ;
     RECT  39.456 143.171 40.776 144.085 ;
     RECT  37.392 144.085 40.776 147.155 ;
     RECT  37.392 147.155 40.728 147.779 ;
     RECT  37.392 147.779 40.512 165.923 ;
     RECT  37.5 165.923 40.512 166.355 ;
     RECT  2.4 130.211 2.712 168.489 ;
     RECT  5.1 131.699 5.412 168.489 ;
     RECT  7.8 130.499 8.112 168.489 ;
     RECT  10.5 2.151 10.812 168.489 ;
     RECT  13.2 40.739 13.512 168.489 ;
     RECT  15.9 2.151 16.212 168.489 ;
     RECT  18.6 2.151 18.912 168.489 ;
     RECT  21.3 117.107 21.612 168.489 ;
     RECT  24 2.151 24.312 168.489 ;
     RECT  26.7 2.151 27.012 168.489 ;
     RECT  29.4 2.151 29.712 168.489 ;
     RECT  32.1 2.151 32.412 168.489 ;
     RECT  34.8 131.699 35.112 168.489 ;
     RECT  39.456 166.355 40.512 168.489 ;
     RECT  42.9 132.515 43.212 168.489 ;
     RECT  45.6 2.151 45.912 168.489 ;
     RECT  48.3 2.151 48.612 168.489 ;
     RECT  51 2.151 51.312 168.489 ;
     RECT  53.7 2.151 54.012 168.489 ;
     RECT  56.4 2.151 56.712 168.489 ;
     RECT  59.1 2.151 59.412 168.489 ;
     RECT  61.8 2.151 62.112 168.489 ;
     RECT  64.5 105.491 64.812 168.489 ;
     RECT  67.2 126.179 67.512 168.489 ;
     RECT  69.9 2.151 70.212 168.489 ;
     RECT  72.6 2.151 72.912 168.489 ;
     RECT  75.3 134.723 75.612 168.489 ;
     RECT  78 133.715 78.312 168.489 ;
     RECT  80.7 2.151 81.012 168.489 ;
     RECT  83.4 2.151 83.712 168.489 ;
     RECT  86.1 2.151 86.412 168.489 ;
     RECT  88.8 143.123 89.112 168.489 ;
     RECT  91.5 140.819 91.812 168.489 ;
     RECT  94.2 99.731 94.512 168.489 ;
     RECT  2.4 168.489 2.52 168.503 ;
     RECT  5.1 168.489 5.22 168.503 ;
     RECT  7.8 168.489 7.92 168.503 ;
     RECT  10.5 168.489 10.62 168.503 ;
     RECT  13.2 168.489 13.32 168.503 ;
     RECT  15.9 168.489 16.02 168.503 ;
     RECT  18.6 168.489 18.72 168.503 ;
     RECT  21.3 168.489 21.42 168.503 ;
     RECT  24 168.489 24.12 168.503 ;
     RECT  26.7 168.489 26.82 168.503 ;
     RECT  29.4 168.489 29.52 168.503 ;
     RECT  32.1 168.489 32.22 168.503 ;
     RECT  34.8 168.489 34.92 168.503 ;
     RECT  37.5 166.355 37.992 168.503 ;
     RECT  39.456 168.489 40.32 168.503 ;
     RECT  42.9 168.489 43.02 168.503 ;
     RECT  45.6 168.489 45.72 168.503 ;
     RECT  48.3 168.489 48.42 168.503 ;
     RECT  51 168.489 51.12 168.503 ;
     RECT  53.7 168.489 53.82 168.503 ;
     RECT  56.4 168.489 56.52 168.503 ;
     RECT  59.1 168.489 59.22 168.503 ;
     RECT  61.8 168.489 61.92 168.503 ;
     RECT  64.5 168.489 64.62 168.503 ;
     RECT  67.2 168.489 67.32 168.503 ;
     RECT  69.9 168.489 70.02 168.503 ;
     RECT  72.6 168.489 72.72 168.503 ;
     RECT  75.3 168.489 75.42 168.503 ;
     RECT  78 168.489 78.12 168.503 ;
     RECT  80.7 168.489 80.82 168.503 ;
     RECT  83.4 168.489 83.52 168.503 ;
     RECT  86.1 168.489 86.22 168.503 ;
     RECT  88.8 168.489 88.92 168.503 ;
     RECT  91.5 168.489 91.62 168.503 ;
     RECT  94.2 168.489 94.32 168.503 ;
     RECT  39.456 168.503 39.48 170.483 ;
     RECT  37.968 168.503 37.992 170.531 ;
     RECT  7.2 32.483 7.8 33.541 ;
     RECT  5.412 35.029 6.864 37.667 ;
     RECT  5.412 37.667 7.8 38.053 ;
     RECT  6.36 38.053 7.8 39.779 ;
     RECT  10.812 39.733 12.048 77.027 ;
     RECT  12.072 39.733 13.2 77.027 ;
     RECT  5.412 43.717 6.816 44.627 ;
     RECT  39.792 51.395 40.2 52.069 ;
     RECT  38.328 52.069 40.2 52.405 ;
     RECT  38.952 52.405 40.2 60.707 ;
     RECT  91.812 52.981 92.976 54.611 ;
     RECT  93 52.981 94.2 54.611 ;
     RECT  37.812 53.603 38.928 60.707 ;
     RECT  93.504 54.611 94.2 55.285 ;
     RECT  89.112 56.821 90.624 56.963 ;
     RECT  64.812 73.813 66.288 84.325 ;
     RECT  22.488 74.869 24 117.107 ;
     RECT  3.432 76.309 4.752 76.979 ;
     RECT  40.512 83.605 41.952 84.325 ;
     RECT  75.72 83.749 77.184 84.083 ;
     RECT  5.976 84.179 6.024 85.381 ;
     RECT  89.112 84.181 90.192 85.811 ;
     RECT  90.216 84.181 91.5 85.811 ;
     RECT  40.512 84.325 41.76 86.005 ;
     RECT  65.112 84.325 66.288 105.491 ;
     RECT  92.568 86.005 93.6 86.675 ;
     RECT  5.976 86.675 6.024 86.725 ;
     RECT  5.976 86.725 7.008 87.251 ;
     RECT  92.232 97.235 93.456 98.581 ;
     RECT  92.232 98.581 93.408 99.731 ;
     RECT  92.232 99.731 92.616 100.741 ;
     RECT  40.512 104.387 41.76 109.957 ;
     RECT  64.812 105.491 66.288 126.179 ;
     RECT  37.992 105.925 39.456 105.973 ;
     RECT  40.632 109.957 41.76 114.517 ;
     RECT  35.112 110.485 36.576 119.653 ;
     RECT  41.016 114.611 42.48 120.805 ;
     RECT  35.208 119.653 36.576 120.805 ;
     RECT  35.208 120.805 36.528 121.811 ;
     RECT  41.016 120.805 42.384 121.475 ;
     RECT  41.016 121.475 42.672 122.485 ;
     RECT  35.208 121.811 36.576 124.307 ;
     RECT  41.304 122.485 42.672 122.533 ;
     RECT  41.304 122.533 42.288 122.917 ;
     RECT  41.304 123.251 42.288 123.731 ;
     RECT  41.016 123.731 42.288 124.307 ;
     RECT  35.112 124.307 36.576 126.949 ;
     RECT  41.016 124.307 42.48 124.789 ;
     RECT  41.496 124.789 42.48 125.413 ;
     RECT  91.812 125.651 92.616 126.757 ;
     RECT  90.072 125.893 91.5 126.133 ;
     RECT  90.072 126.133 91.152 126.707 ;
     RECT  75.816 126.325 76.992 131.315 ;
     RECT  77.016 126.325 78 131.315 ;
     RECT  92.76 126.757 94.2 132.227 ;
     RECT  35.544 126.949 36.576 127.091 ;
     RECT  35.544 127.091 37.008 129.251 ;
     RECT  41.016 127.091 42.096 132.131 ;
     RECT  38.424 127.235 39.456 131.029 ;
     RECT  36.96 129.251 37.008 129.877 ;
     RECT  38.472 131.029 39.456 133.621 ;
     RECT  89.112 131.077 90.624 131.219 ;
     RECT  91.104 131.219 91.152 132.517 ;
     RECT  77.568 131.315 78 132.757 ;
     RECT  41.016 132.131 42.528 132.419 ;
     RECT  38.424 136.547 39.456 144.085 ;
     RECT  37.392 140.915 37.5 141.877 ;
     RECT  37.992 166.355 39.456 170.483 ;
  END
END qfd_landh0d8sn_174_EW_98x171
END LIBRARY
